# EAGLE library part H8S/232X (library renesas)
H8S/232Xseries in120 pin package

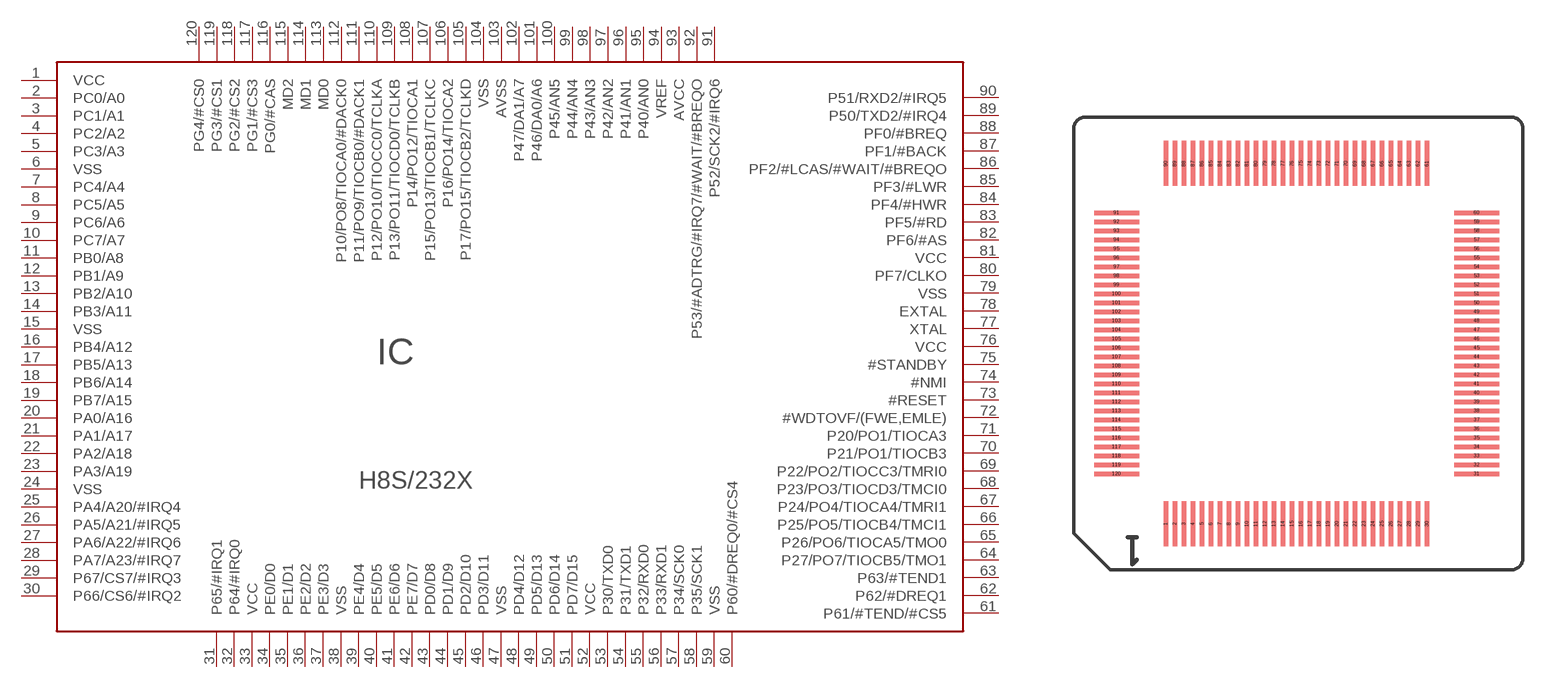
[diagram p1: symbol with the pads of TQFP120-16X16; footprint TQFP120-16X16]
Designator prefix IC

## H8S/232X-120  [TQFP120-16X16]
1  VCC  pwr
2  PC0/A0
3  PC1/A1
4  PC2/A2
5  PC3/A3
6  VSS  pwr
7  PC4/A4
8  PC5/A5
9  PC6/A6
10  PC7/A7
11  PB0/A8
12  PB1/A9
13  PB2/A10
14  PB3/A11
15  VSS  pwr
16  PB4/A12
17  PB5/A13
18  PB6/A14
19  PB7/A15
20  PA0/A16
21  PA1/A17
22  PA2/A18
23  PA3/A19
24  VSS  pwr
25  PA4/A20/#IRQ4
26  PA5/A21/#IRQ5
27  PA6/A22/#IRQ6
28  PA7/A23/#IRQ7
29  P67/CS7/#IRQ3
30  P66/CS6/#IRQ2
31  P65/#IRQ1
32  P64/#IRQ0
33  VCC  pwr
34  PE0/D0
35  PE1/D1
36  PE2/D2
37  PE3/D3
38  VSS  pwr
39  PE4/D4
40  PE5/D5
41  PE6/D6
42  PE7/D7
43  PD0/D8
44  PD1/D9
45  PD2/D10
46  PD3/D11
47  VSS  pwr
48  PD4/D12
49  PD5/D13
50  PD6/D14
51  PD7/D15
52  VCC  pwr
53  P30/TXD0
54  P31/TXD1
55  P32/RXD0
56  P33/RXD1
57  P34/SCK0
58  P35/SCK1
59  VSS  pwr
60  P60/#DREQ0/#CS4
61  P61/#TEND/#CS5
62  P62/#DREQ1
63  P63/#TEND1
64  P27/PO7/TIOCB5/TMO1
65  P26/PO6/TIOCA5/TMO0
66  P25/PO5/TIOCB4/TMCI1
67  P24/PO4/TIOCA4/TMRI1
68  P23/PO3/TIOCD3/TMCI0
69  P22/PO2/TIOCC3/TMRI0
70  P21/PO1/TIOCB3
71  P20/PO1/TIOCA3
72  #WDTOVF/(FWE,EMLE)
73  #RESET  in
74  #NMI  in
75  #STANDBY  in
76  VCC  pwr
77  XTAL  pas
78  EXTAL  in
79  VSS  pwr
80  PF7/CLKO
81  VCC  pwr
82  PF6/#AS
83  PF5/#RD
84  PF4/#HWR
85  PF3/#LWR
86  PF2/#LCAS/#WAIT/#BREQO
87  PF1/#BACK
88  PF0/#BREQ
89  P50/TXD2/#IRQ4
90  P51/RXD2/#IRQ5
91  P52/SCK2/#IRQ6
92  P53/#ADTRG/#IRQ7/#WAIT/#BREQO
93  AVCC  pwr
94  VREF  pwr
95  P40/AN0
96  P41/AN1
97  P42/AN2
98  P43/AN3
99  P44/AN4
100  P45/AN5
101  P46/DA0/A6
102  P47/DA1/A7
103  AVSS  pwr
104  VSS  pwr
105  P17/PO15/TIOCB2/TCLKD
106  P16/PO14/TIOCA2
107  P15/PO13/TIOCB1/TCLKC
108  P14/PO12/TIOCA1
109  P13/PO11/TIOCD0/TCLKB
110  P12/PO10/TIOCC0/TCLKA
111  P11/PO9/TIOCB0/#DACK1
112  P10/PO8/TIOCA0/#DACK0
113  MD0  in
114  MD1  in
115  MD2  in
116  PG0/#CAS
117  PG1/#CS3
118  PG2/#CS2
119  PG3/#CS1
120  PG4/#CS0

## Footprint TQFP120-16X16 (pad centres in mm)
TQFP120 16x16mm 0.4mm pitch 0.2mm pad width
smd 0.2 x 2: 1 -5.8,-8; 2 -5.4,-8; 3 -5,-8; 4 -4.6,-8; 5 -4.2,-8; 6 -3.8,-8; 7 -3.4,-8; 8 -3,-8; 9 -2.6,-8; 10 -2.2,-8; 11 -1.8,-8; 12 -1.4,-8; 13 -1,-8; 14 -0.6,-8; 15 -0.2,-8; 16 0.2,-8; 17 0.6,-8; 18 1,-8; 19 1.4,-8; 20 1.8,-8; 21 2.2,-8; 22 2.6,-8; 23 3,-8; 24 3.4,-8; 25 3.8,-8; 26 4.2,-8; 27 4.6,-8; 28 5,-8; 29 5.4,-8; 30 5.8,-8; 61 5.8,8; 62 5.4,8; 63 5,8; 64 4.6,8; 65 4.2,8; 66 3.8,8; 67 3.4,8; 68 3,8; 69 2.6,8; 70 2.2,8; 71 1.8,8; 72 1.4,8; 73 1,8; 74 0.6,8; 75 0.2,8; 76 -0.2,8; 77 -0.6,8; 78 -1,8; 79 -1.4,8; 80 -1.8,8; 81 -2.2,8; 82 -2.6,8; 83 -3,8; 84 -3.4,8; 85 -3.8,8; 86 -4.2,8; 87 -4.6,8; 88 -5,8; 89 -5.4,8; 90 -5.8,8
smd 2 x 0.2: 31 8,-5.8; 32 8,-5.4; 33 8,-5; 34 8,-4.6; 35 8,-4.2; 36 8,-3.8; 37 8,-3.4; 38 8,-3; 39 8,-2.6; 40 8,-2.2; 41 8,-1.8; 42 8,-1.4; 43 8,-1; 44 8,-0.6; 45 8,-0.2; 46 8,0.2; 47 8,0.6; 48 8,1; 49 8,1.4; 50 8,1.8; 51 8,2.2; 52 8,2.6; 53 8,3; 54 8,3.4; 55 8,3.8; 56 8,4.2; 57 8,4.6; 58 8,5; 59 8,5.4; 60 8,5.8; 91 -8,5.8; 92 -8,5.4; 93 -8,5; 94 -8,4.6; 95 -8,4.2; 96 -8,3.8; 97 -8,3.4; 98 -8,3; 99 -8,2.6; 100 -8,2.2; 101 -8,1.8; 102 -8,1.4; 103 -8,1; 104 -8,0.6; 105 -8,0.2; 106 -8,-0.2; 107 -8,-0.6; 108 -8,-1; 109 -8,-1.4; 110 -8,-1.8; 111 -8,-2.2; 112 -8,-2.6; 113 -8,-3; 114 -8,-3.4; 115 -8,-3.8; 116 -8,-4.2; 117 -8,-4.6; 118 -8,-5; 119 -8,-5.4; 120 -8,-5.8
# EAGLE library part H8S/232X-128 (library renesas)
H8S/232X series in 128pin package

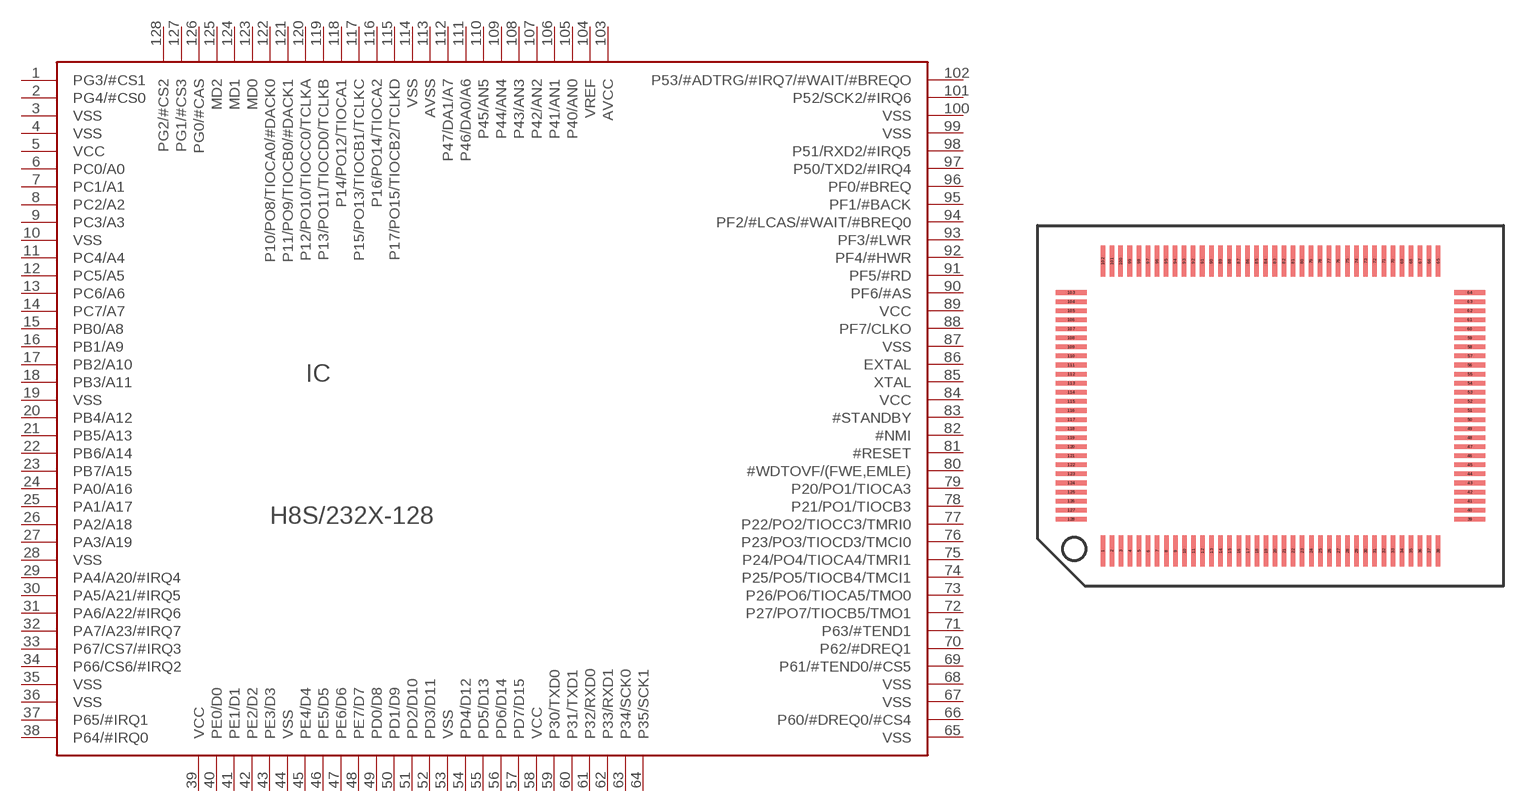
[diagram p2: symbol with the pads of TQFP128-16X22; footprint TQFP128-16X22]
Designator prefix IC

## H8S/232X-128  [TQFP128-16X22]
1  PG3/#CS1
2  PG4/#CS0
3  VSS  pwr
4  VSS  pwr
5  VCC  pwr
6  PC0/A0
7  PC1/A1
8  PC2/A2
9  PC3/A3
10  VSS  pwr
11  PC4/A4
12  PC5/A5
13  PC6/A6
14  PC7/A7
15  PB0/A8
16  PB1/A9
17  PB2/A10
18  PB3/A11
19  VSS  pwr
20  PB4/A12
21  PB5/A13
22  PB6/A14
23  PB7/A15
24  PA0/A16
25  PA1/A17
26  PA2/A18
27  PA3/A19
28  VSS  pwr
29  PA4/A20/#IRQ4
30  PA5/A21/#IRQ5
31  PA6/A22/#IRQ6
32  PA7/A23/#IRQ7
33  P67/CS7/#IRQ3
34  P66/CS6/#IRQ2
35  VSS  pwr
36  VSS  pwr
37  P65/#IRQ1
38  P64/#IRQ0
39  VCC  pwr
40  PE0/D0
41  PE1/D1
42  PE2/D2
43  PE3/D3
44  VSS  pwr
45  PE4/D4
46  PE5/D5
47  PE6/D6
48  PE7/D7
49  PD0/D8
50  PD1/D9
51  PD2/D10
52  PD3/D11
53  VSS  pwr
54  PD4/D12
55  PD5/D13
56  PD6/D14
57  PD7/D15
58  VCC  pwr
59  P30/TXD0
60  P31/TXD1
61  P32/RXD0
62  P33/RXD1
63  P34/SCK0
64  P35/SCK1
65  VSS  pwr
66  P60/#DREQ0/#CS4
67  VSS  pwr
68  VSS  pwr
69  P61/#TEND0/#CS5
70  P62/#DREQ1
71  P63/#TEND1
72  P27/PO7/TIOCB5/TMO1
73  P26/PO6/TIOCA5/TMO0
74  P25/PO5/TIOCB4/TMCI1
75  P24/PO4/TIOCA4/TMRI1
76  P23/PO3/TIOCD3/TMCI0
77  P22/PO2/TIOCC3/TMRI0
78  P21/PO1/TIOCB3
79  P20/PO1/TIOCA3
80  #WDTOVF/(FWE,EMLE)  in
81  #RESET  in
82  #NMI  in
83  #STANDBY  in
84  VCC  pwr
85  XTAL  pas
86  EXTAL  in
87  VSS  pwr
88  PF7/CLKO
89  VCC  pwr
90  PF6/#AS
91  PF5/#RD
92  PF4/#HWR
93  PF3/#LWR
94  PF2/#LCAS/#WAIT/#BREQ0
95  PF1/#BACK
96  PF0/#BREQ
97  P50/TXD2/#IRQ4
98  P51/RXD2/#IRQ5
99  VSS  pwr
100  VSS  pwr
101  P52/SCK2/#IRQ6
102  P53/#ADTRG/#IRQ7/#WAIT/#BREQO
103  AVCC  pwr
104  VREF  pwr
105  P40/AN0
106  P41/AN1
107  P42/AN2
108  P43/AN3
109  P44/AN4
110  P45/AN5
111  P46/DA0/A6
112  P47/DA1/A7
113  AVSS  pwr
114  VSS  pwr
115  P17/PO15/TIOCB2/TCLKD
116  P16/PO14/TIOCA2
117  P15/PO13/TIOCB1/TCLKC
118  P14/PO12/TIOCA1
119  P13/PO11/TIOCD0/TCLKB
120  P12/PO10/TIOCC0/TCLKA
121  P11/PO9/TIOCB0/#DACK1
122  P10/PO8/TIOCA0/#DACK0
123  MD0  in
124  MD1  in
125  MD2  in
126  PG0/#CAS
127  PG1/#CS3
128  PG2/#CS2

## Footprint TQFP128-16X22 (pad centres in mm)
TQFP128 16x22mm 0.5mm pitch 0.25mm pad width
smd 0.25 x 1.7: 1 -9.25,-8; 2 -8.75,-8; 3 -8.25,-8; 4 -7.75,-8; 5 -7.25,-8; 6 -6.75,-8; 7 -6.25,-8; 8 -5.75,-8; 9 -5.25,-8; 10 -4.75,-8; 11 -4.25,-8; 12 -3.75,-8; 13 -3.25,-8; 14 -2.75,-8; 15 -2.25,-8; 16 -1.75,-8; 17 -1.25,-8; 18 -0.75,-8; 19 -0.25,-8; 20 0.25,-8; 21 0.75,-8; 22 1.25,-8; 23 1.75,-8; 24 2.25,-8; 25 2.75,-8; 26 3.25,-8; 27 3.75,-8; 28 4.25,-8; 29 4.75,-8; 30 5.25,-8; 31 5.75,-8; 32 6.25,-8; 33 6.75,-8; 34 7.25,-8; 35 7.75,-8; 36 8.25,-8; 37 8.75,-8; 38 9.25,-8; 65 9.25,8; 66 8.75,8; 67 8.25,8; 68 7.75,8; 69 7.25,8; 70 6.75,8; 71 6.25,8; 72 5.75,8; 73 5.25,8; 74 4.75,8; 75 4.25,8; 76 3.735,7.995; 77 3.235,7.995; 78 2.735,7.995; 79 2.235,7.995; 80 1.735,7.995; 81 1.235,7.995; 82 0.735,7.995; 83 0.235,7.995; 84 -0.265,7.995; 85 -0.765,7.995; 86 -1.265,7.995; 87 -1.765,7.995; 88 -2.265,7.995; 89 -2.765,7.995; 90 -3.265,7.995; 91 -3.765,7.995; 92 -4.265,7.995; 93 -4.765,7.995; 94 -5.265,7.995; 95 -5.765,7.995; 96 -6.265,7.995; 97 -6.765,7.995; 98 -7.265,7.995; 99 -7.765,7.995; 100 -8.265,7.995; 101 -8.75,8; 102 -9.25,8
smd 1.7 x 0.25: 39 11,-6.25; 40 11,-5.75; 41 11,-5.25; 42 11,-4.75; 43 11,-4.25; 44 11,-3.75; 45 11,-3.25; 46 11,-2.75; 47 11,-2.25; 48 11,-1.75; 49 11,-1.25; 50 11,-0.75; 51 11,-0.24; 52 11,0.26; 53 11,0.76; 54 11,1.26; 55 11,1.76; 56 11,2.26; 57 11,2.76; 58 11,3.26; 59 11,3.76; 60 11,4.26; 61 11,4.76; 62 11,5.26; 63 11,5.76; 64 11,6.26; 103 -11,6.26; 104 -11,5.76; 105 -11,5.26; 106 -11,4.76; 107 -11,4.26; 108 -11,3.76; 109 -11,3.26; 110 -11,2.76; 111 -11,2.26; 112 -11,1.76; 113 -11,1.26; 114 -11,0.76; 115 -11,0.25; 116 -11,-0.25; 117 -11,-0.75; 118 -11,-1.25; 119 -11,-1.75; 120 -11,-2.25; 121 -11,-2.75; 122 -11,-3.25; 123 -11,-3.75; 124 -11,-4.25; 125 -11,-4.75; 126 -11,-5.25; 127 -11,-5.75; 128 -11,-6.25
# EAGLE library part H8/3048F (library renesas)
H8/3048F in 100pin package

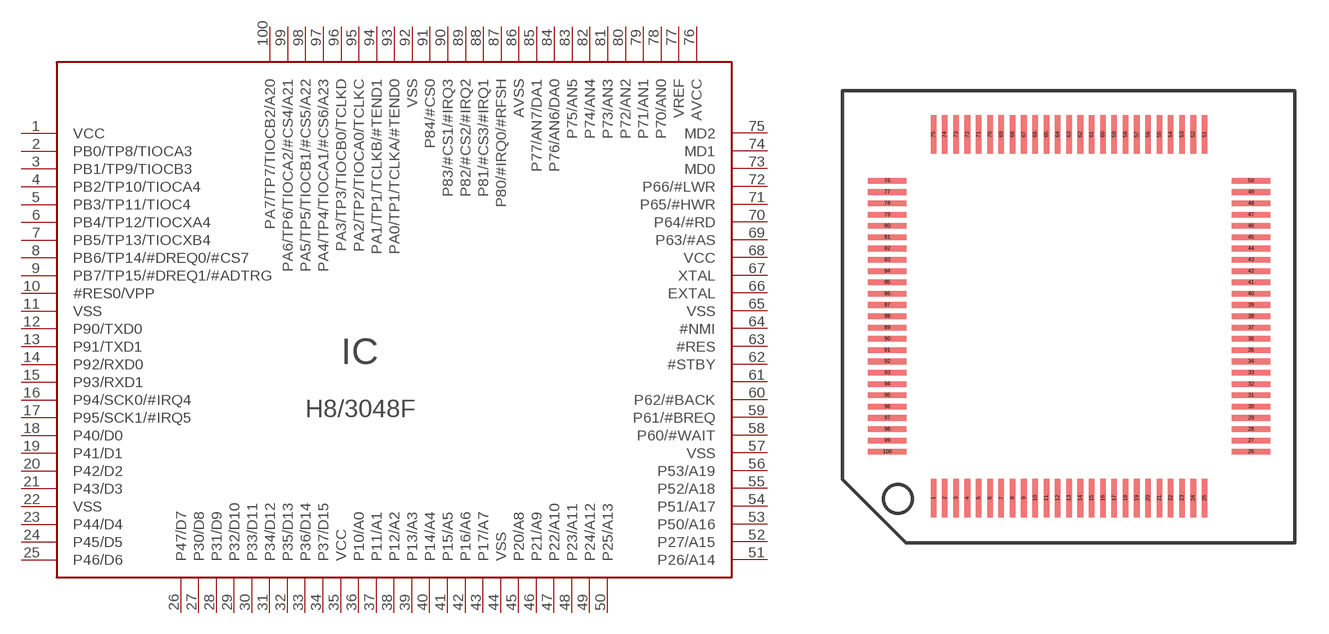
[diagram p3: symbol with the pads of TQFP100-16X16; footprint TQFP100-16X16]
Designator prefix IC

## H8/3048F  [TQFP100-16X16]
1  VCC  pwr
2  PB0/TP8/TIOCA3
3  PB1/TP9/TIOCB3
4  PB2/TP10/TIOCA4
5  PB3/TP11/TIOC4
6  PB4/TP12/TIOCXA4
7  PB5/TP13/TIOCXB4
8  PB6/TP14/#DREQ0/#CS7
9  PB7/TP15/#DREQ1/#ADTRG
10  #RES0/VPP
11  VSS  pwr
12  P90/TXD0
13  P91/TXD1
14  P92/RXD0
15  P93/RXD1
16  P94/SCK0/#IRQ4
17  P95/SCK1/#IRQ5
18  P40/D0
19  P41/D1
20  P42/D2
21  P43/D3
22  VSS  pwr
23  P44/D4
24  P45/D5
25  P46/D6
26  P47/D7
27  P30/D8
28  P31/D9
29  P32/D10
30  P33/D11
31  P34/D12
32  P35/D13
33  P36/D14
34  P37/D15
35  VCC  pwr
36  P10/A0
37  P11/A1
38  P12/A2
39  P13/A3
40  P14/A4
41  P15/A5
42  P16/A6
43  P17/A7
44  VSS  pwr
45  P20/A8
46  P21/A9
47  P22/A10
48  P23/A11
49  P24/A12
50  P25/A13
51  P26/A14
52  P27/A15
53  P50/A16
54  P51/A17
55  P52/A18
56  P53/A19
57  VSS  pwr
58  P60/#WAIT
59  P61/#BREQ
60  P62/#BACK
61    out
62  #STBY  in
63  #RES  in
64  #NMI  in
65  VSS  pwr
66  EXTAL  in
67  XTAL  pas
68  VCC  pwr
69  P63/#AS
70  P64/#RD
71  P65/#HWR
72  P66/#LWR
73  MD0
74  MD1
75  MD2
76  AVCC  pwr
77  VREF  pas
78  P70/AN0
79  P71/AN1
80  P72/AN2
81  P73/AN3
82  P74/AN4
83  P75/AN5
84  P76/AN6/DA0
85  P77/AN7/DA1
86  AVSS  pwr
87  P80/#IRQ0/#RFSH
88  P81/#CS3/#IRQ1
89  P82/#CS2/#IRQ2
90  P83/#CS1/#IRQ3
91  P84/#CS0
92  VSS  pwr
93  PA0/TP1/TCLKA/#TEND0
94  PA1/TP1/TCLKB/#TEND1
95  PA2/TP2/TIOCA0/TCLKC
96  PA3/TP3/TIOCB0/TCLKD
97  PA4/TP4/TIOCA1/#CS6/A23
98  PA5/TP5/TIOCB1/#CS5/A22
99  PA6/TP6/TIOCA2/#CS4/A21
100  PA7/TP7/TIOCB2/A20

## Footprint TQFP100-16X16 (pad centres in mm)
TQFP100 16x16mm 0.5mm pitch 0.25mm pad width
smd 0.25 x 1.7: 1 -6,-8.05; 2 -5.5,-8.05; 3 -5,-8.05; 4 -4.5,-8.05; 5 -4,-8.05; 6 -3.5,-8.05; 7 -3,-8.05; 8 -2.5,-8.05; 9 -2,-8.05; 10 -1.5,-8.05; 11 -1,-8.05; 12 -0.5,-8.05; 13 0,-8.05; 14 0.5,-8.05; 15 1,-8.05; 16 1.5,-8.05; 17 2,-8.05; 18 2.5,-8.05; 19 3,-8.05; 20 3.5,-8.05; 21 4,-8.05; 22 4.5,-8.05; 23 5,-8.05; 24 5.5,-8.05; 25 6,-8.05; 51 6,8.05; 52 5.5,8.05; 53 5,8.05; 54 4.5,8.05; 55 4,8.05; 56 3.5,8.05; 57 3,8.05; 58 2.5,8.05; 59 2,8.05; 60 1.5,8.05; 61 1,8.05; 62 0.5,8.05; 63 0,8.05; 64 -0.5,8.05; 65 -1,8.05; 66 -1.5,8.05; 67 -2,8.05; 68 -2.5,8.05; 69 -3,8.05; 70 -3.5,8.05; 71 -4,8.05; 72 -4.5,8.05; 73 -5,8.05; 74 -5.5,8.05; 75 -6,8.05
smd 1.7 x 0.25: 26 8.05,-6; 27 8.05,-5.5; 28 8.05,-5; 29 8.05,-4.5; 30 8.05,-4; 31 8.05,-3.5; 32 8.05,-3; 33 8.05,-2.5; 34 8.05,-2; 35 8.05,-1.5; 36 8.05,-1; 37 8.05,-0.5; 38 8.05,0; 39 8.05,0.5; 40 8.05,1; 41 8.05,1.5; 42 8.05,2; 43 8.05,2.5; 44 8.05,3; 45 8.05,3.5; 46 8.05,4; 47 8.05,4.5; 48 8.05,5; 49 8.05,5.5; 50 8.05,6; 76 -8.05,6; 77 -8.05,5.5; 78 -8.05,5; 79 -8.05,4.5; 80 -8.05,4; 81 -8.05,3.5; 82 -8.05,3; 83 -8.05,2.5; 84 -8.05,2; 85 -8.05,1.5; 86 -8.05,1; 87 -8.05,0.5; 88 -8.05,0; 89 -8.05,-0.5; 90 -8.05,-1; 91 -8.05,-1.5; 92 -8.05,-2; 93 -8.05,-2.5; 94 -8.05,-3; 95 -8.05,-3.5; 96 -8.05,-4; 97 -8.05,-4.5; 98 -8.05,-5; 99 -8.05,-5.5; 100 -8.05,-6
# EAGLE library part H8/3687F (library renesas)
H8/3687F in 64 pin package

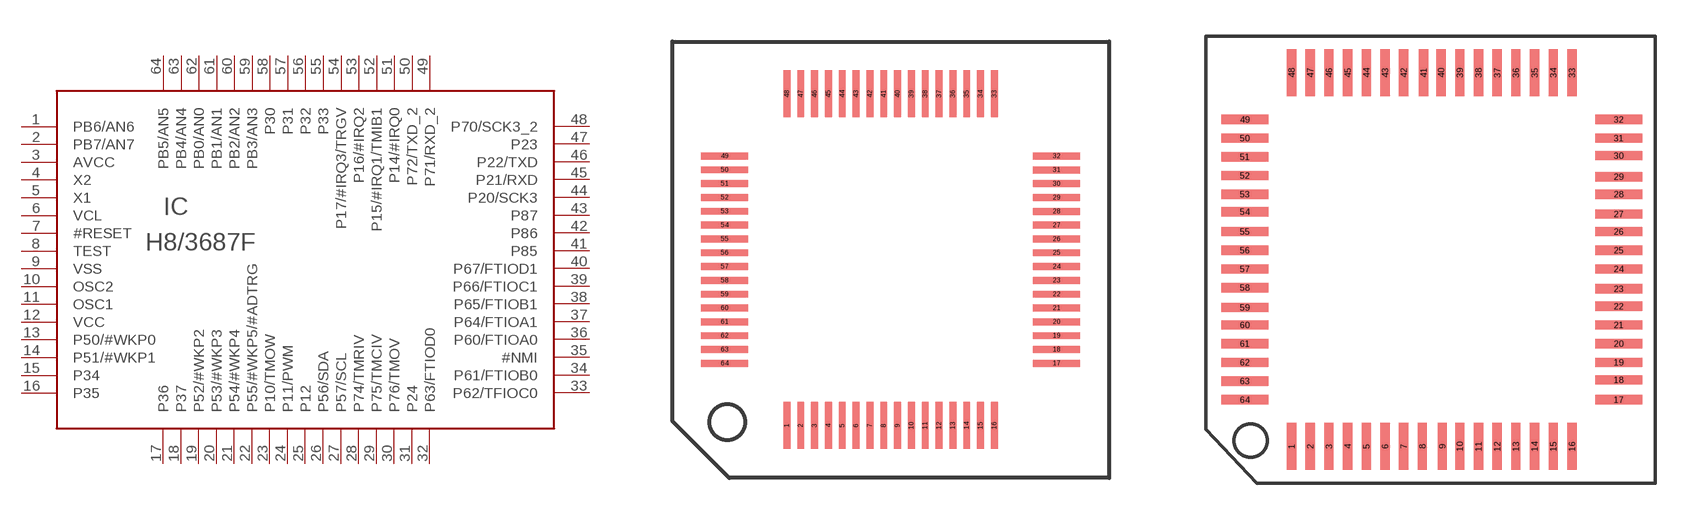
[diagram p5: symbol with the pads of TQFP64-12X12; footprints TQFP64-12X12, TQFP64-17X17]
Designator prefix IC

## H8/3687F-12X12  [TQFP64-12X12]
1  PB6/AN6
2  PB7/AN7
3  AVCC  pwr
4  X2  pas
5  X1  in
6  VCL  pwr
7  #RESET  in
8  TEST  in
9  VSS  pwr
10  OSC2  pas
11  OSC1  in
12  VCC  pwr
13  P50/#WKP0
14  P51/#WKP1
15  P34
16  P35
17  P36
18  P37
19  P52/#WKP2
20  P53/#WKP3
21  P54/#WKP4
22  P55/#WKP5/#ADTRG
23  P10/TMOW
24  P11/PWM
25  P12
26  P56/SDA
27  P57/SCL
28  P74/TMRIV
29  P75/TMCIV
30  P76/TMOV
31  P24
32  P63/FTIOD0
33  P62/TFIOC0
34  P61/FTIOB0
35  #NMI  in
36  P60/FTIOA0
37  P64/FTIOA1
38  P65/FTIOB1
39  P66/FTIOC1
40  P67/FTIOD1
41  P85
42  P86
43  P87
44  P20/SCK3
45  P21/RXD
46  P22/TXD
47  P23
48  P70/SCK3_2
49  P71/RXD_2
50  P72/TXD_2
51  P14/#IRQ0
52  P15/#IRQ1/TMIB1
53  P16/#IRQ2
54  P17/#IRQ3/TRGV
55  P33
56  P32
57  P31
58  P30
59  PB3/AN3
60  PB2/AN2
61  PB1/AN1
62  PB0/AN0
63  PB4/AN4
64  PB5/AN5

## H8/3687F-17X17  [TQFP64-17X17]
Pads as for TQFP64-12X12

## Footprint TQFP64-12X12 (pad centres in mm)
TQFP64 12x12mm 0.5mm pitch 0.25mm pad width
smd 0.25 x 1.7: 1 -3.75,-6; 2 -3.25,-6; 3 -2.75,-6; 4 -2.25,-6; 5 -1.75,-6; 6 -1.25,-6; 7 -0.75,-6; 8 -0.25,-6; 9 0.25,-6; 10 0.75,-6; 11 1.25,-6; 12 1.75,-6; 13 2.25,-6; 14 2.75,-6; 15 3.25,-6; 16 3.75,-6; 33 3.75,6; 34 3.25,6; 35 2.75,6; 36 2.25,6; 37 1.75,6; 38 1.25,6; 39 0.75,6; 40 0.25,6; 41 -0.25,6; 42 -0.75,6; 43 -1.25,6; 44 -1.75,6; 45 -2.25,6; 46 -2.75,6; 47 -3.25,6; 48 -3.75,6
smd 1.7 x 0.25: 17 6,-3.75; 18 6,-3.25; 19 6,-2.75; 20 6,-2.25; 21 6,-1.75; 22 6,-1.25; 23 6,-0.75; 24 6,-0.25; 25 6,0.25; 26 6,0.747; 27 6,1.247; 28 6,1.747; 29 6,2.247; 30 6,2.747; 31 6,3.247; 32 6,3.747; 49 -6,3.75; 50 -6,3.25; 51 -6,2.75; 52 -6,2.25; 53 -6,1.75; 54 -6,1.25; 55 -6,0.75; 56 -6,0.25; 57 -6,-0.25; 58 -6,-0.75; 59 -6,-1.25; 60 -6,-1.75; 61 -6,-2.25; 62 -6,-2.75; 63 -6,-3.25; 64 -6,-3.75

## Footprint TQFP64-17X17 (pad centres in mm)
TQFP64 17x17mm 0.8mm pitch 0.4mm pad width
smd 0.4 x 2: 1 -6,-8; 2 -5.2,-8; 3 -4.4,-8; 4 -3.6,-8; 5 -2.8,-8; 6 -2,-8; 7 -1.2,-8; 8 -0.4,-8; 9 0.45,-8; 10 1.2,-8; 11 2,-8; 12 2.8,-8; 13 3.6,-8; 14 4.4,-8; 15 5.2,-8; 16 6,-8; 33 6,8; 34 5.2,8; 35 4.4,8; 36 3.6,8; 37 2.8,8; 38 2,8; 39 1.2,8; 40 0.4,8; 41 -0.35,8; 42 -1.2,8; 43 -2,8; 44 -2.8,8; 45 -3.6,8; 46 -4.4,8; 47 -5.2,8; 48 -6,8
smd 2 x 0.4: 17 8,-6; 18 8,-5.15; 19 8,-4.4; 20 8,-3.6; 21 8,-2.8; 22 8,-2; 23 8,-1.25; 24 8,-0.4; 25 8,0.4; 26 8,1.2; 27 8,1.95; 28 8,2.8; 29 8,3.55; 30 8,4.45; 31 8,5.2; 32 8,6; 49 -8,6; 50 -8,5.2; 51 -8,4.4; 52 -8,3.6; 53 -8,2.8; 54 -8,2.05; 55 -8,1.2; 56 -8,0.4; 57 -8,-0.4; 58 -8,-1.2; 59 -8,-2.05; 60 -8,-2.8; 61 -8,-3.6; 62 -8,-4.4; 63 -8,-5.2; 64 -8,-6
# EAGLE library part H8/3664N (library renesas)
H8/3664N EEPROM version in 64pin package

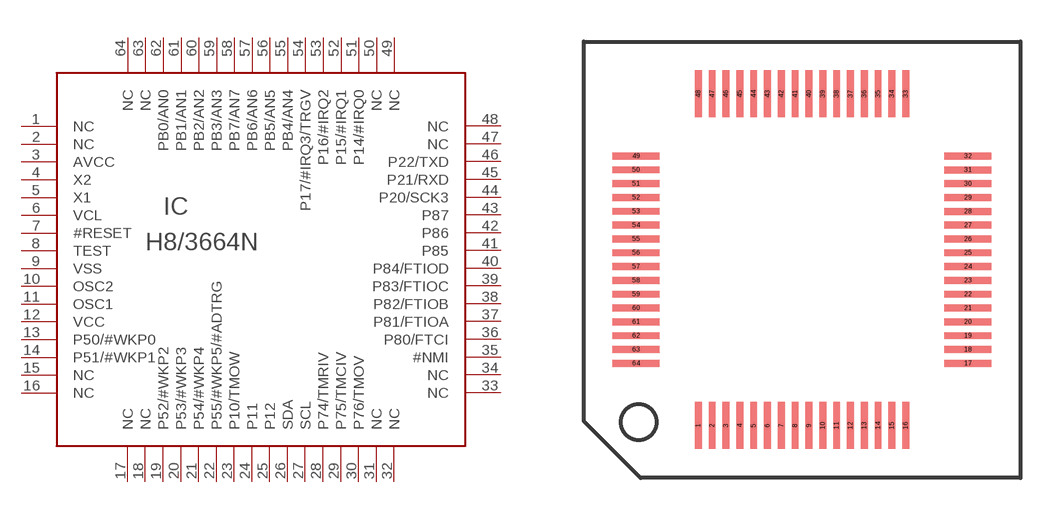
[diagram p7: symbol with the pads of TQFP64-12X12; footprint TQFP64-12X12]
Designator prefix IC

## H8/3664N  [TQFP64-12X12]
1  NC  nc
2  NC  nc
3  AVCC  pwr
4  X2  pas
5  X1  in
6  VCL  pwr
7  #RESET  in
8  TEST  in
9  VSS  pwr
10  OSC2  pas
11  OSC1  in
12  VCC  pwr
13  P50/#WKP0
14  P51/#WKP1
15  NC  nc
16  NC  nc
17  NC  nc
18  NC  nc
19  P52/#WKP2
20  P53/#WKP3
21  P54/#WKP4
22  P55/#WKP5/#ADTRG
23  P10/TMOW
24  P11
25  P12
26  SDA
27  SCL
28  P74/TMRIV
29  P75/TMCIV
30  P76/TMOV
31  NC  nc
32  NC  nc
33  NC  nc
34  NC  nc
35  #NMI  in
36  P80/FTCI
37  P81/FTIOA
38  P82/FTIOB
39  P83/FTIOC
40  P84/FTIOD
41  P85
42  P86
43  P87
44  P20/SCK3
45  P21/RXD
46  P22/TXD
47  NC  nc
48  NC  nc
49  NC  nc
50  NC  nc
51  P14/#IRQ0
52  P15/#IRQ1
53  P16/#IRQ2
54  P17/#IRQ3/TRGV
55  PB4/AN4
56  PB5/AN5
57  PB6/AN6
58  PB7/AN7
59  PB3/AN3
60  PB2/AN2
61  PB1/AN1
62  PB0/AN0
63  NC  nc
64  NC  nc

## Footprint TQFP64-12X12 (pad centres in mm)
TQFP64 12x12mm 0.5mm pitch 0.25mm pad width
smd 0.25 x 1.7: 1 -3.75,-6; 2 -3.25,-6; 3 -2.75,-6; 4 -2.25,-6; 5 -1.75,-6; 6 -1.25,-6; 7 -0.75,-6; 8 -0.25,-6; 9 0.25,-6; 10 0.75,-6; 11 1.25,-6; 12 1.75,-6; 13 2.25,-6; 14 2.75,-6; 15 3.25,-6; 16 3.75,-6; 33 3.75,6; 34 3.25,6; 35 2.75,6; 36 2.25,6; 37 1.75,6; 38 1.25,6; 39 0.75,6; 40 0.25,6; 41 -0.25,6; 42 -0.75,6; 43 -1.25,6; 44 -1.75,6; 45 -2.25,6; 46 -2.75,6; 47 -3.25,6; 48 -3.75,6
smd 1.7 x 0.25: 17 6,-3.75; 18 6,-3.25; 19 6,-2.75; 20 6,-2.25; 21 6,-1.75; 22 6,-1.25; 23 6,-0.75; 24 6,-0.25; 25 6,0.25; 26 6,0.747; 27 6,1.247; 28 6,1.747; 29 6,2.247; 30 6,2.747; 31 6,3.247; 32 6,3.747; 49 -6,3.75; 50 -6,3.25; 51 -6,2.75; 52 -6,2.25; 53 -6,1.75; 54 -6,1.25; 55 -6,0.75; 56 -6,0.25; 57 -6,-0.25; 58 -6,-0.75; 59 -6,-1.25; 60 -6,-1.75; 61 -6,-2.25; 62 -6,-2.75; 63 -6,-3.25; 64 -6,-3.75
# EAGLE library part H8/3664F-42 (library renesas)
H8/3664F in 42 pin DIP package

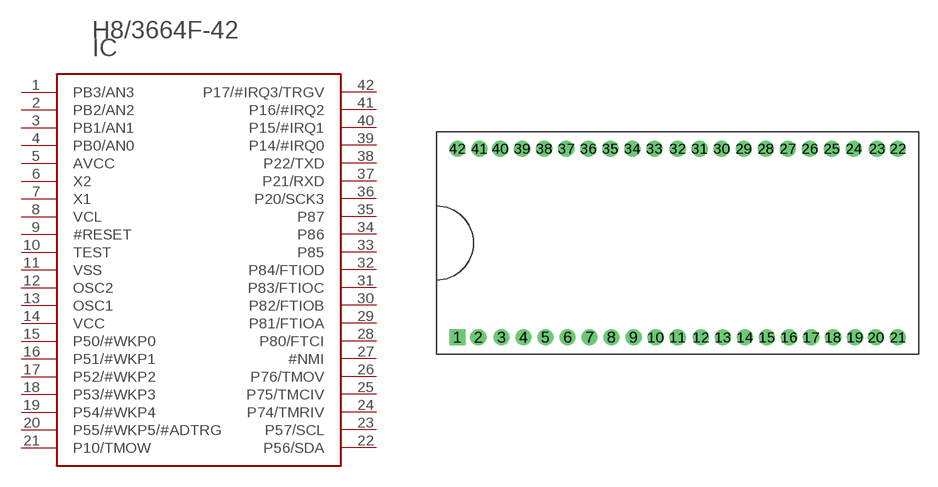
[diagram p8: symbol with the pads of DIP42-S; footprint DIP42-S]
Designator prefix IC

## H8/3664F-42  [DIP42-S]
1  PB3/AN3
2  PB2/AN2
3  PB1/AN1
4  PB0/AN0
5  AVCC  pwr
6  X2  pas
7  X1  in
8  VCL  pwr
9  #RESET  in
10  TEST  in
11  VSS  pwr
12  OSC2  pas
13  OSC1  in
14  VCC  pwr
15  P50/#WKP0
16  P51/#WKP1
17  P52/#WKP2
18  P53/#WKP3
19  P54/#WKP4
20  P55/#WKP5/#ADTRG
21  P10/TMOW
22  P56/SDA
23  P57/SCL
24  P74/TMRIV
25  P75/TMCIV
26  P76/TMOV
27  #NMI  in
28  P80/FTCI
29  P81/FTIOA
30  P82/FTIOB
31  P83/FTIOC
32  P84/FTIOD
33  P85
34  P86
35  P87
36  P20/SCK3
37  P21/RXD
38  P22/TXD
39  P14/#IRQ0
40  P15/#IRQ1
41  P16/#IRQ2
42  P17/#IRQ3/TRGV

## Footprint DIP42-S (pad centres in mm)
42pin Dip Shrink 1.78mm pitch pins, 15.24mm pitch rows
drill 0.8 pad 1.2 square: 1 -17.8,-7.62
drill 0.8 pad 1.2 round: 2 -16.12,-7.62; 3 -14.24,-7.62; 4 -12.46,-7.62; 5 -10.68,-7.62; 6 -8.9,-7.62; 7 -7.12,-7.62; 8 -5.34,-7.62; 9 -3.56,-7.62; 10 -1.78,-7.62; 11 0,-7.62; 12 1.88,-7.62; 13 3.66,-7.62; 14 5.44,-7.62; 15 7.22,-7.62; 16 9,-7.62; 17 10.78,-7.62; 18 12.56,-7.62; 19 14.34,-7.62; 20 16.02,-7.62; 21 17.8,-7.62; 22 17.8,7.62; 23 16.12,7.62; 24 14.24,7.62; 25 12.46,7.62; 26 10.68,7.62; 27 8.9,7.62; 28 7.12,7.62; 29 5.34,7.62; 30 3.56,7.62; 31 1.78,7.62; 32 0,7.62; 33 -1.88,7.62; 34 -3.66,7.62; 35 -5.44,7.62; 36 -7.22,7.62; 37 -9,7.62; 38 -10.78,7.62; 39 -12.56,7.62; 40 -14.34,7.62; 41 -16.02,7.62; 42 -17.8,7.62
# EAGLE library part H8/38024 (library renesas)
H8/38024 SLP in QFP80

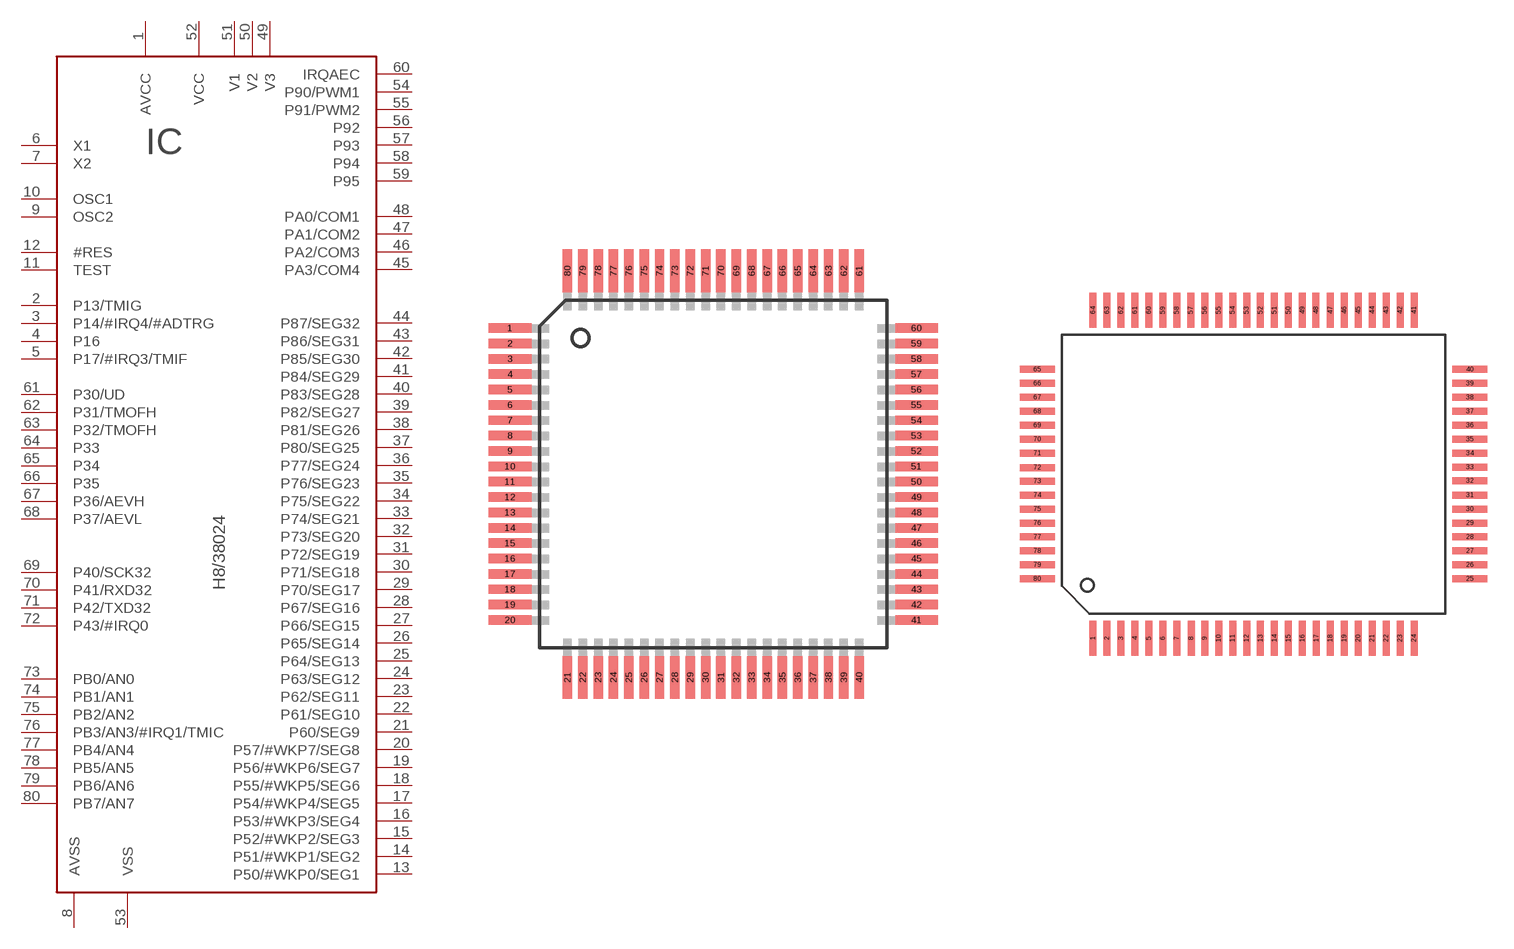
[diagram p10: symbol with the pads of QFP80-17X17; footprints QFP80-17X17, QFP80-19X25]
Designator prefix IC

## H8/38024H  [QFP80-17X17]
1  AVCC  pwr
2  P13/TMIG
3  P14/#IRQ4/#ADTRG
4  P16
5  P17/#IRQ3/TMIF
6  X1  in
7  X2  pas
8  AVSS  pwr
9  OSC2  pas
10  OSC1  in
11  TEST  in
12  #RES  in
13  P50/#WKP0/SEG1
14  P51/#WKP1/SEG2
15  P52/#WKP2/SEG3
16  P53/#WKP3/SEG4
17  P54/#WKP4/SEG5
18  P55/#WKP5/SEG6
19  P56/#WKP6/SEG7
20  P57/#WKP7/SEG8
21  P60/SEG9
22  P61/SEG10
23  P62/SEG11
24  P63/SEG12
25  P64/SEG13
26  P65/SEG14
27  P66/SEG15
28  P67/SEG16
29  P70/SEG17
30  P71/SEG18
31  P72/SEG19
32  P73/SEG20
33  P74/SEG21
34  P75/SEG22
35  P76/SEG23
36  P77/SEG24
37  P80/SEG25
38  P81/SEG26
39  P82/SEG27
40  P83/SEG28
41  P84/SEG29
42  P85/SEG30
43  P86/SEG31
44  P87/SEG32
45  PA3/COM4
46  PA2/COM3
47  PA1/COM2
48  PA0/COM1
49  V3  pwr
50  V2  pwr
51  V1  pwr
52  VCC  pwr
53  VSS  pwr
54  P90/PWM1  out
55  P91/PWM2  out
56  P92  out
57  P93  out
58  P94  out
59  P95  out
60  IRQAEC
61  P30/UD
62  P31/TMOFH
63  P32/TMOFH
64  P33
65  P34
66  P35
67  P36/AEVH
68  P37/AEVL
69  P40/SCK32
70  P41/RXD32
71  P42/TXD32
72  P43/#IRQ0  in
73  PB0/AN0  in
74  PB1/AN1  in
75  PB2/AN2  in
76  PB3/AN3/#IRQ1/TMIC  in
77  PB4/AN4  in
78  PB5/AN5  in
79  PB6/AN6  in
80  PB7/AN7  in

## H8/38024F  [QFP80-19X25]
1  PB6/AN6  in
2  PB7/AN7  in
3  AVCC  pwr
4  P13/TMIG
5  P14/#IRQ4/#ADTRG
6  P16
7  P17/#IRQ3/TMIF
8  X1  in
9  X2  pas
10  AVSS  pwr
11  OSC2  pas
12  OSC1  in
13  TEST  in
14  #RES  in
15  P50/#WKP0/SEG1
16  P51/#WKP1/SEG2
17  P52/#WKP2/SEG3
18  P53/#WKP3/SEG4
19  P54/#WKP4/SEG5
20  P55/#WKP5/SEG6
21  P56/#WKP6/SEG7
22  P57/#WKP7/SEG8
23  P60/SEG9
24  P61/SEG10
25  P62/SEG11
26  P63/SEG12
27  P64/SEG13
28  P65/SEG14
29  P66/SEG15
30  P67/SEG16
31  P70/SEG17
32  P71/SEG18
33  P72/SEG19
34  P73/SEG20
35  P74/SEG21
36  P75/SEG22
37  P76/SEG23
38  P77/SEG24
39  P80/SEG25
40  P81/SEG26
41  P82/SEG27
42  P83/SEG28
43  P84/SEG29
44  P85/SEG30
45  P86/SEG31
46  P87/SEG32
47  PA3/COM4
48  PA2/COM3
49  PA1/COM2
50  PA0/COM1
51  V3  pwr
52  V2  pwr
53  V1  pwr
54  VCC  pwr
55  VSS  pwr
56  P90/PWM1  out
57  P91/PWM2  out
58  P92  out
59  P93  out
60  P94  out
61  P95  out
62  IRQAEC
63  P30/UD
64  P31/TMOFH
65  P32/TMOFH
66  P33
67  P34
68  P35
69  P36/AEVH
70  P37/AEVL
71  P40/SCK32
72  P41/RXD32
73  P42/TXD32
74  P43/#IRQ0  in
75  PB0/AN0  in
76  PB1/AN1  in
77  PB2/AN2  in
78  PB3/AN3/#IRQ1/TMIC  in
79  PB4/AN4  in
80  PB5/AN5  in

## H8/38024W  [TQFP80-14X14]
Pads as for QFP80-17X17

## Footprint QFP80-17X17 (pad centres in mm)
QFP80 17mm x 17mm 0.65mm pin pitch
smd 1.8 x 0.4: 1 -8.6,6.175; 2 -8.6,5.525; 3 -8.6,4.875; 4 -8.6,4.225; 5 -8.6,3.575; 6 -8.6,2.925; 7 -8.6,2.275; 8 -8.6,1.625; 9 -8.6,0.975; 10 -8.6,0.325; 11 -8.6,-0.325; 12 -8.6,-0.975; 13 -8.6,-1.625; 14 -8.6,-2.275; 15 -8.6,-2.925; 16 -8.6,-3.575; 17 -8.6,-4.225; 18 -8.6,-4.875; 19 -8.6,-5.525; 20 -8.6,-6.175; 41 8.6,-6.175; 42 8.6,-5.525; 43 8.6,-4.875; 44 8.6,-4.225; 45 8.6,-3.575; 46 8.6,-2.925; 47 8.6,-2.275; 48 8.6,-1.625; 49 8.6,-0.975; 50 8.6,-0.325; 51 8.6,0.325; 52 8.6,0.975; 53 8.6,1.625; 54 8.6,2.275; 55 8.6,2.925; 56 8.6,3.575; 57 8.6,4.225; 58 8.6,4.875; 59 8.6,5.525; 60 8.6,6.175
smd 0.4 x 1.8: 21 -6.175,-8.6; 22 -5.525,-8.6; 23 -4.875,-8.6; 24 -4.225,-8.6; 25 -3.575,-8.6; 26 -2.925,-8.6; 27 -2.275,-8.6; 28 -1.625,-8.6; 29 -0.975,-8.6; 30 -0.325,-8.6; 31 0.325,-8.6; 32 0.975,-8.6; 33 1.625,-8.6; 34 2.275,-8.6; 35 2.925,-8.6; 36 3.575,-8.6; 37 4.225,-8.6; 38 4.875,-8.6; 39 5.525,-8.6; 40 6.175,-8.6; 61 6.175,8.6; 62 5.525,8.6; 63 4.875,8.6; 64 4.225,8.6; 65 3.575,8.6; 66 2.925,8.6; 67 2.275,8.6; 68 1.625,8.6; 69 0.975,8.6; 70 0.325,8.6; 71 -0.325,8.6; 72 -0.975,8.6; 73 -1.625,8.6; 74 -2.275,8.6; 75 -2.925,8.6; 76 -3.575,8.6; 77 -4.225,8.6; 78 -4.875,8.6; 79 -5.525,8.6; 80 -6.175,8.6

## Footprint QFP80-19X25 (pad centres in mm)
QFP80 19mm x 25mm 0.8mm pin pitch
smd 0.4 x 2: 1 -9.2,-9.4; 2 -8.4,-9.4; 3 -7.6,-9.4; 4 -6.8,-9.4; 5 -6,-9.4; 6 -5.2,-9.4; 7 -4.4,-9.4; 8 -3.58,-9.4; 9 -2.8,-9.4; 10 -2,-9.4; 11 -1.2,-9.4; 12 -0.4,-9.4; 13 0.4,-9.4; 14 1.2,-9.4; 15 2,-9.4; 16 2.8,-9.4; 17 3.6,-9.4; 18 4.4,-9.4; 19 5.2,-9.4; 20 6,-9.4; 21 6.8,-9.4; 22 7.6,-9.4; 23 8.4,-9.4; 24 9.2,-9.4; 41 9.2,9.4; 42 8.4,9.4; 43 7.6,9.4; 44 6.8,9.4; 45 6,9.4; 46 5.2,9.4; 47 4.4,9.4; 48 3.58,9.4; 49 2.8,9.4; 50 2,9.4; 51 1.2,9.4; 52 0.4,9.4; 53 -0.4,9.4; 54 -1.2,9.4; 55 -2,9.4; 56 -2.8,9.4; 57 -3.6,9.4; 58 -4.4,9.4; 59 -5.2,9.4; 60 -6,9.4; 61 -6.8,9.4; 62 -7.6,9.4; 63 -8.4,9.4; 64 -9.2,9.4
smd 2 x 0.4: 25 12.4,-6; 26 12.4,-5.2; 27 12.4,-4.4; 28 12.4,-3.6; 29 12.4,-2.8; 30 12.4,-2; 31 12.4,-1.2; 32 12.4,-0.38; 33 12.4,0.4; 34 12.4,1.2; 35 12.4,2; 36 12.4,2.8; 37 12.4,3.6; 38 12.4,4.4; 39 12.4,5.2; 40 12.4,6; 65 -12.4,6; 66 -12.4,5.2; 67 -12.4,4.4; 68 -12.4,3.6; 69 -12.4,2.8; 70 -12.4,2; 71 -12.4,1.2; 72 -12.4,0.38; 73 -12.4,-0.4; 74 -12.4,-1.2; 75 -12.4,-2; 76 -12.4,-2.8; 77 -12.4,-3.6; 78 -12.4,-4.4; 79 -12.4,-5.2; 80 -12.4,-6

## Footprint TQFP80-14X14 (pad centres in mm)
TQFP80 14mm x 14mm 0.5mm pin pitch
smd 0.35 x 1.8: 1 -4.75,7; 2 -4.25,7; 3 -3.75,7; 4 -3.25,7; 5 -2.75,7; 6 -2.25,7; 7 -1.75,7; 8 -1.25,7; 9 -0.75,7; 10 -0.25,7; 11 0.25,7; 12 0.75,7; 13 1.25,7; 14 1.75,7; 15 2.25,7; 16 2.75,7; 17 3.25,7; 18 3.75,7; 19 4.25,7; 20 4.75,7; 41 4.75,-7; 42 4.25,-7; 43 3.75,-7; 44 3.25,-7; 45 2.75,-7; 46 2.25,-7; 47 1.75,-7; 48 1.25,-7; 49 0.75,-7; 50 0.25,-7; 51 -0.25,-7; 52 -0.75,-7; 53 -1.25,-7; 54 -1.75,-7; 55 -2.25,-7; 56 -2.75,-7; 57 -3.25,-7; 58 -3.75,-7; 59 -4.25,-7; 60 -4.75,-7
smd 1.8 x 0.35: 21 7,4.75; 22 7,4.25; 23 7,3.75; 24 7,3.25; 25 7,2.75; 26 7,2.25; 27 7,1.75; 28 7,1.25; 29 7,0.75; 30 7,0.25; 31 7,-0.25; 32 7,-0.75; 33 7,-1.25; 34 7,-1.75; 35 7,-2.25; 36 7,-2.75; 37 7,-3.25; 38 7,-3.75; 39 7,-4.25; 40 7,-4.75; 61 -7,-4.75; 62 -7,-4.25; 63 -7,-3.75; 64 -7,-3.25; 65 -7,-2.75; 66 -7,-2.25; 67 -7,-1.75; 68 -7,-1.25; 69 -7,-0.75; 70 -7,-0.25; 71 -7,0.25; 72 -7,0.75; 73 -7,1.25; 74 -7,1.75; 75 -7,2.25; 76 -7,2.75; 77 -7,3.25; 78 -7,3.75; 79 -7,4.25; 80 -7,4.75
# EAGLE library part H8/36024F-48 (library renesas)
H8/36024 in 48pin TQFPs

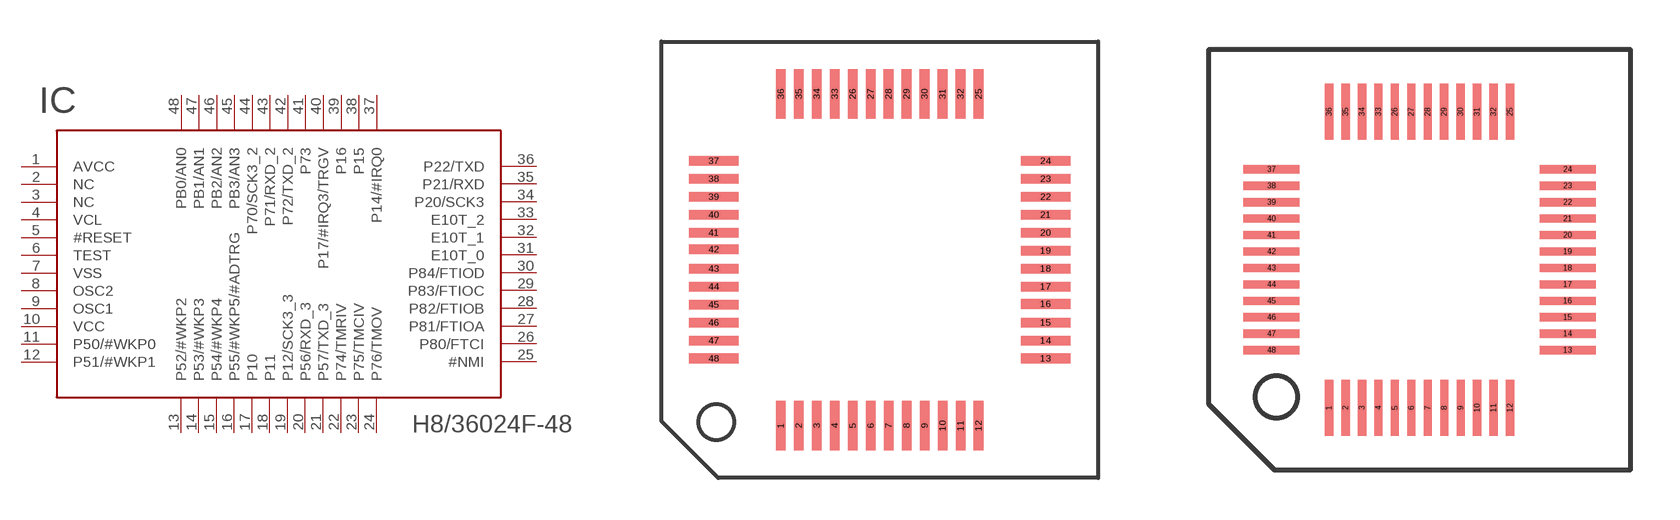
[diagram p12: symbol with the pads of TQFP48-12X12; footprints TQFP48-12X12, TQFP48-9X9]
Designator prefix IC

## H8/36024F-48X  [TQFP48-12X12]
1  AVCC  pwr
2  NC  nc
3  NC  nc
4  VCL  pwr
5  #RESET  in
6  TEST  in
7  VSS  pwr
8  OSC2  pas
9  OSC1  in
10  VCC  pwr
11  P50/#WKP0
12  P51/#WKP1
13  P52/#WKP2
14  P53/#WKP3
15  P54/#WKP4
16  P55/#WKP5/#ADTRG
17  P10
18  P11
19  P12/SCK3_3
20  P56/RXD_3
21  P57/TXD_3
22  P74/TMRIV
23  P75/TMCIV
24  P76/TMOV
25  #NMI  in
26  P80/FTCI
27  P81/FTIOA
28  P82/FTIOB
29  P83/FTIOC
30  P84/FTIOD
31  E10T_0
32  E10T_1
33  E10T_2
34  P20/SCK3
35  P21/RXD
36  P22/TXD
37  P14/#IRQ0
38  P15
39  P16
40  P17/#IRQ3/TRGV
41  P73
42  P72/TXD_2
43  P71/RXD_2
44  P70/SCK3_2
45  PB3/AN3
46  PB2/AN2
47  PB1/AN1
48  PB0/AN0

## H8/36024F-48Y  [TQFP48-9X9]
Pads as for TQFP48-12X12

## H8/36024F-48T  [QNP48-7X7]
Pads as for TQFP48-12X12

## Footprint TQFP48-12X12 (pad centres in mm)
TQFP48 12x12mm 0.65mm pitch 0.35mm pad width
smd 0.35 x 1.8: 1 -3.575,-6; 2 -2.925,-6; 3 -2.275,-6; 4 -1.625,-6; 5 -0.975,-6; 6 -0.325,-6; 7 0.325,-6; 8 0.975,-6; 9 1.625,-6; 10 2.275,-6; 11 2.925,-6; 12 3.575,-6; 25 3.575,6; 26 -0.978,6; 27 -0.328,6; 28 0.322,6; 29 0.972,6; 30 1.622,6; 31 2.272,6; 32 2.922,6; 33 -1.625,6; 34 -2.275,6; 35 -2.925,6; 36 -3.575,6
smd 1.8 x 0.35: 13 6,-3.575; 14 6,-2.925; 15 6,-2.275; 16 6,-1.6; 17 6,-0.975; 18 6,-0.325; 19 6,0.325; 20 6,0.975; 21 6,1.625; 22 6,2.275; 23 6,2.925; 24 6,3.575; 37 -6,3.575; 38 -6,2.925; 39 -6,2.275; 40 -6,1.625; 41 -6,0.975; 42 -6,0.375; 43 -6,-0.325; 44 -6,-0.975; 45 -6,-1.625; 46 -6,-2.275; 47 -6,-2.925; 48 -6,-3.575

## Footprint TQFP48-9X9 (pad centres in mm)
TQFP48 9x9mm 0.5mm pitch 0.25mm pad
smd 0.25 x 1.7: 1 -2.75,-4.5; 2 -2.25,-4.5; 3 -1.75,-4.5; 4 -1.25,-4.5; 5 -0.75,-4.5; 6 -0.25,-4.5; 7 0.25,-4.5; 8 0.75,-4.5; 9 1.25,-4.5; 10 1.75,-4.5; 11 2.25,-4.5; 12 2.75,-4.5; 25 2.75,4.5; 26 -0.753,4.5; 27 -0.253,4.5; 28 0.247,4.5; 29 0.747,4.5; 30 1.247,4.5; 31 1.747,4.5; 32 2.247,4.5; 33 -1.25,4.5; 34 -1.75,4.5; 35 -2.25,4.5; 36 -2.75,4.5
smd 1.7 x 0.25: 13 4.5,-2.75; 14 4.5,-2.25; 15 4.5,-1.75; 16 4.5,-1.25; 17 4.5,-0.75; 18 4.5,-0.25; 19 4.5,0.25; 20 4.5,0.75; 21 4.5,1.25; 22 4.5,1.75; 23 4.5,2.25; 24 4.5,2.75; 37 -4.5,2.75; 38 -4.5,2.25; 39 -4.5,1.75; 40 -4.5,1.25; 41 -4.5,0.75; 42 -4.5,0.25; 43 -4.5,-0.25; 44 -4.5,-0.75; 45 -4.5,-1.25; 46 -4.5,-1.75; 47 -4.5,-2.25; 48 -4.5,-2.75

## Footprint QNP48-7X7 (pad centres in mm)
QNP 48 pin 7 x 7 mm body on 0.5mm pitch
smd 0.25 x 1: 1 -2.72,-3.5; 2 -2.22,-3.5; 3 -1.72,-3.5; 4 -1.22,-3.5; 5 -0.72,-3.5; 6 -0.22,-3.5; 7 0.28,-3.5; 8 0.78,-3.5; 9 1.28,-3.5; 10 1.78,-3.5; 11 2.28,-3.5; 12 2.78,-3.5; 25 2.78,3.5; 26 -0.723,3.5; 27 -0.223,3.5; 28 0.277,3.5; 29 0.777,3.5; 30 1.277,3.5; 31 1.777,3.5; 32 2.277,3.5; 33 -1.22,3.5; 34 -1.72,3.5; 35 -2.22,3.5; 36 -2.72,3.5
smd 1 x 0.25: 13 3.53,-2.75; 14 3.53,-2.25; 15 3.53,-1.75; 16 3.53,-1.25; 17 3.53,-0.75; 18 3.53,-0.25; 19 3.53,0.25; 20 3.53,0.75; 21 3.53,1.25; 22 3.53,1.75; 23 3.53,2.25; 24 3.53,2.75; 37 -3.47,2.75; 38 -3.47,2.25; 39 -3.47,1.75; 40 -3.47,1.25; 41 -3.47,0.75; 42 -3.47,0.25; 43 -3.47,-0.25; 44 -3.47,-0.75; 45 -3.47,-1.25; 46 -3.47,-1.75; 47 -3.47,-2.25; 48 -3.47,-2.75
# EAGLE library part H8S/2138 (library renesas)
H8S/2138 80 pin QFP

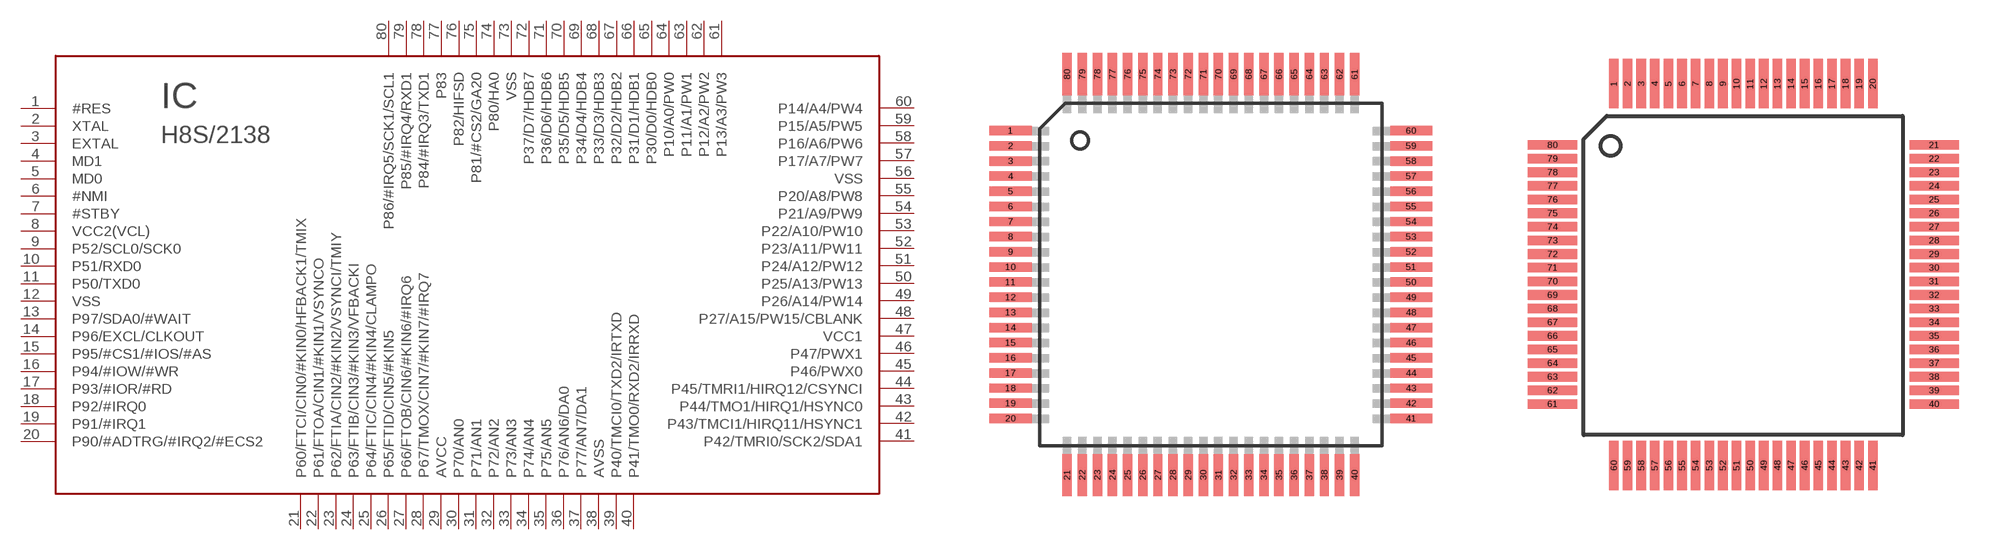
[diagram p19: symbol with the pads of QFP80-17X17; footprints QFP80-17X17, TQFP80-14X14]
Designator prefix IC

## H8S/2138FA  [QFP80-17X17]
1  #RES  in
2  XTAL  pas
3  EXTAL  in
4  MD1  in
5  MD0  in
6  #NMI  in
7  #STBY  in
8  VCC2(VCL)  pwr
9  P52/SCL0/SCK0
10  P51/RXD0
11  P50/TXD0
12  VSS  pwr
13  P97/SDA0/#WAIT
14  P96/EXCL/CLKOUT
15  P95/#CS1/#IOS/#AS
16  P94/#IOW/#WR
17  P93/#IOR/#RD
18  P92/#IRQ0
19  P91/#IRQ1
20  P90/#ADTRG/#IRQ2/#ECS2
21  P60/FTCI/CIN0/#KIN0/HFBACK1/TMIX
22  P61/FTOA/CIN1/#KIN1/VSYNCO
23  P62/FTIA/CIN2/#KIN2/VSYNCI/TMIY
24  P63/FTIB/CIN3/#KIN3/VFBACKI
25  P64/FTIC/CIN4/#KIN4/CLAMPO
26  P65/FTID/CIN5/#KIN5
27  P66/FTOB/CIN6/#KIN6/#IRQ6
28  P67/TMOX/CIN7/#KIN7/#IRQ7
29  AVCC  pwr
30  P70/AN0
31  P71/AN1
32  P72/AN2
33  P73/AN3
34  P74/AN4
35  P75/AN5
36  P76/AN6/DA0
37  P77/AN7/DA1
38  AVSS  pwr
39  P40/TMCI0/TXD2/IRTXD
40  P41/TMO0/RXD2/IRRXD
41  P42/TMRI0/SCK2/SDA1
42  P43/TMCI1/HIRQ11/HSYNC1
43  P44/TMO1/HIRQ1/HSYNC0
44  P45/TMRI1/HIRQ12/CSYNCI
45  P46/PWX0
46  P47/PWX1
47  VCC1  pwr
48  P27/A15/PW15/CBLANK
49  P26/A14/PW14
50  P25/A13/PW13
51  P24/A12/PW12
52  P23/A11/PW11
53  P22/A10/PW10
54  P21/A9/PW9
55  P20/A8/PW8
56  VSS  pwr
57  P17/A7/PW7
58  P16/A6/PW6
59  P15/A5/PW5
60  P14/A4/PW4
61  P13/A3/PW3
62  P12/A2/PW2
63  P11/A1/PW1
64  P10/A0/PW0
65  P30/D0/HDB0
66  P31/D1/HDB1
67  P32/D2/HDB2
68  P33/D3/HDB3
69  P34/D4/HDB4
70  P35/D5/HDB5
71  P36/D6/HDB6
72  P37/D7/HDB7
73  VSS  pwr
74  P80/HA0
75  P81/#CS2/GA20
76  P82/HIFSD
77  P83
78  P84/#IRQ3/TXD1
79  P85/#IRQ4/RXD1
80  P86/#IRQ5/SCK1/SCL1

## H8S/2138TF  [TQFP80-14X14]
Pads as for QFP80-17X17

## Footprint QFP80-17X17 (pad centres in mm)
QFP80 17mm x 17mm 0.65mm pin pitch
smd 1.8 x 0.4: 1 -8.6,6.175; 2 -8.6,5.525; 3 -8.6,4.875; 4 -8.6,4.225; 5 -8.6,3.575; 6 -8.6,2.925; 7 -8.6,2.275; 8 -8.6,1.625; 9 -8.6,0.975; 10 -8.6,0.325; 11 -8.6,-0.325; 12 -8.6,-0.975; 13 -8.6,-1.625; 14 -8.6,-2.275; 15 -8.6,-2.925; 16 -8.6,-3.575; 17 -8.6,-4.225; 18 -8.6,-4.875; 19 -8.6,-5.525; 20 -8.6,-6.175; 41 8.6,-6.175; 42 8.6,-5.525; 43 8.6,-4.875; 44 8.6,-4.225; 45 8.6,-3.575; 46 8.6,-2.925; 47 8.6,-2.275; 48 8.6,-1.625; 49 8.6,-0.975; 50 8.6,-0.325; 51 8.6,0.325; 52 8.6,0.975; 53 8.6,1.625; 54 8.6,2.275; 55 8.6,2.925; 56 8.6,3.575; 57 8.6,4.225; 58 8.6,4.875; 59 8.6,5.525; 60 8.6,6.175
smd 0.4 x 1.8: 21 -6.175,-8.6; 22 -5.525,-8.6; 23 -4.875,-8.6; 24 -4.225,-8.6; 25 -3.575,-8.6; 26 -2.925,-8.6; 27 -2.275,-8.6; 28 -1.625,-8.6; 29 -0.975,-8.6; 30 -0.325,-8.6; 31 0.325,-8.6; 32 0.975,-8.6; 33 1.625,-8.6; 34 2.275,-8.6; 35 2.925,-8.6; 36 3.575,-8.6; 37 4.225,-8.6; 38 4.875,-8.6; 39 5.525,-8.6; 40 6.175,-8.6; 61 6.175,8.6; 62 5.525,8.6; 63 4.875,8.6; 64 4.225,8.6; 65 3.575,8.6; 66 2.925,8.6; 67 2.275,8.6; 68 1.625,8.6; 69 0.975,8.6; 70 0.325,8.6; 71 -0.325,8.6; 72 -0.975,8.6; 73 -1.625,8.6; 74 -2.275,8.6; 75 -2.925,8.6; 76 -3.575,8.6; 77 -4.225,8.6; 78 -4.875,8.6; 79 -5.525,8.6; 80 -6.175,8.6

## Footprint TQFP80-14X14 (pad centres in mm)
TQFP80 14mm x 14mm 0.5mm pin pitch
smd 0.35 x 1.8: 1 -4.75,7; 2 -4.25,7; 3 -3.75,7; 4 -3.25,7; 5 -2.75,7; 6 -2.25,7; 7 -1.75,7; 8 -1.25,7; 9 -0.75,7; 10 -0.25,7; 11 0.25,7; 12 0.75,7; 13 1.25,7; 14 1.75,7; 15 2.25,7; 16 2.75,7; 17 3.25,7; 18 3.75,7; 19 4.25,7; 20 4.75,7; 41 4.75,-7; 42 4.25,-7; 43 3.75,-7; 44 3.25,-7; 45 2.75,-7; 46 2.25,-7; 47 1.75,-7; 48 1.25,-7; 49 0.75,-7; 50 0.25,-7; 51 -0.25,-7; 52 -0.75,-7; 53 -1.25,-7; 54 -1.75,-7; 55 -2.25,-7; 56 -2.75,-7; 57 -3.25,-7; 58 -3.75,-7; 59 -4.25,-7; 60 -4.75,-7
smd 1.8 x 0.35: 21 7,4.75; 22 7,4.25; 23 7,3.75; 24 7,3.25; 25 7,2.75; 26 7,2.25; 27 7,1.75; 28 7,1.25; 29 7,0.75; 30 7,0.25; 31 7,-0.25; 32 7,-0.75; 33 7,-1.25; 34 7,-1.75; 35 7,-2.25; 36 7,-2.75; 37 7,-3.25; 38 7,-3.75; 39 7,-4.25; 40 7,-4.75; 61 -7,-4.75; 62 -7,-4.25; 63 -7,-3.75; 64 -7,-3.25; 65 -7,-2.75; 66 -7,-2.25; 67 -7,-1.75; 68 -7,-1.25; 69 -7,-0.75; 70 -7,-0.25; 71 -7,0.25; 72 -7,0.75; 73 -7,1.25; 74 -7,1.75; 75 -7,2.25; 76 -7,2.75; 77 -7,3.25; 78 -7,3.75; 79 -7,4.25; 80 -7,4.75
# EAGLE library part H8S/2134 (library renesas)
H8S/2134 in 80 pin TQFP

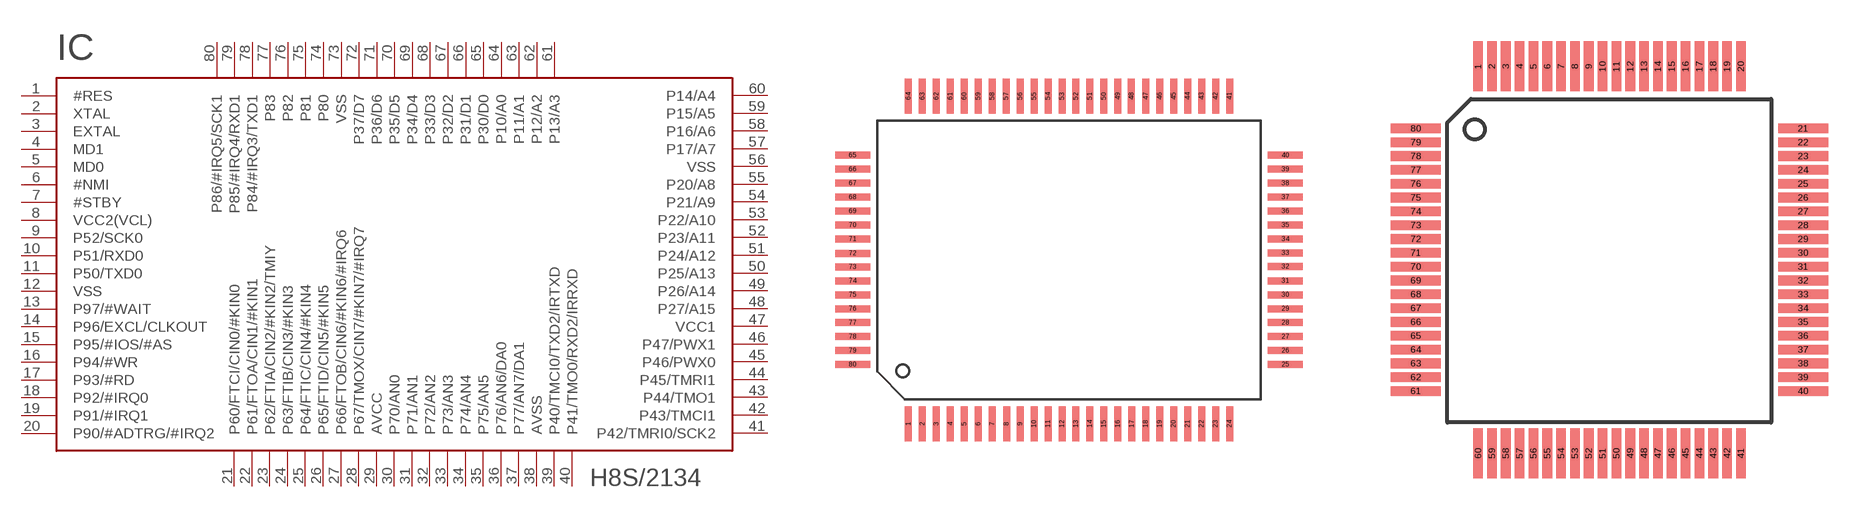
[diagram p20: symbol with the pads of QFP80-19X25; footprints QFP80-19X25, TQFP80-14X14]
Designator prefix IC

## H8S/2134FA  [QFP80-19X25]
1  #RES  in
2  XTAL  pas
3  EXTAL  in
4  MD1  in
5  MD0  in
6  #NMI  in
7  #STBY  in
8  VCC2(VCL)  pwr
9  P52/SCK0
10  P51/RXD0
11  P50/TXD0
12  VSS  pwr
13  P97/#WAIT
14  P96/EXCL/CLKOUT
15  P95/#IOS/#AS
16  P94/#WR
17  P93/#RD
18  P92/#IRQ0
19  P91/#IRQ1
20  P90/#ADTRG/#IRQ2
21  P60/FTCI/CIN0/#KIN0
22  P61/FTOA/CIN1/#KIN1
23  P62/FTIA/CIN2/#KIN2/TMIY
24  P63/FTIB/CIN3/#KIN3
25  P64/FTIC/CIN4/#KIN4
26  P65/FTID/CIN5/#KIN5
27  P66/FTOB/CIN6/#KIN6/#IRQ6
28  P67/TMOX/CIN7/#KIN7/#IRQ7
29  AVCC  pwr
30  P70/AN0
31  P71/AN1
32  P72/AN2
33  P73/AN3
34  P74/AN4
35  P75/AN5
36  P76/AN6/DA0
37  P77/AN7/DA1
38  AVSS  pwr
39  P40/TMCI0/TXD2/IRTXD
40  P41/TMO0/RXD2/IRRXD
41  P42/TMRI0/SCK2
42  P43/TMCI1
43  P44/TMO1
44  P45/TMRI1
45  P46/PWX0
46  P47/PWX1
47  VCC1  pwr
48  P27/A15
49  P26/A14
50  P25/A13
51  P24/A12
52  P23/A11
53  P22/A10
54  P21/A9
55  P20/A8
56  VSS  pwr
57  P17/A7
58  P16/A6
59  P15/A5
60  P14/A4
61  P13/A3
62  P12/A2
63  P11/A1
64  P10/A0
65  P30/D0
66  P31/D1
67  P32/D2
68  P33/D3
69  P34/D4
70  P35/D5
71  P36/D6
72  P37/D7
73  VSS  pwr
74  P80
75  P81
76  P82
77  P83
78  P84/#IRQ3/TXD1
79  P85/#IRQ4/RXD1
80  P86/#IRQ5/SCK1

## H8S/2134TF  [TQFP80-14X14]
Pads as for QFP80-19X25

## Footprint QFP80-19X25 (pad centres in mm)
QFP80 19mm x 25mm 0.8mm pin pitch
smd 0.4 x 2: 1 -9.2,-9.4; 2 -8.4,-9.4; 3 -7.6,-9.4; 4 -6.8,-9.4; 5 -6,-9.4; 6 -5.2,-9.4; 7 -4.4,-9.4; 8 -3.58,-9.4; 9 -2.8,-9.4; 10 -2,-9.4; 11 -1.2,-9.4; 12 -0.4,-9.4; 13 0.4,-9.4; 14 1.2,-9.4; 15 2,-9.4; 16 2.8,-9.4; 17 3.6,-9.4; 18 4.4,-9.4; 19 5.2,-9.4; 20 6,-9.4; 21 6.8,-9.4; 22 7.6,-9.4; 23 8.4,-9.4; 24 9.2,-9.4; 41 9.2,9.4; 42 8.4,9.4; 43 7.6,9.4; 44 6.8,9.4; 45 6,9.4; 46 5.2,9.4; 47 4.4,9.4; 48 3.58,9.4; 49 2.8,9.4; 50 2,9.4; 51 1.2,9.4; 52 0.4,9.4; 53 -0.4,9.4; 54 -1.2,9.4; 55 -2,9.4; 56 -2.8,9.4; 57 -3.6,9.4; 58 -4.4,9.4; 59 -5.2,9.4; 60 -6,9.4; 61 -6.8,9.4; 62 -7.6,9.4; 63 -8.4,9.4; 64 -9.2,9.4
smd 2 x 0.4: 25 12.4,-6; 26 12.4,-5.2; 27 12.4,-4.4; 28 12.4,-3.6; 29 12.4,-2.8; 30 12.4,-2; 31 12.4,-1.2; 32 12.4,-0.38; 33 12.4,0.4; 34 12.4,1.2; 35 12.4,2; 36 12.4,2.8; 37 12.4,3.6; 38 12.4,4.4; 39 12.4,5.2; 40 12.4,6; 65 -12.4,6; 66 -12.4,5.2; 67 -12.4,4.4; 68 -12.4,3.6; 69 -12.4,2.8; 70 -12.4,2; 71 -12.4,1.2; 72 -12.4,0.38; 73 -12.4,-0.4; 74 -12.4,-1.2; 75 -12.4,-2; 76 -12.4,-2.8; 77 -12.4,-3.6; 78 -12.4,-4.4; 79 -12.4,-5.2; 80 -12.4,-6

## Footprint TQFP80-14X14 (pad centres in mm)
TQFP80 14mm x 14mm 0.5mm pin pitch
smd 0.35 x 1.8: 1 -4.75,7; 2 -4.25,7; 3 -3.75,7; 4 -3.25,7; 5 -2.75,7; 6 -2.25,7; 7 -1.75,7; 8 -1.25,7; 9 -0.75,7; 10 -0.25,7; 11 0.25,7; 12 0.75,7; 13 1.25,7; 14 1.75,7; 15 2.25,7; 16 2.75,7; 17 3.25,7; 18 3.75,7; 19 4.25,7; 20 4.75,7; 41 4.75,-7; 42 4.25,-7; 43 3.75,-7; 44 3.25,-7; 45 2.75,-7; 46 2.25,-7; 47 1.75,-7; 48 1.25,-7; 49 0.75,-7; 50 0.25,-7; 51 -0.25,-7; 52 -0.75,-7; 53 -1.25,-7; 54 -1.75,-7; 55 -2.25,-7; 56 -2.75,-7; 57 -3.25,-7; 58 -3.75,-7; 59 -4.25,-7; 60 -4.75,-7
smd 1.8 x 0.35: 21 7,4.75; 22 7,4.25; 23 7,3.75; 24 7,3.25; 25 7,2.75; 26 7,2.25; 27 7,1.75; 28 7,1.25; 29 7,0.75; 30 7,0.25; 31 7,-0.25; 32 7,-0.75; 33 7,-1.25; 34 7,-1.75; 35 7,-2.25; 36 7,-2.75; 37 7,-3.25; 38 7,-3.75; 39 7,-4.25; 40 7,-4.75; 61 -7,-4.75; 62 -7,-4.25; 63 -7,-3.75; 64 -7,-3.25; 65 -7,-2.75; 66 -7,-2.25; 67 -7,-1.75; 68 -7,-1.25; 69 -7,-0.75; 70 -7,-0.25; 71 -7,0.25; 72 -7,0.75; 73 -7,1.25; 74 -7,1.75; 75 -7,2.25; 76 -7,2.75; 77 -7,3.25; 78 -7,3.75; 79 -7,4.25; 80 -7,4.75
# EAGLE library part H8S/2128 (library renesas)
H8S/2128FA 64 pin QFP and DIP

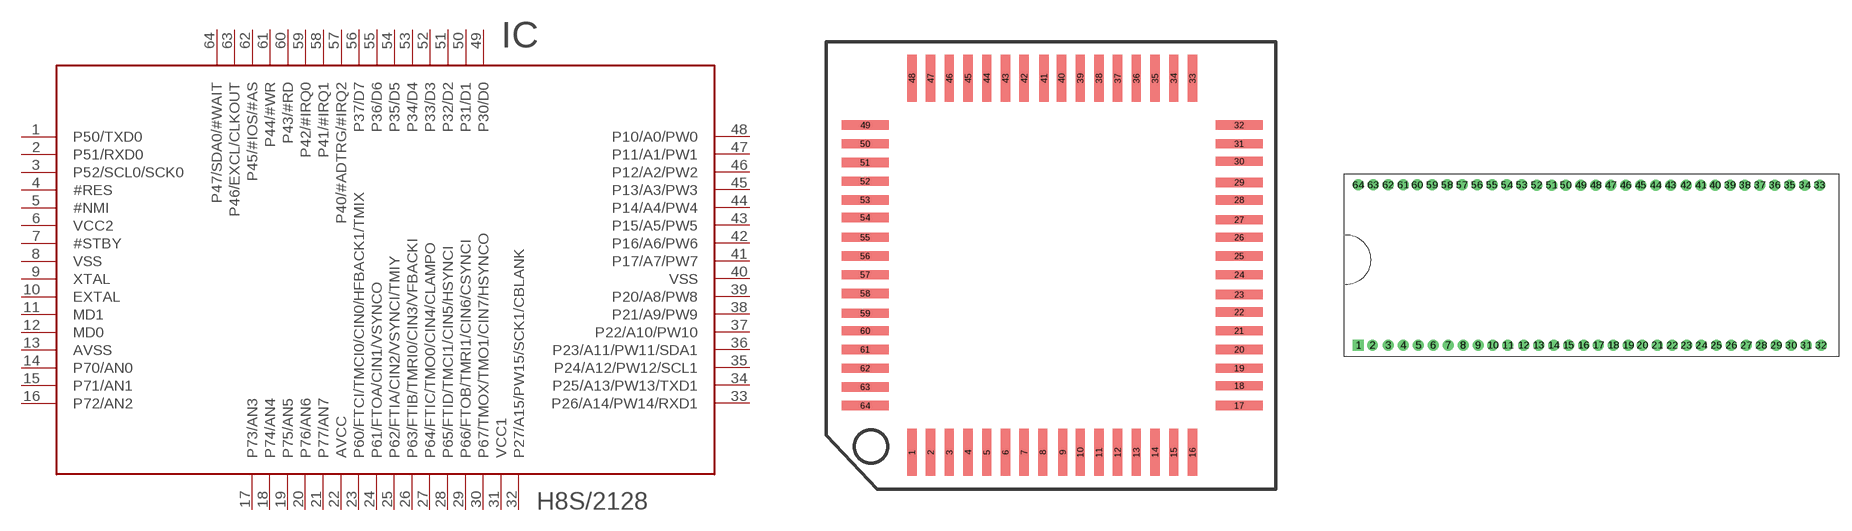
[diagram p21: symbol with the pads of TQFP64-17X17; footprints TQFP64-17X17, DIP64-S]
Designator prefix IC

## H8S/2128FA  [TQFP64-17X17]
1  P50/TXD0
2  P51/RXD0
3  P52/SCL0/SCK0
4  #RES  in
5  #NMI  in
6  VCC2  pwr
7  #STBY  in
8  VSS  pwr
9  XTAL  pas
10  EXTAL  in
11  MD1  in
12  MD0  in
13  AVSS  pwr
14  P70/AN0
15  P71/AN1
16  P72/AN2
17  P73/AN3
18  P74/AN4
19  P75/AN5
20  P76/AN6
21  P77/AN7
22  AVCC  pwr
23  P60/FTCI/TMCI0/CIN0/HFBACK1/TMIX
24  P61/FTOA/CIN1/VSYNCO
25  P62/FTIA/CIN2/VSYNCI/TMIY
26  P63/FTIB/TMRI0/CIN3/VFBACKI
27  P64/FTIC/TMO0/CIN4/CLAMPO
28  P65/FTID/TMCI1/CIN5/HSYNCI
29  P66/FTOB/TMRI1/CIN6/CSYNCI
30  P67/TMOX/TMO1/CIN7/HSYNCO
31  VCC1  pwr
32  P27/A15/PW15/SCK1/CBLANK
33  P26/A14/PW14/RXD1
34  P25/A13/PW13/TXD1
35  P24/A12/PW12/SCL1
36  P23/A11/PW11/SDA1
37  P22/A10/PW10
38  P21/A9/PW9
39  P20/A8/PW8
40  VSS  pwr
41  P17/A7/PW7
42  P16/A6/PW6
43  P15/A5/PW5
44  P14/A4/PW4
45  P13/A3/PW3
46  P12/A2/PW2
47  P11/A1/PW1
48  P10/A0/PW0
49  P30/D0
50  P31/D1
51  P32/D2
52  P33/D3
53  P34/D4
54  P35/D5
55  P36/D6
56  P37/D7
57  P40/#ADTRG/#IRQ2
58  P41/#IRQ1
59  P42/#IRQ0
60  P43/#RD
61  P44/#WR
62  P45/#IOS/#AS
63  P46/EXCL/CLKOUT
64  P47/SDA0/#WAIT

## H8S/2128PS  [DIP64-S]
1  P40/#ADTRG/#IRQ2
2  P41/#IRQ1
3  P42/#IRQ0
4  P43/#RD
5  P44/#WR
6  P45/#IOS/#AS
7  P46/EXCL/CLKOUT
8  P47/SDA0/#WAIT
9  P50/TXD0
10  P51/RXD0
11  P52/SCL0/SCK0
12  #RES  in
13  #NMI  in
14  VCC2  pwr
15  #STBY  in
16  VSS  pwr
17  XTAL  pas
18  EXTAL  in
19  MD1  in
20  MD0  in
21  AVSS  pwr
22  P70/AN0
23  P71/AN1
24  P72/AN2
25  P73/AN3
26  P74/AN4
27  P75/AN5
28  P76/AN6
29  P77/AN7
30  AVCC  pwr
31  P60/FTCI/TMCI0/CIN0/HFBACK1/TMIX
32  P61/FTOA/CIN1/VSYNCO
33  P62/FTIA/CIN2/VSYNCI/TMIY
34  P63/FTIB/TMRI0/CIN3/VFBACKI
35  P64/FTIC/TMO0/CIN4/CLAMPO
36  P65/FTID/TMCI1/CIN5/HSYNCI
37  P66/FTOB/TMRI1/CIN6/CSYNCI
38  P67/TMOX/TMO1/CIN7/HSYNCO
39  VCC1  pwr
40  P27/A15/PW15/SCK1/CBLANK
41  P26/A14/PW14/RXD1
42  P25/A13/PW13/TXD1
43  P24/A12/PW12/SCL1
44  P23/A11/PW11/SDA1
45  P22/A10/PW10
46  P21/A9/PW9
47  P20/A8/PW8
48  VSS  pwr
49  P17/A7/PW7
50  P16/A6/PW6
51  P15/A5/PW5
52  P14/A4/PW4
53  P13/A3/PW3
54  P12/A2/PW2
55  P11/A1/PW1
56  P10/A0/PW0
57  P30/D0
58  P31/D1
59  P32/D2
60  P33/D3
61  P34/D4
62  P35/D5
63  P36/D6
64  P37/D7

## Footprint TQFP64-17X17 (pad centres in mm)
TQFP64 17x17mm 0.8mm pitch 0.4mm pad width
smd 0.4 x 2: 1 -6,-8; 2 -5.2,-8; 3 -4.4,-8; 4 -3.6,-8; 5 -2.8,-8; 6 -2,-8; 7 -1.2,-8; 8 -0.4,-8; 9 0.45,-8; 10 1.2,-8; 11 2,-8; 12 2.8,-8; 13 3.6,-8; 14 4.4,-8; 15 5.2,-8; 16 6,-8; 33 6,8; 34 5.2,8; 35 4.4,8; 36 3.6,8; 37 2.8,8; 38 2,8; 39 1.2,8; 40 0.4,8; 41 -0.35,8; 42 -1.2,8; 43 -2,8; 44 -2.8,8; 45 -3.6,8; 46 -4.4,8; 47 -5.2,8; 48 -6,8
smd 2 x 0.4: 17 8,-6; 18 8,-5.15; 19 8,-4.4; 20 8,-3.6; 21 8,-2.8; 22 8,-2; 23 8,-1.25; 24 8,-0.4; 25 8,0.4; 26 8,1.2; 27 8,1.95; 28 8,2.8; 29 8,3.55; 30 8,4.45; 31 8,5.2; 32 8,6; 49 -8,6; 50 -8,5.2; 51 -8,4.4; 52 -8,3.6; 53 -8,2.8; 54 -8,2.05; 55 -8,1.2; 56 -8,0.4; 57 -8,-0.4; 58 -8,-1.2; 59 -8,-2.05; 60 -8,-2.8; 61 -8,-3.6; 62 -8,-4.4; 63 -8,-5.2; 64 -8,-6

## Footprint DIP64-S (pad centres in mm)
64pin Dip Shrink 1.78mm pitch pins, 19.05mm pitch rows
drill 0.8 pad 1.2 square: 1 -24.3,-9.07
drill 0.8 pad 1.2 round: 2 -22.62,-9.07; 3 -20.74,-9.07; 4 -18.96,-9.07; 5 -17.18,-9.07; 6 -15.4,-9.07; 7 -13.62,-9.07; 8 -11.84,-9.07; 9 -10.06,-9.07; 10 -8.28,-9.07; 11 -6.5,-9.07; 12 -4.62,-9.07; 13 -2.84,-9.07; 14 -1.06,-9.07; 15 0.72,-9.07; 16 2.5,-9.07; 17 4.28,-9.07; 18 6.06,-9.07; 19 7.84,-9.07; 20 9.52,-9.07; 21 11.3,-9.07; 22 13.08,-9.09; 23 14.76,-9.09; 24 16.54,-9.09; 25 18.33,-9.09; 26 20.11,-9.09; 27 21.89,-9.09; 28 23.67,-9.09; 29 25.45,-9.09; 30 27.23,-9.09; 31 29.01,-9.09; 32 30.79,-9.09; 33 30.62,9.99; 34 28.84,9.99; 35 27.06,9.99; 36 25.28,9.99; 37 23.5,9.99; 38 21.72,9.99; 39 19.94,9.99; 40 18.16,9.99; 41 16.48,9.99; 42 14.7,9.99; 43 12.87,9.99; 44 11.09,9.99; 45 9.31,9.99; 46 7.53,9.99; 47 5.75,9.99; 48 3.97,9.99; 49 2.19,9.99; 50 0.41,9.99; 51 -1.27,9.99; 52 -3.05,9.99; 53 -4.83,10; 54 -6.61,10; 55 -8.39,10; 56 -10.17,10; 57 -11.95,10; 58 -13.73,10; 59 -15.51,10; 60 -17.29,10; 61 -18.97,10; 62 -20.75,10; 63 -22.53,10; 64 -24.31,10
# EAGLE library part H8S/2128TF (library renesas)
H8S/2128 in 80 pin TQFP

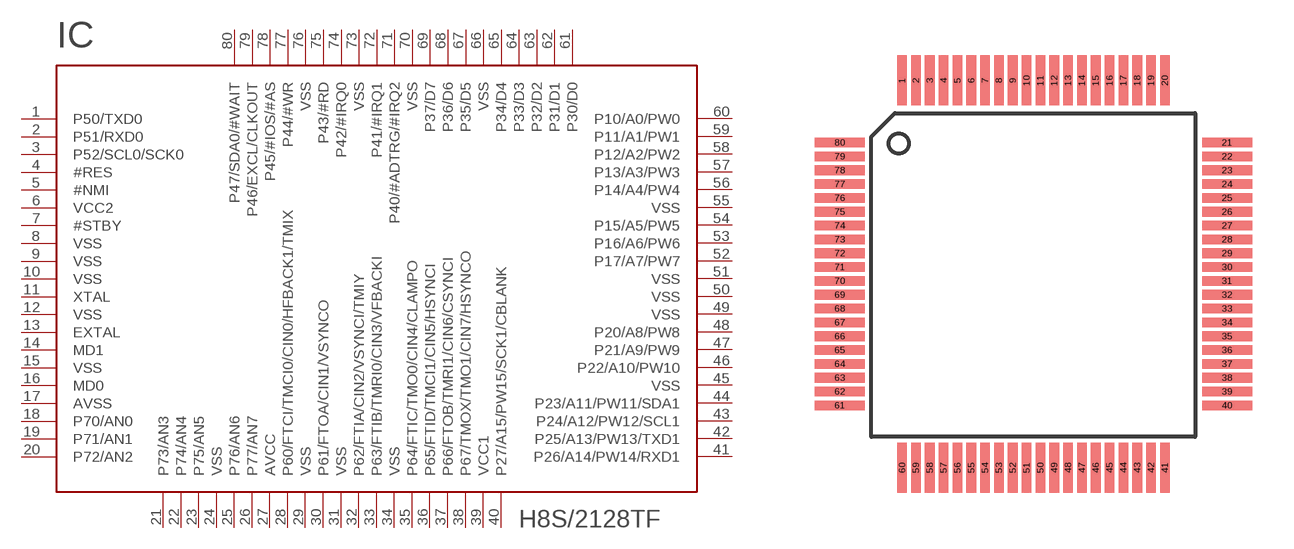
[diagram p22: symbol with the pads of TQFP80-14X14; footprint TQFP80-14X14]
Designator prefix IC

## H8S/2128TF  [TQFP80-14X14]
1  P50/TXD0
2  P51/RXD0
3  P52/SCL0/SCK0
4  #RES  in
5  #NMI  in
6  VCC2  pwr
7  #STBY  in
8  VSS  pwr
9  VSS  pwr
10  VSS  pwr
11  XTAL  pas
12  VSS  pwr
13  EXTAL  in
14  MD1  in
15  VSS  pwr
16  MD0  in
17  AVSS  pwr
18  P70/AN0
19  P71/AN1
20  P72/AN2
21  P73/AN3
22  P74/AN4
23  P75/AN5
24  VSS  pwr
25  P76/AN6
26  P77/AN7
27  AVCC  pwr
28  P60/FTCI/TMCI0/CIN0/HFBACK1/TMIX
29  VSS  pwr
30  P61/FTOA/CIN1/VSYNCO
31  VSS  pwr
32  P62/FTIA/CIN2/VSYNCI/TMIY
33  P63/FTIB/TMRI0/CIN3/VFBACKI
34  VSS  pwr
35  P64/FTIC/TMO0/CIN4/CLAMPO
36  P65/FTID/TMCI1/CIN5/HSYNCI
37  P66/FTOB/TMRI1/CIN6/CSYNCI
38  P67/TMOX/TMO1/CIN7/HSYNCO
39  VCC1  pwr
40  P27/A15/PW15/SCK1/CBLANK
41  P26/A14/PW14/RXD1
42  P25/A13/PW13/TXD1
43  P24/A12/PW12/SCL1
44  P23/A11/PW11/SDA1
45  VSS  pwr
46  P22/A10/PW10
47  P21/A9/PW9
48  P20/A8/PW8
49  VSS  pwr
50  VSS  pwr
51  VSS  pwr
52  P17/A7/PW7
53  P16/A6/PW6
54  P15/A5/PW5
55  VSS  pwr
56  P14/A4/PW4
57  P13/A3/PW3
58  P12/A2/PW2
59  P11/A1/PW1
60  P10/A0/PW0
61  P30/D0
62  P31/D1
63  P32/D2
64  P33/D3
65  P34/D4
66  VSS  pwr
67  P35/D5
68  P36/D6
69  P37/D7
70  VSS  pwr
71  P40/#ADTRG/#IRQ2
72  P41/#IRQ1
73  VSS  pwr
74  P42/#IRQ0
75  P43/#RD
76  VSS  pwr
77  P44/#WR
78  P45/#IOS/#AS
79  P46/EXCL/CLKOUT
80  P47/SDA0/#WAIT

## Footprint TQFP80-14X14 (pad centres in mm)
TQFP80 14mm x 14mm 0.5mm pin pitch
smd 0.35 x 1.8: 1 -4.75,7; 2 -4.25,7; 3 -3.75,7; 4 -3.25,7; 5 -2.75,7; 6 -2.25,7; 7 -1.75,7; 8 -1.25,7; 9 -0.75,7; 10 -0.25,7; 11 0.25,7; 12 0.75,7; 13 1.25,7; 14 1.75,7; 15 2.25,7; 16 2.75,7; 17 3.25,7; 18 3.75,7; 19 4.25,7; 20 4.75,7; 41 4.75,-7; 42 4.25,-7; 43 3.75,-7; 44 3.25,-7; 45 2.75,-7; 46 2.25,-7; 47 1.75,-7; 48 1.25,-7; 49 0.75,-7; 50 0.25,-7; 51 -0.25,-7; 52 -0.75,-7; 53 -1.25,-7; 54 -1.75,-7; 55 -2.25,-7; 56 -2.75,-7; 57 -3.25,-7; 58 -3.75,-7; 59 -4.25,-7; 60 -4.75,-7
smd 1.8 x 0.35: 21 7,4.75; 22 7,4.25; 23 7,3.75; 24 7,3.25; 25 7,2.75; 26 7,2.25; 27 7,1.75; 28 7,1.25; 29 7,0.75; 30 7,0.25; 31 7,-0.25; 32 7,-0.75; 33 7,-1.25; 34 7,-1.75; 35 7,-2.25; 36 7,-2.75; 37 7,-3.25; 38 7,-3.75; 39 7,-4.25; 40 7,-4.75; 61 -7,-4.75; 62 -7,-4.25; 63 -7,-3.75; 64 -7,-3.25; 65 -7,-2.75; 66 -7,-2.25; 67 -7,-1.75; 68 -7,-1.25; 69 -7,-0.75; 70 -7,-0.25; 71 -7,0.25; 72 -7,0.75; 73 -7,1.25; 74 -7,1.75; 75 -7,2.25; 76 -7,2.75; 77 -7,3.25; 78 -7,3.75; 79 -7,4.25; 80 -7,4.75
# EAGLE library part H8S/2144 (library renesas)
H8S/2144 in 100 pin QFP

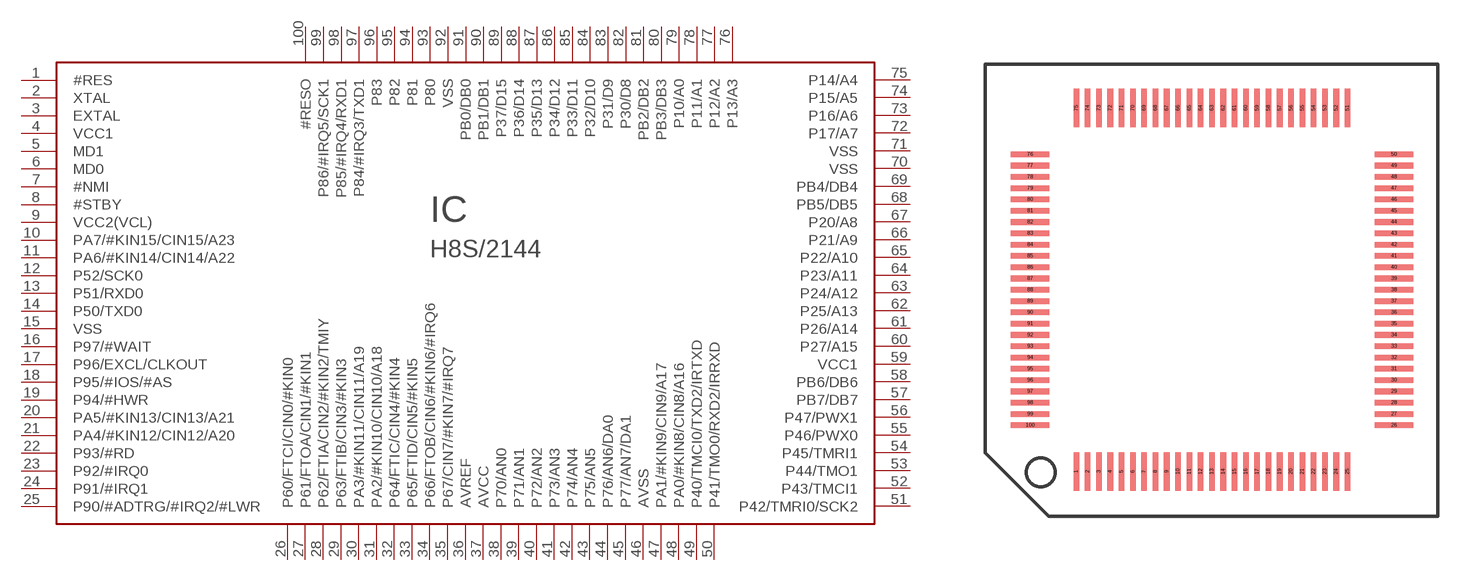
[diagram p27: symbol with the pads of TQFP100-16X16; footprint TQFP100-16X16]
Designator prefix IC

## H8S/2144FA  [TQFP100-16X16]
1  #RES  in
2  XTAL  pas
3  EXTAL  in
4  VCC1  pwr
5  MD1  in
6  MD0  in
7  #NMI  in
8  #STBY  in
9  VCC2(VCL)  pwr
10  PA7/#KIN15/CIN15/A23
11  PA6/#KIN14/CIN14/A22
12  P52/SCK0
13  P51/RXD0
14  P50/TXD0
15  VSS  pwr
16  P97/#WAIT
17  P96/EXCL/CLKOUT
18  P95/#IOS/#AS
19  P94/#HWR
20  PA5/#KIN13/CIN13/A21
21  PA4/#KIN12/CIN12/A20
22  P93/#RD
23  P92/#IRQ0
24  P91/#IRQ1
25  P90/#ADTRG/#IRQ2/#LWR
26  P60/FTCI/CIN0/#KIN0
27  P61/FTOA/CIN1/#KIN1
28  P62/FTIA/CIN2/#KIN2/TMIY
29  P63/FTIB/CIN3/#KIN3
30  PA3/#KIN11/CIN11/A19
31  PA2/#KIN10/CIN10/A18
32  P64/FTIC/CIN4/#KIN4
33  P65/FTID/CIN5/#KIN5
34  P66/FTOB/CIN6/#KIN6/#IRQ6
35  P67/CIN7/#KIN7/#IRQ7
36  AVREF
37  AVCC  pwr
38  P70/AN0
39  P71/AN1
40  P72/AN2
41  P73/AN3
42  P74/AN4
43  P75/AN5
44  P76/AN6/DA0
45  P77/AN7/DA1
46  AVSS  pwr
47  PA1/#KIN9/CIN9/A17
48  PA0/#KIN8/CIN8/A16
49  P40/TMCI0/TXD2/IRTXD
50  P41/TMO0/RXD2/IRRXD
51  P42/TMRI0/SCK2
52  P43/TMCI1
53  P44/TMO1
54  P45/TMRI1
55  P46/PWX0
56  P47/PWX1
57  PB7/DB7
58  PB6/DB6
59  VCC1  pwr
60  P27/A15
61  P26/A14
62  P25/A13
63  P24/A12
64  P23/A11
65  P22/A10
66  P21/A9
67  P20/A8
68  PB5/DB5
69  PB4/DB4
70  VSS  pwr
71  VSS  pwr
72  P17/A7
73  P16/A6
74  P15/A5
75  P14/A4
76  P13/A3
77  P12/A2
78  P11/A1
79  P10/A0
80  PB3/DB3
81  PB2/DB2
82  P30/D8
83  P31/D9
84  P32/D10
85  P33/D11
86  P34/D12
87  P35/D13
88  P36/D14
89  P37/D15
90  PB1/DB1
91  PB0/DB0
92  VSS  pwr
93  P80
94  P81
95  P82
96  P83
97  P84/#IRQ3/TXD1
98  P85/#IRQ4/RXD1
99  P86/#IRQ5/SCK1
100  #RESO  out

## H8S/2144TE  [TQFP100-16X16]
Pads as for TQFP100-16X16

## Footprint TQFP100-16X16 (pad centres in mm)
TQFP100 16x16mm 0.5mm pitch 0.25mm pad width
smd 0.25 x 1.7: 1 -6,-8.05; 2 -5.5,-8.05; 3 -5,-8.05; 4 -4.5,-8.05; 5 -4,-8.05; 6 -3.5,-8.05; 7 -3,-8.05; 8 -2.5,-8.05; 9 -2,-8.05; 10 -1.5,-8.05; 11 -1,-8.05; 12 -0.5,-8.05; 13 0,-8.05; 14 0.5,-8.05; 15 1,-8.05; 16 1.5,-8.05; 17 2,-8.05; 18 2.5,-8.05; 19 3,-8.05; 20 3.5,-8.05; 21 4,-8.05; 22 4.5,-8.05; 23 5,-8.05; 24 5.5,-8.05; 25 6,-8.05; 51 6,8.05; 52 5.5,8.05; 53 5,8.05; 54 4.5,8.05; 55 4,8.05; 56 3.5,8.05; 57 3,8.05; 58 2.5,8.05; 59 2,8.05; 60 1.5,8.05; 61 1,8.05; 62 0.5,8.05; 63 0,8.05; 64 -0.5,8.05; 65 -1,8.05; 66 -1.5,8.05; 67 -2,8.05; 68 -2.5,8.05; 69 -3,8.05; 70 -3.5,8.05; 71 -4,8.05; 72 -4.5,8.05; 73 -5,8.05; 74 -5.5,8.05; 75 -6,8.05
smd 1.7 x 0.25: 26 8.05,-6; 27 8.05,-5.5; 28 8.05,-5; 29 8.05,-4.5; 30 8.05,-4; 31 8.05,-3.5; 32 8.05,-3; 33 8.05,-2.5; 34 8.05,-2; 35 8.05,-1.5; 36 8.05,-1; 37 8.05,-0.5; 38 8.05,0; 39 8.05,0.5; 40 8.05,1; 41 8.05,1.5; 42 8.05,2; 43 8.05,2.5; 44 8.05,3; 45 8.05,3.5; 46 8.05,4; 47 8.05,4.5; 48 8.05,5; 49 8.05,5.5; 50 8.05,6; 76 -8.05,6; 77 -8.05,5.5; 78 -8.05,5; 79 -8.05,4.5; 80 -8.05,4; 81 -8.05,3.5; 82 -8.05,3; 83 -8.05,2.5; 84 -8.05,2; 85 -8.05,1.5; 86 -8.05,1; 87 -8.05,0.5; 88 -8.05,0; 89 -8.05,-0.5; 90 -8.05,-1; 91 -8.05,-1.5; 92 -8.05,-2; 93 -8.05,-2.5; 94 -8.05,-3; 95 -8.05,-3.5; 96 -8.05,-4; 97 -8.05,-4.5; 98 -8.05,-5; 99 -8.05,-5.5; 100 -8.05,-6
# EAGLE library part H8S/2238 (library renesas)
H8S/2238 in 100pin QFP and Rectangular QFP

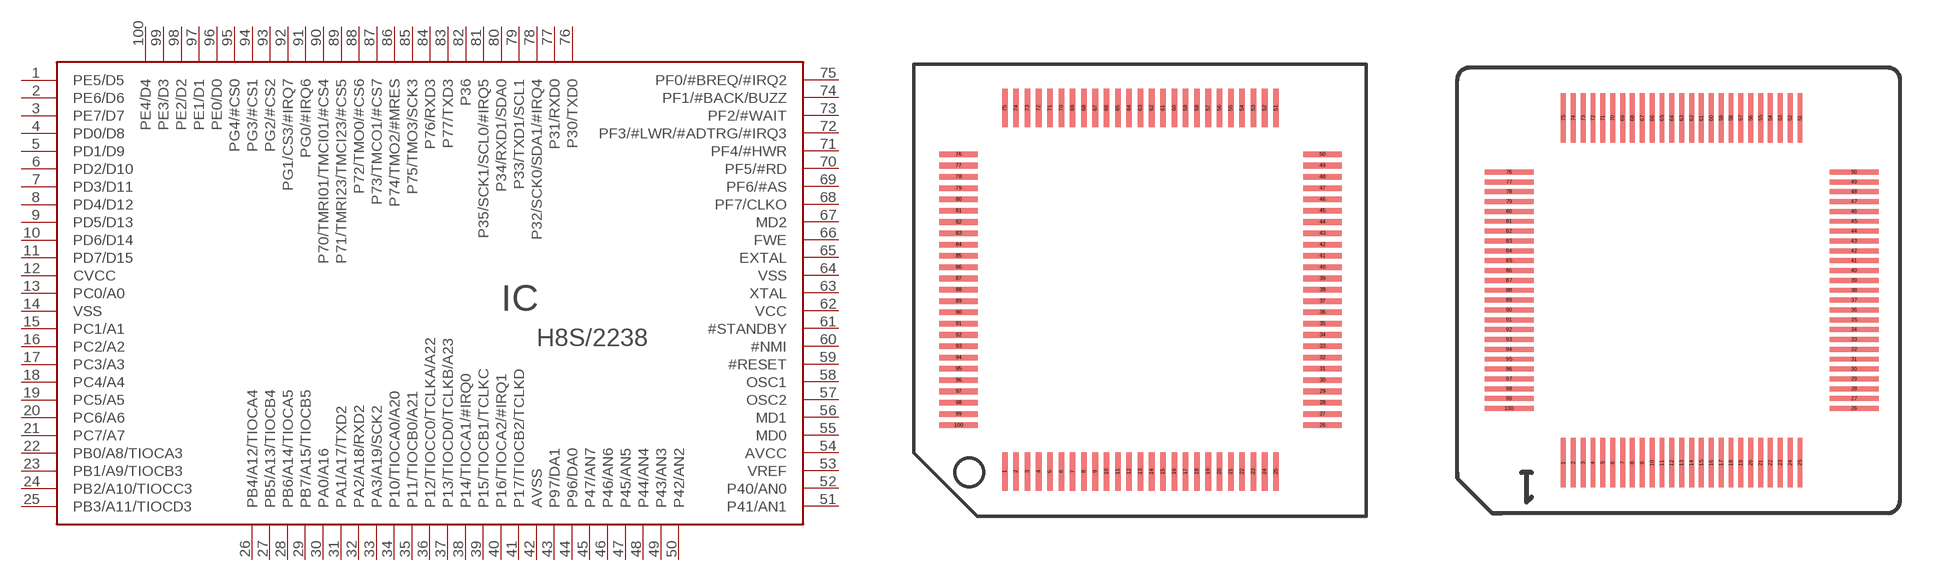
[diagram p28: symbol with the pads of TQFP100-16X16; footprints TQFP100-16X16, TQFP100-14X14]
Designator prefix IC

## H8S/2238TE  [TQFP100-16X16]
1  PE5/D5
2  PE6/D6
3  PE7/D7
4  PD0/D8
5  PD1/D9
6  PD2/D10
7  PD3/D11
8  PD4/D12
9  PD5/D13
10  PD6/D14
11  PD7/D15
12  CVCC  pwr
13  PC0/A0
14  VSS  pwr
15  PC1/A1
16  PC2/A2
17  PC3/A3
18  PC4/A4
19  PC5/A5
20  PC6/A6
21  PC7/A7
22  PB0/A8/TIOCA3
23  PB1/A9/TIOCB3
24  PB2/A10/TIOCC3
25  PB3/A11/TIOCD3
26  PB4/A12/TIOCA4
27  PB5/A13/TIOCB4
28  PB6/A14/TIOCA5
29  PB7/A15/TIOCB5
30  PA0/A16
31  PA1/A17/TXD2
32  PA2/A18/RXD2
33  PA3/A19/SCK2
34  P10/TIOCA0/A20
35  P11/TIOCB0/A21
36  P12/TIOCC0/TCLKA/A22
37  P13/TIOCD0/TCLKB/A23
38  P14/TIOCA1/#IRQ0
39  P15/TIOCB1/TCLKC
40  P16/TIOCA2/#IRQ1
41  P17/TIOCB2/TCLKD
42  AVSS  pwr
43  P97/DA1
44  P96/DA0
45  P47/AN7
46  P46/AN6
47  P45/AN5
48  P44/AN4
49  P43/AN3
50  P42/AN2
51  P41/AN1
52  P40/AN0
53  VREF  pwr
54  AVCC  pwr
55  MD0  in
56  MD1  in
57  OSC2  in
58  OSC1  in
59  #RESET  in
60  #NMI  in
61  #STANDBY  in
62  VCC  pwr
63  XTAL  pas
64  VSS  pwr
65  EXTAL  in
66  FWE
67  MD2  in
68  PF7/CLKO
69  PF6/#AS
70  PF5/#RD
71  PF4/#HWR
72  PF3/#LWR/#ADTRG/#IRQ3
73  PF2/#WAIT
74  PF1/#BACK/BUZZ
75  PF0/#BREQ/#IRQ2
76  P30/TXD0
77  P31/RXD0
78  P32/SCK0/SDA1/#IRQ4
79  P33/TXD1/SCL1
80  P34/RXD1/SDA0
81  P35/SCK1/SCL0/#IRQ5
82  P36
83  P77/TXD3
84  P76/RXD3
85  P75/TMO3/SCK3
86  P74/TMO2/#MRES
87  P73/TMCO1/#CS7
88  P72/TMO0/#CS6
89  P71/TMRI23/TMCI23/#CS5
90  P70/TMRI01/TMCI01/#CS4
91  PG0/#IRQ6
92  PG1/CS3/#IRQ7
93  PG2/#CS2
94  PG3/#CS1
95  PG4/#CS0
96  PE0/D0
97  PE1/D1
98  PE2/D2
99  PE3/D3
100  PE4/D4

## H8S/2238TF  [TQFP100-14X14]
Pads as for TQFP100-16X16

## H8S/2238F  [TQFP100-19X25]
1  PE2/D2
2  PE3/D3
3  PE4/D4
4  PE5/D5
5  PE6/D6
6  PE7/D7
7  PD0/D8
8  PD1/D9
9  PD2/D10
10  PD3/D11
11  PD4/D12
12  PD5/D13
13  PD6/D14
14  PD7/D15
15  CVCC  pwr
16  PC0/A0
17  VSS  pwr
18  PC1/A1
19  PC2/A2
20  PC3/A3
21  PC4/A4
22  PC5/A5
23  PC6/A6
24  PC7/A7
25  PB0/A8/TIOCA3
26  PB1/A9/TIOCB3
27  PB2/A10/TIOCC3
28  PB3/A11/TIOCD3
29  PB4/A12/TIOCA4
30  PB5/A13/TIOCB4
31  PB6/A14/TIOCA5
32  PB7/A15/TIOCB5
33  PA0/A16
34  PA1/A17/TXD2
35  PA2/A18/RXD2
36  PA3/A19/SCK2
37  P10/TIOCA0/A20
38  P11/TIOCB0/A21
39  P12/TIOCC0/TCLKA/A22
40  P13/TIOCD0/TCLKB/A23
41  P14/TIOCA1/#IRQ0
42  P15/TIOCB1/TCLKC
43  P16/TIOCA2/#IRQ1
44  P17/TIOCB2/TCLKD
45  AVSS  pwr
46  P97/DA1
47  P96/DA0
48  P47/AN7
49  P46/AN6
50  P45/AN5
51  P44/AN4
52  P43/AN3
53  P42/AN2
54  P41/AN1
55  P40/AN0
56  VREF  pwr
57  AVCC  pwr
58  MD0  in
59  MD1  in
60  OSC2  in
61  OSC1  in
62  #RESET  in
63  #NMI  in
64  #STANDBY  in
65  VCC  pwr
66  XTAL  pas
67  VSS  pwr
68  EXTAL  in
69  FWE
70  MD2  in
71  PF7/CLKO
72  PF6/#AS
73  PF5/#RD
74  PF4/#HWR
75  PF3/#LWR/#ADTRG/#IRQ3
76  PF2/#WAIT
77  PF1/#BACK/BUZZ
78  PF0/#BREQ/#IRQ2
79  P30/TXD0
80  P31/RXD0
81  P32/SCK0/SDA1/#IRQ4
82  P33/TXD1/SCL1
83  P34/RXD1/SDA0
84  P35/SCK1/SCL0/#IRQ5
85  P36
86  P77/TXD3
87  P76/RXD3
88  P75/TMO3/SCK3
89  P74/TMO2/#MRES
90  P73/TMCO1/#CS7
91  P72/TMO0/#CS6
92  P71/TMRI23/TMCI23/#CS5
93  P70/TMRI01/TMCI01/#CS4
94  PG0/#IRQ6
95  PG1/CS3/#IRQ7
96  PG2/#CS2
97  PG3/#CS1
98  PG4/#CS0
99  PE0/D0
100  PE1/D1

## Footprint TQFP100-16X16 (pad centres in mm)
TQFP100 16x16mm 0.5mm pitch 0.25mm pad width
smd 0.25 x 1.7: 1 -6,-8.05; 2 -5.5,-8.05; 3 -5,-8.05; 4 -4.5,-8.05; 5 -4,-8.05; 6 -3.5,-8.05; 7 -3,-8.05; 8 -2.5,-8.05; 9 -2,-8.05; 10 -1.5,-8.05; 11 -1,-8.05; 12 -0.5,-8.05; 13 0,-8.05; 14 0.5,-8.05; 15 1,-8.05; 16 1.5,-8.05; 17 2,-8.05; 18 2.5,-8.05; 19 3,-8.05; 20 3.5,-8.05; 21 4,-8.05; 22 4.5,-8.05; 23 5,-8.05; 24 5.5,-8.05; 25 6,-8.05; 51 6,8.05; 52 5.5,8.05; 53 5,8.05; 54 4.5,8.05; 55 4,8.05; 56 3.5,8.05; 57 3,8.05; 58 2.5,8.05; 59 2,8.05; 60 1.5,8.05; 61 1,8.05; 62 0.5,8.05; 63 0,8.05; 64 -0.5,8.05; 65 -1,8.05; 66 -1.5,8.05; 67 -2,8.05; 68 -2.5,8.05; 69 -3,8.05; 70 -3.5,8.05; 71 -4,8.05; 72 -4.5,8.05; 73 -5,8.05; 74 -5.5,8.05; 75 -6,8.05
smd 1.7 x 0.25: 26 8.05,-6; 27 8.05,-5.5; 28 8.05,-5; 29 8.05,-4.5; 30 8.05,-4; 31 8.05,-3.5; 32 8.05,-3; 33 8.05,-2.5; 34 8.05,-2; 35 8.05,-1.5; 36 8.05,-1; 37 8.05,-0.5; 38 8.05,0; 39 8.05,0.5; 40 8.05,1; 41 8.05,1.5; 42 8.05,2; 43 8.05,2.5; 44 8.05,3; 45 8.05,3.5; 46 8.05,4; 47 8.05,4.5; 48 8.05,5; 49 8.05,5.5; 50 8.05,6; 76 -8.05,6; 77 -8.05,5.5; 78 -8.05,5; 79 -8.05,4.5; 80 -8.05,4; 81 -8.05,3.5; 82 -8.05,3; 83 -8.05,2.5; 84 -8.05,2; 85 -8.05,1.5; 86 -8.05,1; 87 -8.05,0.5; 88 -8.05,0; 89 -8.05,-0.5; 90 -8.05,-1; 91 -8.05,-1.5; 92 -8.05,-2; 93 -8.05,-2.5; 94 -8.05,-3; 95 -8.05,-3.5; 96 -8.05,-4; 97 -8.05,-4.5; 98 -8.05,-5; 99 -8.05,-5.5; 100 -8.05,-6

## Footprint TQFP100-14X14 (pad centres in mm)
TQFP100 14x14mm 0.4mm pitch 0.2mm pad width
smd 0.2 x 2: 1 -4.8,-7; 2 -4.4,-7; 3 -4,-7; 4 -3.6,-7; 5 -3.2,-7; 6 -2.8,-7; 7 -2.4,-7; 8 -2,-7; 9 -1.6,-7; 10 -1.2,-7; 11 -0.8,-7; 12 -0.4,-7; 13 0,-7; 14 0.4,-7; 15 0.8,-7; 16 1.2,-7; 17 1.6,-7; 18 2,-7; 19 2.4,-7; 20 2.8,-7; 21 3.2,-7; 22 3.6,-7; 23 4,-7; 24 4.4,-7; 25 4.8,-7; 51 4.8,7; 52 4.4,7; 53 4,7; 54 3.6,7; 55 3.2,7; 56 2.8,7; 57 2.4,7; 58 2,7; 59 1.6,7; 60 1.2,7; 61 0.8,7; 62 0.4,7; 63 0,7; 64 -0.4,7; 65 -0.8,7; 66 -1.2,7; 67 -1.6,7; 68 -2,7; 69 -2.4,7; 70 -2.8,7; 71 -3.2,7; 72 -3.6,7; 73 -4,7; 74 -4.4,7; 75 -4.8,7
smd 2 x 0.2: 26 7,-4.8; 27 7,-4.4; 28 7,-4; 29 7,-3.6; 30 7,-3.2; 31 7,-2.8; 32 7,-2.4; 33 7,-2; 34 7,-1.6; 35 7,-1.2; 36 7,-0.8; 37 7,-0.4; 38 7,0; 39 7,0.4; 40 7,0.8; 41 7,1.2; 42 7,1.6; 43 7,2; 44 7,2.4; 45 7,2.8; 46 7,3.2; 47 7,3.6; 48 7,4; 49 7,4.4; 50 7,4.8; 76 -7,4.8; 77 -7,4.4; 78 -7,4; 79 -7,3.6; 80 -7,3.2; 81 -7,2.8; 82 -7,2.4; 83 -7,2; 84 -7,1.6; 85 -7,1.2; 86 -7,0.8; 87 -7,0.4; 88 -7,0; 89 -7,-0.4; 90 -7,-0.8; 91 -7,-1.2; 92 -7,-1.6; 93 -7,-2; 94 -7,-2.4; 95 -7,-2.8; 96 -7,-3.2; 97 -7,-3.6; 98 -7,-4; 99 -7,-4.4; 100 -7,-4.8

## Footprint TQFP100-19X25 (pad centres in mm)
PQFP100 19x25mm 0.65mm pitch 0.35mm pad width
smd 0.35 x 2: 1 -9.425,-9.9; 2 -8.775,-9.9; 3 -8.125,-9.9; 4 -7.475,-9.9; 5 -6.825,-9.9; 6 -6.175,-9.9; 7 -5.525,-9.9; 8 -4.875,-9.9; 9 -4.225,-9.9; 10 -3.575,-9.9; 11 -2.925,-9.9; 12 -2.275,-9.9; 13 -1.625,-9.9; 14 -0.975,-9.9; 15 -0.325,-9.9; 16 0.325,-9.9; 17 0.975,-9.9; 18 1.625,-9.9; 19 2.275,-9.9; 20 2.925,-9.9; 21 3.575,-9.9; 22 4.225,-9.9; 23 4.875,-9.9; 24 5.525,-9.9; 25 6.175,-9.9; 26 6.825,-9.9; 27 7.475,-9.9; 28 8.125,-9.9; 29 8.775,-9.9; 30 9.425,-9.9; 51 9.425,9.9; 52 8.775,9.9; 53 8.125,9.9; 54 7.475,9.9; 55 6.825,9.9; 56 6.175,9.9; 57 5.525,9.9; 58 4.875,9.9; 59 4.225,9.9; 60 3.575,9.9; 61 2.925,9.9; 62 2.275,9.9; 63 1.625,9.9; 64 0.975,9.9; 65 0.325,9.9; 66 -0.325,9.9; 67 -0.975,9.9; 68 -1.625,9.9; 69 -2.275,9.9; 70 -2.925,9.9; 71 -3.575,9.9; 72 -4.225,9.9; 73 -4.875,9.9; 74 -5.525,9.9; 75 -6.175,9.9; 76 -6.825,9.9; 77 -7.475,9.9; 78 -8.125,9.9; 79 -8.775,9.9; 80 -9.425,9.9
smd 2 x 0.35: 31 12.4,-6.175; 32 12.4,-5.525; 33 12.4,-4.875; 34 12.4,-4.225; 35 12.4,-3.575; 36 12.4,-2.925; 37 12.4,-2.275; 38 12.4,-1.625; 39 12.4,-0.975; 40 12.4,-0.325; 41 12.4,0.325; 42 12.4,0.975; 43 12.4,1.625; 44 12.4,2.275; 45 12.4,2.925; 46 12.4,3.575; 47 12.4,4.225; 48 12.4,4.875; 49 12.4,5.525; 50 12.4,6.175; 81 -12.39,6.175; 82 -12.39,5.525; 83 -12.39,4.875; 84 -12.39,4.225; 85 -12.39,3.575; 86 -12.39,2.925; 87 -12.39,2.275; 88 -12.39,1.625; 89 -12.39,0.975; 90 -12.39,0.325; 91 -12.39,-0.325; 92 -12.39,-0.975; 93 -12.39,-1.625; 94 -12.39,-2.275; 95 -12.39,-2.925; 96 -12.39,-3.575; 97 -12.39,-4.225; 98 -12.39,-4.875; 99 -12.39,-5.525; 100 -12.39,-6.175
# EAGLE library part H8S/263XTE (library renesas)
H8S/263X in 120 pin QFP 16 x 16mm 0.4mm pitch

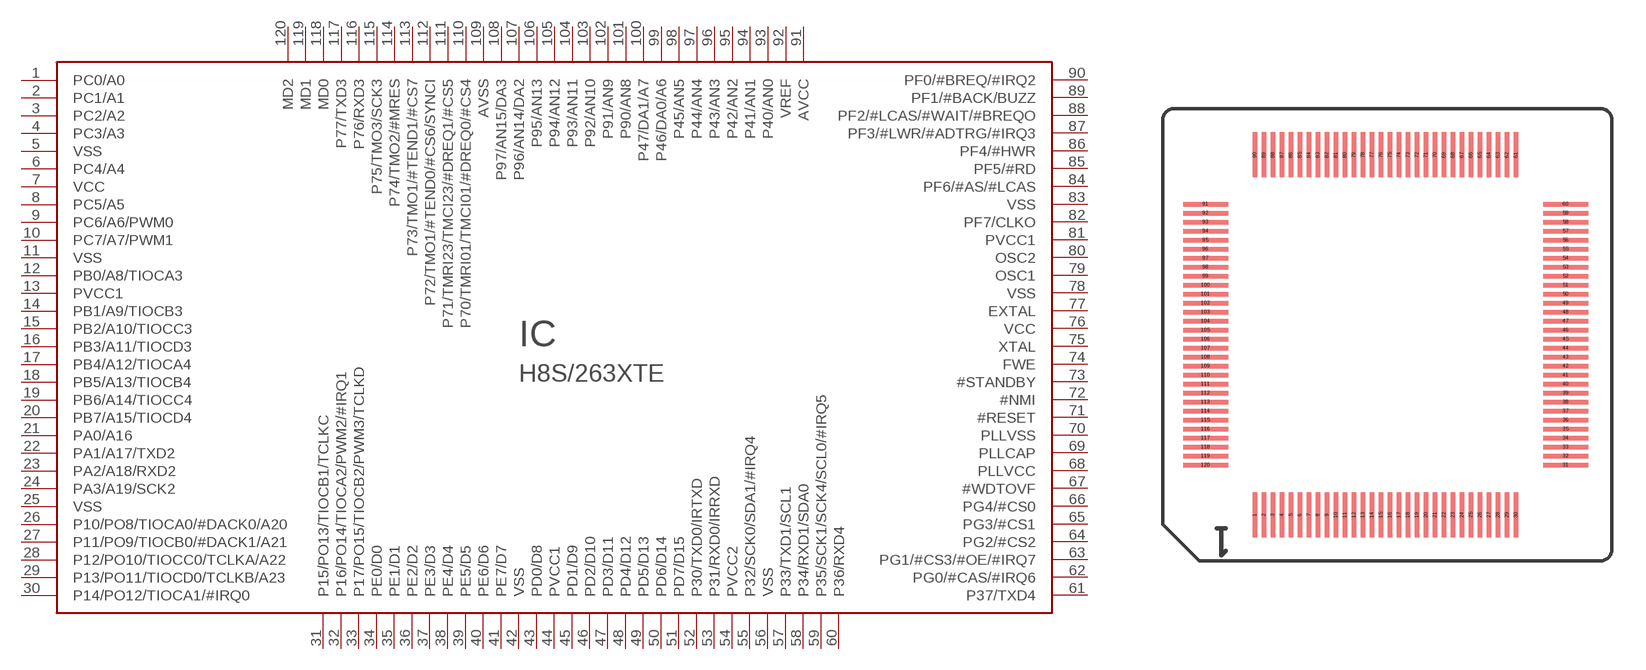
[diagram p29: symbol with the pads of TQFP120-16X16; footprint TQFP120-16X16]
Designator prefix IC

## H8S/263XTE  [TQFP120-16X16]
1  PC0/A0
2  PC1/A1
3  PC2/A2
4  PC3/A3
5  VSS  pwr
6  PC4/A4
7  VCC  pwr
8  PC5/A5
9  PC6/A6/PWM0
10  PC7/A7/PWM1
11  VSS  pwr
12  PB0/A8/TIOCA3
13  PVCC1  pwr
14  PB1/A9/TIOCB3
15  PB2/A10/TIOCC3
16  PB3/A11/TIOCD3
17  PB4/A12/TIOCA4
18  PB5/A13/TIOCB4
19  PB6/A14/TIOCC4
20  PB7/A15/TIOCD4
21  PA0/A16
22  PA1/A17/TXD2
23  PA2/A18/RXD2
24  PA3/A19/SCK2
25  VSS  pwr
26  P10/PO8/TIOCA0/#DACK0/A20
27  P11/PO9/TIOCB0/#DACK1/A21
28  P12/PO10/TIOCC0/TCLKA/A22
29  P13/PO11/TIOCD0/TCLKB/A23
30  P14/PO12/TIOCA1/#IRQ0
31  P15/PO13/TIOCB1/TCLKC
32  P16/PO14/TIOCA2/PWM2/#IRQ1
33  P17/PO15/TIOCB2/PWM3/TCLKD
34  PE0/D0
35  PE1/D1
36  PE2/D2
37  PE3/D3
38  PE4/D4
39  PE5/D5
40  PE6/D6
41  PE7/D7
42  VSS  pwr
43  PD0/D8
44  PVCC1  pwr
45  PD1/D9
46  PD2/D10
47  PD3/D11
48  PD4/D12
49  PD5/D13
50  PD6/D14
51  PD7/D15
52  P30/TXD0/IRTXD
53  P31/RXD0/IRRXD
54  PVCC2  pwr
55  P32/SCK0/SDA1/#IRQ4
56  VSS  pwr
57  P33/TXD1/SCL1
58  P34/RXD1/SDA0
59  P35/SCK1/SCK4/SCL0/#IRQ5
60  P36/RXD4
61  P37/TXD4
62  PG0/#CAS/#IRQ6
63  PG1/#CS3/#OE/#IRQ7
64  PG2/#CS2
65  PG3/#CS1
66  PG4/#CS0
67  #WDTOVF  out
68  PLLVCC  pwr
69  PLLCAP  pas
70  PLLVSS  pwr
71  #RESET  in
72  #NMI  in
73  #STANDBY  in
74  FWE
75  XTAL  pas
76  VCC  pwr
77  EXTAL  in
78  VSS  pwr
79  OSC1  in
80  OSC2  in
81  PVCC1  pwr
82  PF7/CLKO
83  VSS  pwr
84  PF6/#AS/#LCAS
85  PF5/#RD
86  PF4/#HWR
87  PF3/#LWR/#ADTRG/#IRQ3
88  PF2/#LCAS/#WAIT/#BREQO
89  PF1/#BACK/BUZZ
90  PF0/#BREQ/#IRQ2
91  AVCC  pwr
92  VREF  pwr
93  P40/AN0
94  P41/AN1
95  P42/AN2
96  P43/AN3
97  P44/AN4
98  P45/AN5
99  P46/DA0/A6
100  P47/DA1/A7
101  P90/AN8
102  P91/AN9
103  P92/AN10
104  P93/AN11
105  P94/AN12
106  P95/AN13
107  P96/AN14/DA2
108  P97/AN15/DA3
109  AVSS  pwr
110  P70/TMRI01/TMCI01/#DREQ0/#CS4
111  P71/TMRI23/TMCI23/#DREQ1/#CS5
112  P72/TMO1/#TEND0/#CS6/SYNCI
113  P73/TMO1/#TEND1/#CS7
114  P74/TMO2/#MRES
115  P75/TMO3/SCK3
116  P76/RXD3
117  P77/TXD3
118  MD0  in
119  MD1  in
120  MD2  in

## Footprint TQFP120-16X16 (pad centres in mm)
TQFP120 16x16mm 0.4mm pitch 0.2mm pad width
smd 0.2 x 2: 1 -5.8,-8; 2 -5.4,-8; 3 -5,-8; 4 -4.6,-8; 5 -4.2,-8; 6 -3.8,-8; 7 -3.4,-8; 8 -3,-8; 9 -2.6,-8; 10 -2.2,-8; 11 -1.8,-8; 12 -1.4,-8; 13 -1,-8; 14 -0.6,-8; 15 -0.2,-8; 16 0.2,-8; 17 0.6,-8; 18 1,-8; 19 1.4,-8; 20 1.8,-8; 21 2.2,-8; 22 2.6,-8; 23 3,-8; 24 3.4,-8; 25 3.8,-8; 26 4.2,-8; 27 4.6,-8; 28 5,-8; 29 5.4,-8; 30 5.8,-8; 61 5.8,8; 62 5.4,8; 63 5,8; 64 4.6,8; 65 4.2,8; 66 3.8,8; 67 3.4,8; 68 3,8; 69 2.6,8; 70 2.2,8; 71 1.8,8; 72 1.4,8; 73 1,8; 74 0.6,8; 75 0.2,8; 76 -0.2,8; 77 -0.6,8; 78 -1,8; 79 -1.4,8; 80 -1.8,8; 81 -2.2,8; 82 -2.6,8; 83 -3,8; 84 -3.4,8; 85 -3.8,8; 86 -4.2,8; 87 -4.6,8; 88 -5,8; 89 -5.4,8; 90 -5.8,8
smd 2 x 0.2: 31 8,-5.8; 32 8,-5.4; 33 8,-5; 34 8,-4.6; 35 8,-4.2; 36 8,-3.8; 37 8,-3.4; 38 8,-3; 39 8,-2.6; 40 8,-2.2; 41 8,-1.8; 42 8,-1.4; 43 8,-1; 44 8,-0.6; 45 8,-0.2; 46 8,0.2; 47 8,0.6; 48 8,1; 49 8,1.4; 50 8,1.8; 51 8,2.2; 52 8,2.6; 53 8,3; 54 8,3.4; 55 8,3.8; 56 8,4.2; 57 8,4.6; 58 8,5; 59 8,5.4; 60 8,5.8; 91 -8,5.8; 92 -8,5.4; 93 -8,5; 94 -8,4.6; 95 -8,4.2; 96 -8,3.8; 97 -8,3.4; 98 -8,3; 99 -8,2.6; 100 -8,2.2; 101 -8,1.8; 102 -8,1.4; 103 -8,1; 104 -8,0.6; 105 -8,0.2; 106 -8,-0.2; 107 -8,-0.6; 108 -8,-1; 109 -8,-1.4; 110 -8,-1.8; 111 -8,-2.2; 112 -8,-2.6; 113 -8,-3; 114 -8,-3.4; 115 -8,-3.8; 116 -8,-4.2; 117 -8,-4.6; 118 -8,-5; 119 -8,-5.4; 120 -8,-5.8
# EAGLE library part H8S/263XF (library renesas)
H8S/263X in 128pin QFP 22 x 16 0.5mm pitch

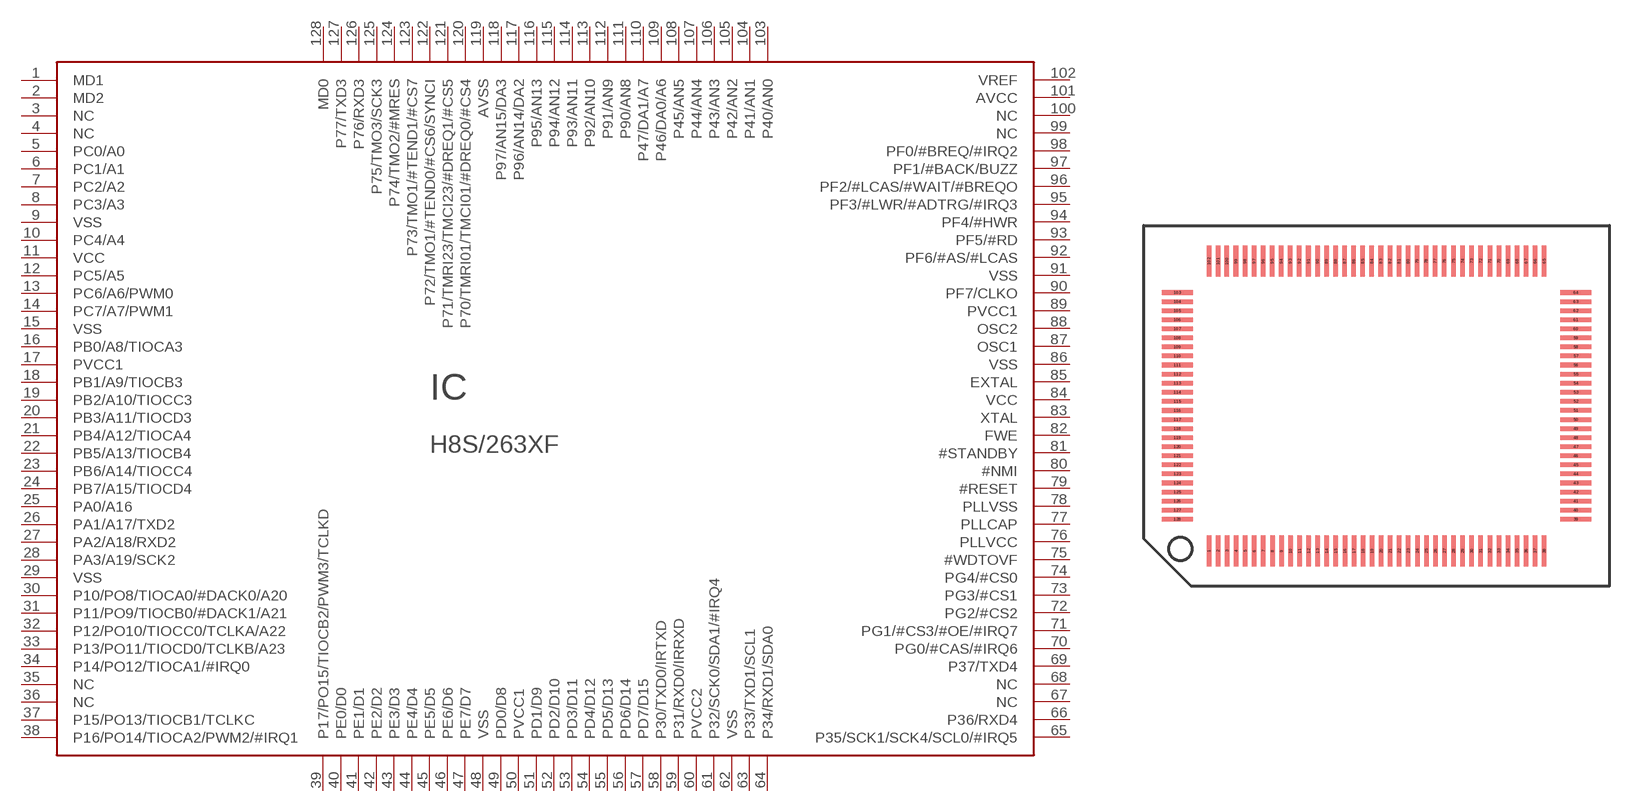
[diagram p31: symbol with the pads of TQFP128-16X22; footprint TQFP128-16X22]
Designator prefix IC

## H8S/263XF  [TQFP128-16X22]
1  MD1  in
2  MD2  in
3  NC  nc
4  NC  nc
5  PC0/A0
6  PC1/A1
7  PC2/A2
8  PC3/A3
9  VSS  pwr
10  PC4/A4
11  VCC  pwr
12  PC5/A5
13  PC6/A6/PWM0
14  PC7/A7/PWM1
15  VSS  pwr
16  PB0/A8/TIOCA3
17  PVCC1  pwr
18  PB1/A9/TIOCB3
19  PB2/A10/TIOCC3
20  PB3/A11/TIOCD3
21  PB4/A12/TIOCA4
22  PB5/A13/TIOCB4
23  PB6/A14/TIOCC4
24  PB7/A15/TIOCD4
25  PA0/A16
26  PA1/A17/TXD2
27  PA2/A18/RXD2
28  PA3/A19/SCK2
29  VSS  pwr
30  P10/PO8/TIOCA0/#DACK0/A20
31  P11/PO9/TIOCB0/#DACK1/A21
32  P12/PO10/TIOCC0/TCLKA/A22
33  P13/PO11/TIOCD0/TCLKB/A23
34  P14/PO12/TIOCA1/#IRQ0
35  NC  nc
36  NC  nc
37  P15/PO13/TIOCB1/TCLKC
38  P16/PO14/TIOCA2/PWM2/#IRQ1
39  P17/PO15/TIOCB2/PWM3/TCLKD
40  PE0/D0
41  PE1/D1
42  PE2/D2
43  PE3/D3
44  PE4/D4
45  PE5/D5
46  PE6/D6
47  PE7/D7
48  VSS  pwr
49  PD0/D8
50  PVCC1  pwr
51  PD1/D9
52  PD2/D10
53  PD3/D11
54  PD4/D12
55  PD5/D13
56  PD6/D14
57  PD7/D15
58  P30/TXD0/IRTXD
59  P31/RXD0/IRRXD
60  PVCC2  pwr
61  P32/SCK0/SDA1/#IRQ4
62  VSS  pwr
63  P33/TXD1/SCL1
64  P34/RXD1/SDA0
65  P35/SCK1/SCK4/SCL0/#IRQ5
66  P36/RXD4
67  NC  nc
68  NC  nc
69  P37/TXD4
70  PG0/#CAS/#IRQ6
71  PG1/#CS3/#OE/#IRQ7
72  PG2/#CS2
73  PG3/#CS1
74  PG4/#CS0
75  #WDTOVF  out
76  PLLVCC  pwr
77  PLLCAP  pas
78  PLLVSS  pwr
79  #RESET  in
80  #NMI  in
81  #STANDBY  in
82  FWE
83  XTAL  pas
84  VCC  pwr
85  EXTAL  in
86  VSS  pwr
87  OSC1  in
88  OSC2  in
89  PVCC1  pwr
90  PF7/CLKO
91  VSS  pwr
92  PF6/#AS/#LCAS
93  PF5/#RD
94  PF4/#HWR
95  PF3/#LWR/#ADTRG/#IRQ3
96  PF2/#LCAS/#WAIT/#BREQO
97  PF1/#BACK/BUZZ
98  PF0/#BREQ/#IRQ2
99  NC  nc
100  NC  nc
101  AVCC  pwr
102  VREF  pwr
103  P40/AN0
104  P41/AN1
105  P42/AN2
106  P43/AN3
107  P44/AN4
108  P45/AN5
109  P46/DA0/A6
110  P47/DA1/A7
111  P90/AN8
112  P91/AN9
113  P92/AN10
114  P93/AN11
115  P94/AN12
116  P95/AN13
117  P96/AN14/DA2
118  P97/AN15/DA3
119  AVSS  pwr
120  P70/TMRI01/TMCI01/#DREQ0/#CS4
121  P71/TMRI23/TMCI23/#DREQ1/#CS5
122  P72/TMO1/#TEND0/#CS6/SYNCI
123  P73/TMO1/#TEND1/#CS7
124  P74/TMO2/#MRES
125  P75/TMO3/SCK3
126  P76/RXD3
127  P77/TXD3
128  MD0  in

## Footprint TQFP128-16X22 (pad centres in mm)
TQFP128 16x22mm 0.5mm pitch 0.25mm pad width
smd 0.25 x 1.7: 1 -9.25,-8; 2 -8.75,-8; 3 -8.25,-8; 4 -7.75,-8; 5 -7.25,-8; 6 -6.75,-8; 7 -6.25,-8; 8 -5.75,-8; 9 -5.25,-8; 10 -4.75,-8; 11 -4.25,-8; 12 -3.75,-8; 13 -3.25,-8; 14 -2.75,-8; 15 -2.25,-8; 16 -1.75,-8; 17 -1.25,-8; 18 -0.75,-8; 19 -0.25,-8; 20 0.25,-8; 21 0.75,-8; 22 1.25,-8; 23 1.75,-8; 24 2.25,-8; 25 2.75,-8; 26 3.25,-8; 27 3.75,-8; 28 4.25,-8; 29 4.75,-8; 30 5.25,-8; 31 5.75,-8; 32 6.25,-8; 33 6.75,-8; 34 7.25,-8; 35 7.75,-8; 36 8.25,-8; 37 8.75,-8; 38 9.25,-8; 65 9.25,8; 66 8.75,8; 67 8.25,8; 68 7.75,8; 69 7.25,8; 70 6.75,8; 71 6.25,8; 72 5.75,8; 73 5.25,8; 74 4.75,8; 75 4.25,8; 76 3.735,7.995; 77 3.235,7.995; 78 2.735,7.995; 79 2.235,7.995; 80 1.735,7.995; 81 1.235,7.995; 82 0.735,7.995; 83 0.235,7.995; 84 -0.265,7.995; 85 -0.765,7.995; 86 -1.265,7.995; 87 -1.765,7.995; 88 -2.265,7.995; 89 -2.765,7.995; 90 -3.265,7.995; 91 -3.765,7.995; 92 -4.265,7.995; 93 -4.765,7.995; 94 -5.265,7.995; 95 -5.765,7.995; 96 -6.265,7.995; 97 -6.765,7.995; 98 -7.265,7.995; 99 -7.765,7.995; 100 -8.265,7.995; 101 -8.75,8; 102 -9.25,8
smd 1.7 x 0.25: 39 11,-6.25; 40 11,-5.75; 41 11,-5.25; 42 11,-4.75; 43 11,-4.25; 44 11,-3.75; 45 11,-3.25; 46 11,-2.75; 47 11,-2.25; 48 11,-1.75; 49 11,-1.25; 50 11,-0.75; 51 11,-0.24; 52 11,0.26; 53 11,0.76; 54 11,1.26; 55 11,1.76; 56 11,2.26; 57 11,2.76; 58 11,3.26; 59 11,3.76; 60 11,4.26; 61 11,4.76; 62 11,5.26; 63 11,5.76; 64 11,6.26; 103 -11,6.26; 104 -11,5.76; 105 -11,5.26; 106 -11,4.76; 107 -11,4.26; 108 -11,3.76; 109 -11,3.26; 110 -11,2.76; 111 -11,2.26; 112 -11,1.76; 113 -11,1.26; 114 -11,0.76; 115 -11,0.25; 116 -11,-0.25; 117 -11,-0.75; 118 -11,-1.25; 119 -11,-1.75; 120 -11,-2.25; 121 -11,-2.75; 122 -11,-3.25; 123 -11,-3.75; 124 -11,-4.25; 125 -11,-4.75; 126 -11,-5.25; 127 -11,-5.75; 128 -11,-6.25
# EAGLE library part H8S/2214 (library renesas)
H8S/2214 in 100pin QFP

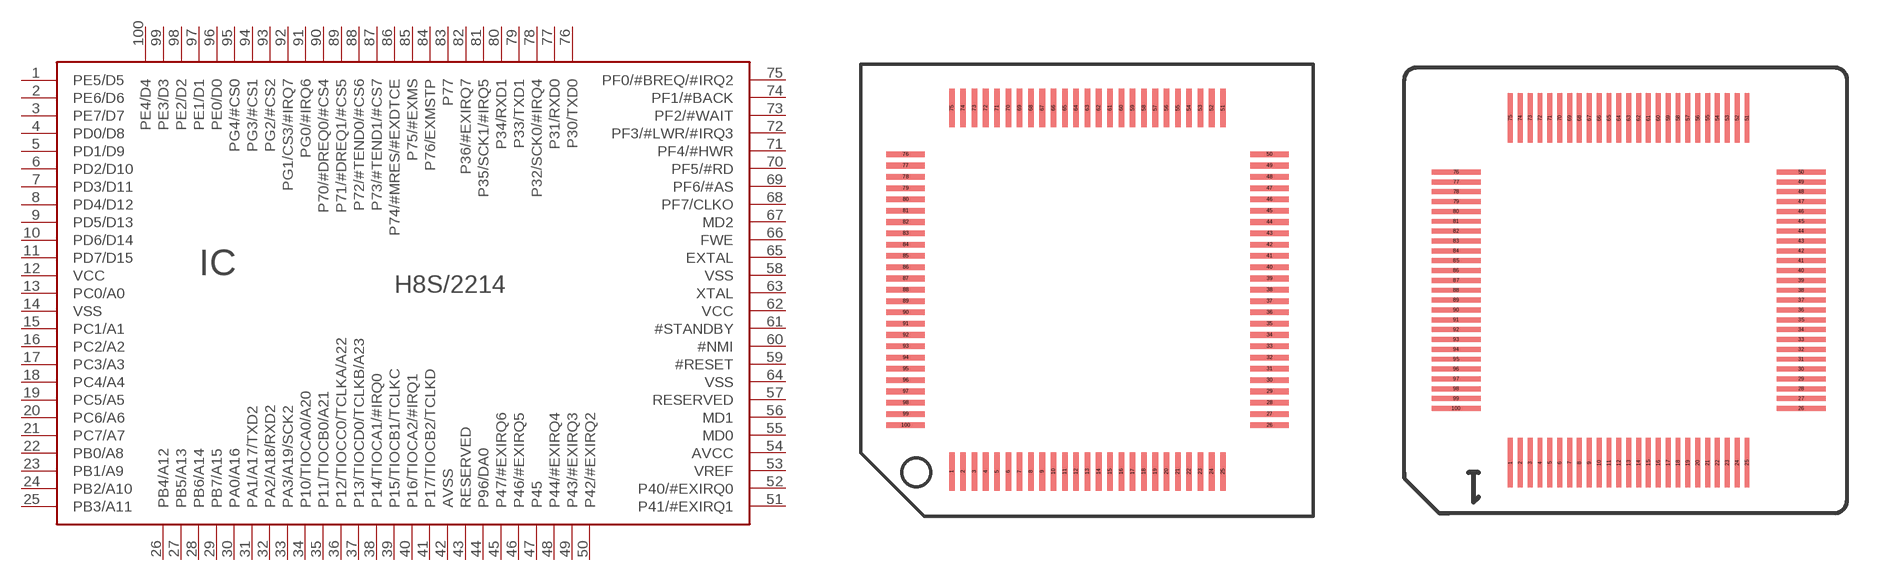
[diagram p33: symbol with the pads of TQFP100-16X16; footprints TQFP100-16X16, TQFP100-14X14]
Designator prefix IC

## H8S/2214TE  [TQFP100-16X16]
1  PE5/D5
2  PE6/D6
3  PE7/D7
4  PD0/D8
5  PD1/D9
6  PD2/D10
7  PD3/D11
8  PD4/D12
9  PD5/D13
10  PD6/D14
11  PD7/D15
12  VCC  pwr
13  PC0/A0
14  VSS  pwr
15  PC1/A1
16  PC2/A2
17  PC3/A3
18  PC4/A4
19  PC5/A5
20  PC6/A6
21  PC7/A7
22  PB0/A8
23  PB1/A9
24  PB2/A10
25  PB3/A11
26  PB4/A12
27  PB5/A13
28  PB6/A14
29  PB7/A15
30  PA0/A16
31  PA1/A17/TXD2
32  PA2/A18/RXD2
33  PA3/A19/SCK2
34  P10/TIOCA0/A20
35  P11/TIOCB0/A21
36  P12/TIOCC0/TCLKA/A22
37  P13/TIOCD0/TCLKB/A23
38  P14/TIOCA1/#IRQ0
39  P15/TIOCB1/TCLKC
40  P16/TIOCA2/#IRQ1
41  P17/TIOCB2/TCLKD
42  AVSS  pwr
43  RESERVED  nc
44  P96/DA0
45  P47/#EXIRQ6
46  P46/#EXIRQ5
47  P45
48  P44/#EXIRQ4
49  P43/#EXIRQ3
50  P42/#EXIRQ2
51  P41/#EXIRQ1
52  P40/#EXIRQ0
53  VREF  pwr
54  AVCC  pwr
55  MD0  in
56  MD1  in
57  RESERVED  nc
58  VSS  pwr
59  #RESET  in
60  #NMI  in
61  #STANDBY  in
62  VCC  pwr
63  XTAL  pas
64  VSS  pwr
65  EXTAL  in
66  FWE
67  MD2  in
68  PF7/CLKO
69  PF6/#AS
70  PF5/#RD
71  PF4/#HWR
72  PF3/#LWR/#IRQ3
73  PF2/#WAIT
74  PF1/#BACK
75  PF0/#BREQ/#IRQ2
76  P30/TXD0
77  P31/RXD0
78  P32/SCK0/#IRQ4
79  P33/TXD1
80  P34/RXD1
81  P35/SCK1/#IRQ5
82  P36/#EXIRQ7
83  P77
84  P76/EXMSTP
85  P75/#EXMS
86  P74/#MRES/#EXDTCE
87  P73/#TEND1/#CS7
88  P72/#TEND0/#CS6
89  P71/#DREQ1/#CS5
90  P70/#DREQ0/#CS4
91  PG0/#IRQ6
92  PG1/CS3/#IRQ7
93  PG2/#CS2
94  PG3/#CS1
95  PG4/#CS0
96  PE0/D0
97  PE1/D1
98  PE2/D2
99  PE3/D3
100  PE4/D4

## H8S/2214TF  [TQFP100-14X14]
Pads as for TQFP100-16X16

## Footprint TQFP100-16X16 (pad centres in mm)
TQFP100 16x16mm 0.5mm pitch 0.25mm pad width
smd 0.25 x 1.7: 1 -6,-8.05; 2 -5.5,-8.05; 3 -5,-8.05; 4 -4.5,-8.05; 5 -4,-8.05; 6 -3.5,-8.05; 7 -3,-8.05; 8 -2.5,-8.05; 9 -2,-8.05; 10 -1.5,-8.05; 11 -1,-8.05; 12 -0.5,-8.05; 13 0,-8.05; 14 0.5,-8.05; 15 1,-8.05; 16 1.5,-8.05; 17 2,-8.05; 18 2.5,-8.05; 19 3,-8.05; 20 3.5,-8.05; 21 4,-8.05; 22 4.5,-8.05; 23 5,-8.05; 24 5.5,-8.05; 25 6,-8.05; 51 6,8.05; 52 5.5,8.05; 53 5,8.05; 54 4.5,8.05; 55 4,8.05; 56 3.5,8.05; 57 3,8.05; 58 2.5,8.05; 59 2,8.05; 60 1.5,8.05; 61 1,8.05; 62 0.5,8.05; 63 0,8.05; 64 -0.5,8.05; 65 -1,8.05; 66 -1.5,8.05; 67 -2,8.05; 68 -2.5,8.05; 69 -3,8.05; 70 -3.5,8.05; 71 -4,8.05; 72 -4.5,8.05; 73 -5,8.05; 74 -5.5,8.05; 75 -6,8.05
smd 1.7 x 0.25: 26 8.05,-6; 27 8.05,-5.5; 28 8.05,-5; 29 8.05,-4.5; 30 8.05,-4; 31 8.05,-3.5; 32 8.05,-3; 33 8.05,-2.5; 34 8.05,-2; 35 8.05,-1.5; 36 8.05,-1; 37 8.05,-0.5; 38 8.05,0; 39 8.05,0.5; 40 8.05,1; 41 8.05,1.5; 42 8.05,2; 43 8.05,2.5; 44 8.05,3; 45 8.05,3.5; 46 8.05,4; 47 8.05,4.5; 48 8.05,5; 49 8.05,5.5; 50 8.05,6; 76 -8.05,6; 77 -8.05,5.5; 78 -8.05,5; 79 -8.05,4.5; 80 -8.05,4; 81 -8.05,3.5; 82 -8.05,3; 83 -8.05,2.5; 84 -8.05,2; 85 -8.05,1.5; 86 -8.05,1; 87 -8.05,0.5; 88 -8.05,0; 89 -8.05,-0.5; 90 -8.05,-1; 91 -8.05,-1.5; 92 -8.05,-2; 93 -8.05,-2.5; 94 -8.05,-3; 95 -8.05,-3.5; 96 -8.05,-4; 97 -8.05,-4.5; 98 -8.05,-5; 99 -8.05,-5.5; 100 -8.05,-6

## Footprint TQFP100-14X14 (pad centres in mm)
TQFP100 14x14mm 0.4mm pitch 0.2mm pad width
smd 0.2 x 2: 1 -4.8,-7; 2 -4.4,-7; 3 -4,-7; 4 -3.6,-7; 5 -3.2,-7; 6 -2.8,-7; 7 -2.4,-7; 8 -2,-7; 9 -1.6,-7; 10 -1.2,-7; 11 -0.8,-7; 12 -0.4,-7; 13 0,-7; 14 0.4,-7; 15 0.8,-7; 16 1.2,-7; 17 1.6,-7; 18 2,-7; 19 2.4,-7; 20 2.8,-7; 21 3.2,-7; 22 3.6,-7; 23 4,-7; 24 4.4,-7; 25 4.8,-7; 51 4.8,7; 52 4.4,7; 53 4,7; 54 3.6,7; 55 3.2,7; 56 2.8,7; 57 2.4,7; 58 2,7; 59 1.6,7; 60 1.2,7; 61 0.8,7; 62 0.4,7; 63 0,7; 64 -0.4,7; 65 -0.8,7; 66 -1.2,7; 67 -1.6,7; 68 -2,7; 69 -2.4,7; 70 -2.8,7; 71 -3.2,7; 72 -3.6,7; 73 -4,7; 74 -4.4,7; 75 -4.8,7
smd 2 x 0.2: 26 7,-4.8; 27 7,-4.4; 28 7,-4; 29 7,-3.6; 30 7,-3.2; 31 7,-2.8; 32 7,-2.4; 33 7,-2; 34 7,-1.6; 35 7,-1.2; 36 7,-0.8; 37 7,-0.4; 38 7,0; 39 7,0.4; 40 7,0.8; 41 7,1.2; 42 7,1.6; 43 7,2; 44 7,2.4; 45 7,2.8; 46 7,3.2; 47 7,3.6; 48 7,4; 49 7,4.4; 50 7,4.8; 76 -7,4.8; 77 -7,4.4; 78 -7,4; 79 -7,3.6; 80 -7,3.2; 81 -7,2.8; 82 -7,2.4; 83 -7,2; 84 -7,1.6; 85 -7,1.2; 86 -7,0.8; 87 -7,0.4; 88 -7,0; 89 -7,-0.4; 90 -7,-0.8; 91 -7,-1.2; 92 -7,-1.6; 93 -7,-2; 94 -7,-2.4; 95 -7,-2.8; 96 -7,-3.2; 97 -7,-3.6; 98 -7,-4; 99 -7,-4.4; 100 -7,-4.8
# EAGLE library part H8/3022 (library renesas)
H8/3022, H8/3039 in 80 pin QFP

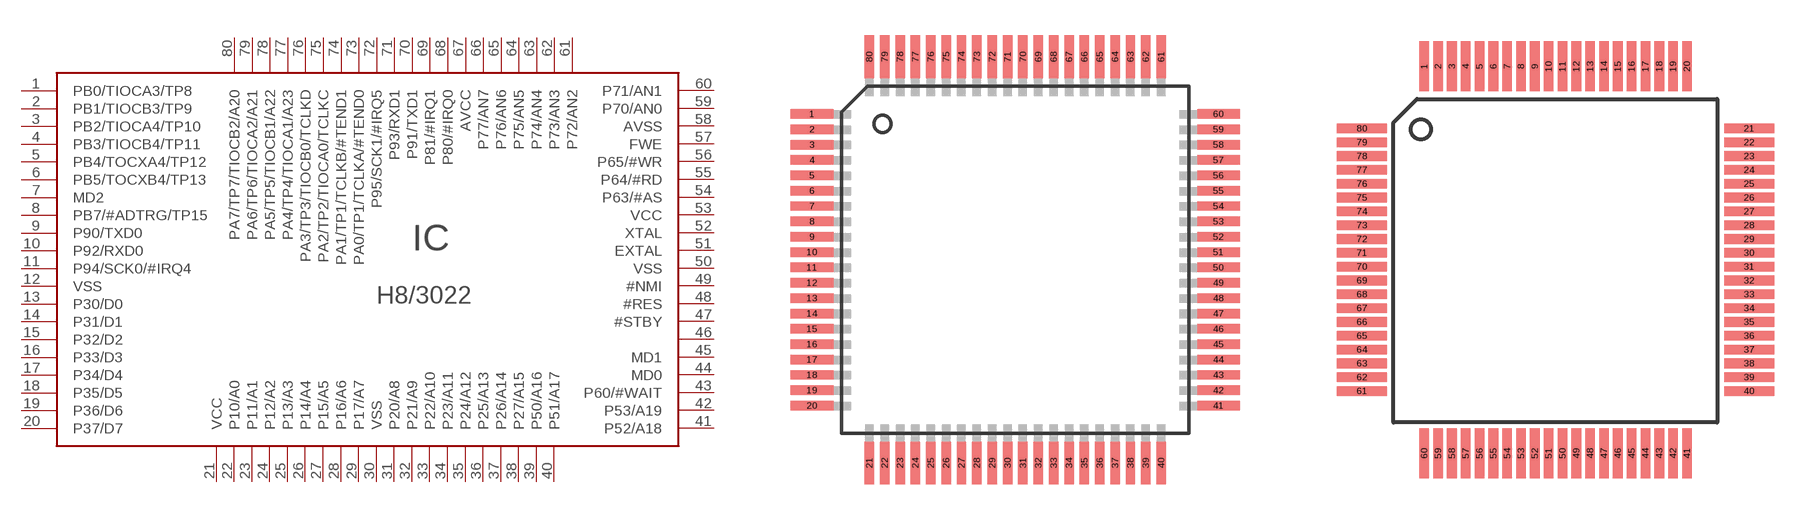
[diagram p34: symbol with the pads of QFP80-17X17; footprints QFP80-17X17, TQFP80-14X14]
Designator prefix IC

## H8/3022F  [QFP80-17X17]
1  PB0/TIOCA3/TP8
2  PB1/TIOCB3/TP9
3  PB2/TIOCA4/TP10
4  PB3/TIOCB4/TP11
5  PB4/TOCXA4/TP12
6  PB5/TOCXB4/TP13
7  MD2  in
8  PB7/#ADTRG/TP15
9  P90/TXD0
10  P92/RXD0
11  P94/SCK0/#IRQ4
12  VSS  pwr
13  P30/D0
14  P31/D1
15  P32/D2
16  P33/D3
17  P34/D4
18  P35/D5
19  P36/D6
20  P37/D7
21  VCC  pwr
22  P10/A0
23  P11/A1
24  P12/A2
25  P13/A3
26  P14/A4
27  P15/A5
28  P16/A6
29  P17/A7
30  VSS  pwr
31  P20/A8
32  P21/A9
33  P22/A10
34  P23/A11
35  P24/A12
36  P25/A13
37  P26/A14
38  P27/A15
39  P50/A16
40  P51/A17
41  P52/A18
42  P53/A19
43  P60/#WAIT
44  MD0  in
45  MD1  in
46
47  #STBY  in
48  #RES  in
49  #NMI  in
50  VSS  pwr
51  EXTAL  in
52  XTAL  pas
53  VCC  pwr
54  P63/#AS
55  P64/#RD
56  P65/#WR
57  FWE
58  AVSS  pwr
59  P70/AN0
60  P71/AN1
61  P72/AN2
62  P73/AN3
63  P74/AN4
64  P75/AN5
65  P76/AN6
66  P77/AN7
67  AVCC  pwr
68  P80/#IRQ0
69  P81/#IRQ1
70  P91/TXD1
71  P93/RXD1
72  P95/SCK1/#IRQ5
73  PA0/TP1/TCLKA/#TEND0
74  PA1/TP1/TCLKB/#TEND1
75  PA2/TP2/TIOCA0/TCLKC
76  PA3/TP3/TIOCB0/TCLKD
77  PA4/TP4/TIOCA1/A23
78  PA5/TP5/TIOCB1/A22
79  PA6/TP6/TIOCA2/A21
80  PA7/TP7/TIOCB2/A20

## H8/3022TE  [TQFP80-14X14]
Pads as for QFP80-17X17

## Footprint QFP80-17X17 (pad centres in mm)
QFP80 17mm x 17mm 0.65mm pin pitch
smd 1.8 x 0.4: 1 -8.6,6.175; 2 -8.6,5.525; 3 -8.6,4.875; 4 -8.6,4.225; 5 -8.6,3.575; 6 -8.6,2.925; 7 -8.6,2.275; 8 -8.6,1.625; 9 -8.6,0.975; 10 -8.6,0.325; 11 -8.6,-0.325; 12 -8.6,-0.975; 13 -8.6,-1.625; 14 -8.6,-2.275; 15 -8.6,-2.925; 16 -8.6,-3.575; 17 -8.6,-4.225; 18 -8.6,-4.875; 19 -8.6,-5.525; 20 -8.6,-6.175; 41 8.6,-6.175; 42 8.6,-5.525; 43 8.6,-4.875; 44 8.6,-4.225; 45 8.6,-3.575; 46 8.6,-2.925; 47 8.6,-2.275; 48 8.6,-1.625; 49 8.6,-0.975; 50 8.6,-0.325; 51 8.6,0.325; 52 8.6,0.975; 53 8.6,1.625; 54 8.6,2.275; 55 8.6,2.925; 56 8.6,3.575; 57 8.6,4.225; 58 8.6,4.875; 59 8.6,5.525; 60 8.6,6.175
smd 0.4 x 1.8: 21 -6.175,-8.6; 22 -5.525,-8.6; 23 -4.875,-8.6; 24 -4.225,-8.6; 25 -3.575,-8.6; 26 -2.925,-8.6; 27 -2.275,-8.6; 28 -1.625,-8.6; 29 -0.975,-8.6; 30 -0.325,-8.6; 31 0.325,-8.6; 32 0.975,-8.6; 33 1.625,-8.6; 34 2.275,-8.6; 35 2.925,-8.6; 36 3.575,-8.6; 37 4.225,-8.6; 38 4.875,-8.6; 39 5.525,-8.6; 40 6.175,-8.6; 61 6.175,8.6; 62 5.525,8.6; 63 4.875,8.6; 64 4.225,8.6; 65 3.575,8.6; 66 2.925,8.6; 67 2.275,8.6; 68 1.625,8.6; 69 0.975,8.6; 70 0.325,8.6; 71 -0.325,8.6; 72 -0.975,8.6; 73 -1.625,8.6; 74 -2.275,8.6; 75 -2.925,8.6; 76 -3.575,8.6; 77 -4.225,8.6; 78 -4.875,8.6; 79 -5.525,8.6; 80 -6.175,8.6

## Footprint TQFP80-14X14 (pad centres in mm)
TQFP80 14mm x 14mm 0.5mm pin pitch
smd 0.35 x 1.8: 1 -4.75,7; 2 -4.25,7; 3 -3.75,7; 4 -3.25,7; 5 -2.75,7; 6 -2.25,7; 7 -1.75,7; 8 -1.25,7; 9 -0.75,7; 10 -0.25,7; 11 0.25,7; 12 0.75,7; 13 1.25,7; 14 1.75,7; 15 2.25,7; 16 2.75,7; 17 3.25,7; 18 3.75,7; 19 4.25,7; 20 4.75,7; 41 4.75,-7; 42 4.25,-7; 43 3.75,-7; 44 3.25,-7; 45 2.75,-7; 46 2.25,-7; 47 1.75,-7; 48 1.25,-7; 49 0.75,-7; 50 0.25,-7; 51 -0.25,-7; 52 -0.75,-7; 53 -1.25,-7; 54 -1.75,-7; 55 -2.25,-7; 56 -2.75,-7; 57 -3.25,-7; 58 -3.75,-7; 59 -4.25,-7; 60 -4.75,-7
smd 1.8 x 0.35: 21 7,4.75; 22 7,4.25; 23 7,3.75; 24 7,3.25; 25 7,2.75; 26 7,2.25; 27 7,1.75; 28 7,1.25; 29 7,0.75; 30 7,0.25; 31 7,-0.25; 32 7,-0.75; 33 7,-1.25; 34 7,-1.75; 35 7,-2.25; 36 7,-2.75; 37 7,-3.25; 38 7,-3.75; 39 7,-4.25; 40 7,-4.75; 61 -7,-4.75; 62 -7,-4.25; 63 -7,-3.75; 64 -7,-3.25; 65 -7,-2.75; 66 -7,-2.25; 67 -7,-1.75; 68 -7,-1.25; 69 -7,-0.75; 70 -7,-0.25; 71 -7,0.25; 72 -7,0.75; 73 -7,1.25; 74 -7,1.75; 75 -7,2.25; 76 -7,2.75; 77 -7,3.25; 78 -7,3.75; 79 -7,4.25; 80 -7,4.75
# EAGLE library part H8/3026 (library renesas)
H8/3024 and H8/3026 3V in 100 QFP

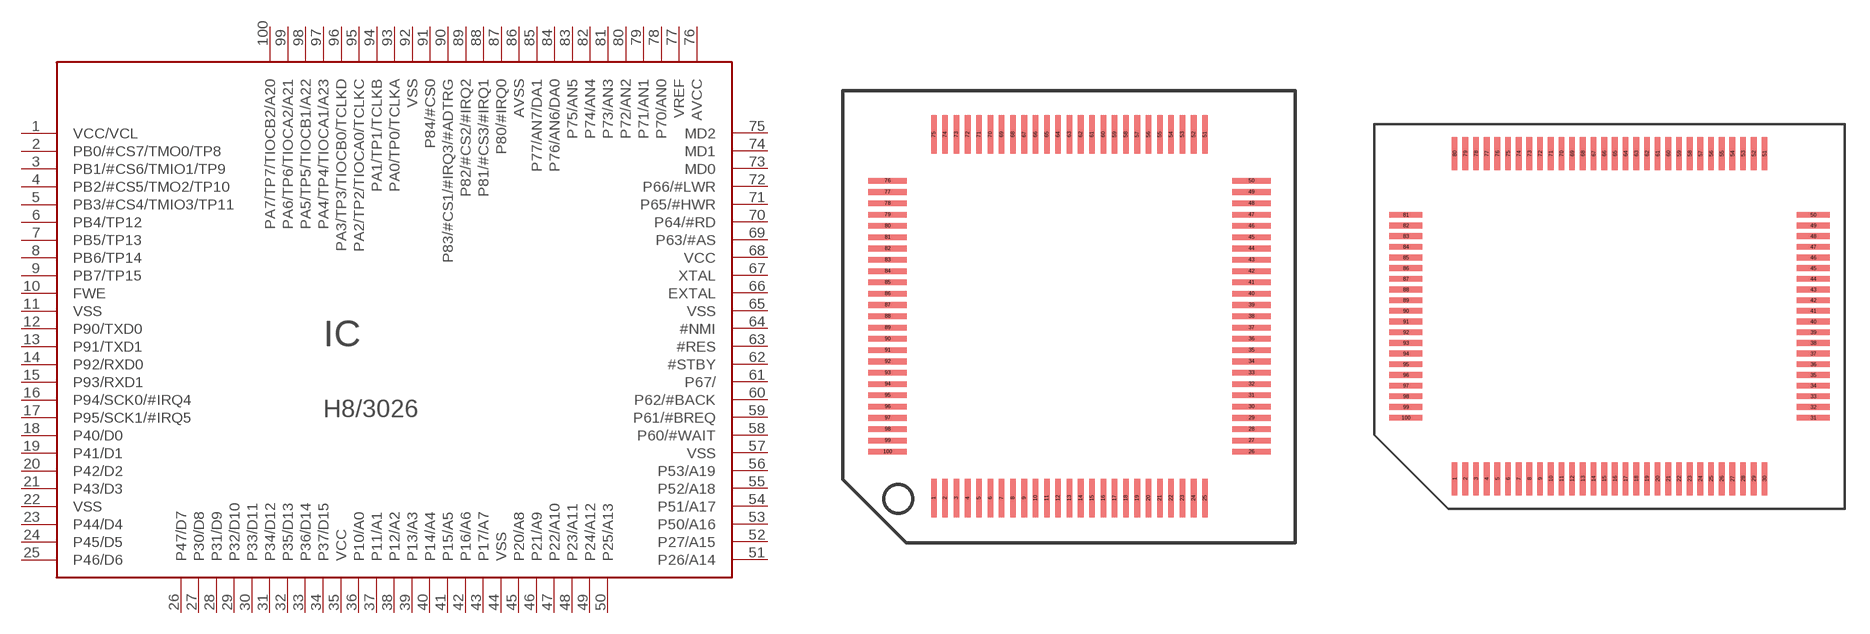
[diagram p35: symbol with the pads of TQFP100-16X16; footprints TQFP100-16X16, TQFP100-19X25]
Designator prefix IC

## H8/3026TE  [TQFP100-16X16]
1  VCC/VCL  pwr
2  PB0/#CS7/TMO0/TP8
3  PB1/#CS6/TMIO1/TP9
4  PB2/#CS5/TMO2/TP10
5  PB3/#CS4/TMIO3/TP11
6  PB4/TP12
7  PB5/TP13
8  PB6/TP14
9  PB7/TP15
10  FWE
11  VSS  pwr
12  P90/TXD0
13  P91/TXD1
14  P92/RXD0
15  P93/RXD1
16  P94/SCK0/#IRQ4
17  P95/SCK1/#IRQ5
18  P40/D0
19  P41/D1
20  P42/D2
21  P43/D3
22  VSS  pwr
23  P44/D4
24  P45/D5
25  P46/D6
26  P47/D7
27  P30/D8
28  P31/D9
29  P32/D10
30  P33/D11
31  P34/D12
32  P35/D13
33  P36/D14
34  P37/D15
35  VCC  pwr
36  P10/A0
37  P11/A1
38  P12/A2
39  P13/A3
40  P14/A4
41  P15/A5
42  P16/A6
43  P17/A7
44  VSS  pwr
45  P20/A8
46  P21/A9
47  P22/A10
48  P23/A11
49  P24/A12
50  P25/A13
51  P26/A14
52  P27/A15
53  P50/A16
54  P51/A17
55  P52/A18
56  P53/A19
57  VSS  pwr
58  P60/#WAIT
59  P61/#BREQ
60  P62/#BACK
61  P67/
62  #STBY  in
63  #RES  in
64  #NMI  in
65  VSS  pwr
66  EXTAL  in
67  XTAL  pas
68  VCC  pwr
69  P63/#AS
70  P64/#RD
71  P65/#HWR
72  P66/#LWR
73  MD0  in
74  MD1  in
75  MD2  in
76  AVCC  pwr
77  VREF  pas
78  P70/AN0
79  P71/AN1
80  P72/AN2
81  P73/AN3
82  P74/AN4
83  P75/AN5
84  P76/AN6/DA0
85  P77/AN7/DA1
86  AVSS  pwr
87  P80/#IRQ0
88  P81/#CS3/#IRQ1
89  P82/#CS2/#IRQ2
90  P83/#CS1/#IRQ3/#ADTRG
91  P84/#CS0
92  VSS  pwr
93  PA0/TP0/TCLKA
94  PA1/TP1/TCLKB
95  PA2/TP2/TIOCA0/TCLKC
96  PA3/TP3/TIOCB0/TCLKD
97  PA4/TP4/TIOCA1/A23
98  PA5/TP5/TIOCB1/A22
99  PA6/TP6/TIOCA2/A21
100  PA7/TP7/TIOCB2/A20

## H8/3026FP  [TQFP100-19X25]
1  PA6/TP6/TIOCA2/A21
2  PA7/TP7/TIOCB2/A20
3  VCC/VCL  pwr
4  PB0/#CS7/TMO0/TP8
5  PB1/#CS6/TMIO1/TP9
6  PB2/#CS5/TMO2/TP10
7  PB3/#CS4/TMIO3/TP11
8  PB4/TP12
9  PB5/TP13
10  PB6/TP14
11  PB7/TP15
12  FWE
13  VSS  pwr
14  P90/TXD0
15  P91/TXD1
16  P92/RXD0
17  P93/RXD1
18  P94/SCK0/#IRQ4
19  P95/SCK1/#IRQ5
20  P40/D0
21  P41/D1
22  P42/D2
23  P43/D3
24  VSS  pwr
25  P44/D4
26  P45/D5
27  P46/D6
28  P47/D7
29  P30/D8
30  P31/D9
31  P32/D10
32  P33/D11
33  P34/D12
34  P35/D13
35  P36/D14
36  P37/D15
37  VCC  pwr
38  P10/A0
39  P11/A1
40  P12/A2
41  P13/A3
42  P14/A4
43  P15/A5
44  P16/A6
45  P17/A7
46  VSS  pwr
47  P20/A8
48  P21/A9
49  P22/A10
50  P23/A11
51  P24/A12
52  P25/A13
53  P26/A14
54  P27/A15
55  P50/A16
56  P51/A17
57  P52/A18
58  P53/A19
59  VSS  pwr
60  P60/#WAIT
61  P61/#BREQ
62  P62/#BACK
63  P67/
64  #STBY  in
65  #RES  in
66  #NMI  in
67  VSS  pwr
68  EXTAL  in
69  XTAL  pas
70  VCC  pwr
71  P63/#AS
72  P64/#RD
73  P65/#HWR
74  P66/#LWR
75  MD0  in
76  MD1  in
77  MD2  in
78  AVCC  pwr
79  VREF  pas
80  P70/AN0
81  P71/AN1
82  P72/AN2
83  P73/AN3
84  P74/AN4
85  P75/AN5
86  P76/AN6/DA0
87  P77/AN7/DA1
88  AVSS  pwr
89  P80/#IRQ0
90  P81/#CS3/#IRQ1
91  P82/#CS2/#IRQ2
92  P83/#CS1/#IRQ3/#ADTRG
93  P84/#CS0
94  VSS  pwr
95  PA0/TP0/TCLKA
96  PA1/TP1/TCLKB
97  PA2/TP2/TIOCA0/TCLKC
98  PA3/TP3/TIOCB0/TCLKD
99  PA4/TP4/TIOCA1/A23
100  PA5/TP5/TIOCB1/A22

## Footprint TQFP100-16X16 (pad centres in mm)
TQFP100 16x16mm 0.5mm pitch 0.25mm pad width
smd 0.25 x 1.7: 1 -6,-8.05; 2 -5.5,-8.05; 3 -5,-8.05; 4 -4.5,-8.05; 5 -4,-8.05; 6 -3.5,-8.05; 7 -3,-8.05; 8 -2.5,-8.05; 9 -2,-8.05; 10 -1.5,-8.05; 11 -1,-8.05; 12 -0.5,-8.05; 13 0,-8.05; 14 0.5,-8.05; 15 1,-8.05; 16 1.5,-8.05; 17 2,-8.05; 18 2.5,-8.05; 19 3,-8.05; 20 3.5,-8.05; 21 4,-8.05; 22 4.5,-8.05; 23 5,-8.05; 24 5.5,-8.05; 25 6,-8.05; 51 6,8.05; 52 5.5,8.05; 53 5,8.05; 54 4.5,8.05; 55 4,8.05; 56 3.5,8.05; 57 3,8.05; 58 2.5,8.05; 59 2,8.05; 60 1.5,8.05; 61 1,8.05; 62 0.5,8.05; 63 0,8.05; 64 -0.5,8.05; 65 -1,8.05; 66 -1.5,8.05; 67 -2,8.05; 68 -2.5,8.05; 69 -3,8.05; 70 -3.5,8.05; 71 -4,8.05; 72 -4.5,8.05; 73 -5,8.05; 74 -5.5,8.05; 75 -6,8.05
smd 1.7 x 0.25: 26 8.05,-6; 27 8.05,-5.5; 28 8.05,-5; 29 8.05,-4.5; 30 8.05,-4; 31 8.05,-3.5; 32 8.05,-3; 33 8.05,-2.5; 34 8.05,-2; 35 8.05,-1.5; 36 8.05,-1; 37 8.05,-0.5; 38 8.05,0; 39 8.05,0.5; 40 8.05,1; 41 8.05,1.5; 42 8.05,2; 43 8.05,2.5; 44 8.05,3; 45 8.05,3.5; 46 8.05,4; 47 8.05,4.5; 48 8.05,5; 49 8.05,5.5; 50 8.05,6; 76 -8.05,6; 77 -8.05,5.5; 78 -8.05,5; 79 -8.05,4.5; 80 -8.05,4; 81 -8.05,3.5; 82 -8.05,3; 83 -8.05,2.5; 84 -8.05,2; 85 -8.05,1.5; 86 -8.05,1; 87 -8.05,0.5; 88 -8.05,0; 89 -8.05,-0.5; 90 -8.05,-1; 91 -8.05,-1.5; 92 -8.05,-2; 93 -8.05,-2.5; 94 -8.05,-3; 95 -8.05,-3.5; 96 -8.05,-4; 97 -8.05,-4.5; 98 -8.05,-5; 99 -8.05,-5.5; 100 -8.05,-6

## Footprint TQFP100-19X25 (pad centres in mm)
PQFP100 19x25mm 0.65mm pitch 0.35mm pad width
smd 0.35 x 2: 1 -9.425,-9.9; 2 -8.775,-9.9; 3 -8.125,-9.9; 4 -7.475,-9.9; 5 -6.825,-9.9; 6 -6.175,-9.9; 7 -5.525,-9.9; 8 -4.875,-9.9; 9 -4.225,-9.9; 10 -3.575,-9.9; 11 -2.925,-9.9; 12 -2.275,-9.9; 13 -1.625,-9.9; 14 -0.975,-9.9; 15 -0.325,-9.9; 16 0.325,-9.9; 17 0.975,-9.9; 18 1.625,-9.9; 19 2.275,-9.9; 20 2.925,-9.9; 21 3.575,-9.9; 22 4.225,-9.9; 23 4.875,-9.9; 24 5.525,-9.9; 25 6.175,-9.9; 26 6.825,-9.9; 27 7.475,-9.9; 28 8.125,-9.9; 29 8.775,-9.9; 30 9.425,-9.9; 51 9.425,9.9; 52 8.775,9.9; 53 8.125,9.9; 54 7.475,9.9; 55 6.825,9.9; 56 6.175,9.9; 57 5.525,9.9; 58 4.875,9.9; 59 4.225,9.9; 60 3.575,9.9; 61 2.925,9.9; 62 2.275,9.9; 63 1.625,9.9; 64 0.975,9.9; 65 0.325,9.9; 66 -0.325,9.9; 67 -0.975,9.9; 68 -1.625,9.9; 69 -2.275,9.9; 70 -2.925,9.9; 71 -3.575,9.9; 72 -4.225,9.9; 73 -4.875,9.9; 74 -5.525,9.9; 75 -6.175,9.9; 76 -6.825,9.9; 77 -7.475,9.9; 78 -8.125,9.9; 79 -8.775,9.9; 80 -9.425,9.9
smd 2 x 0.35: 31 12.4,-6.175; 32 12.4,-5.525; 33 12.4,-4.875; 34 12.4,-4.225; 35 12.4,-3.575; 36 12.4,-2.925; 37 12.4,-2.275; 38 12.4,-1.625; 39 12.4,-0.975; 40 12.4,-0.325; 41 12.4,0.325; 42 12.4,0.975; 43 12.4,1.625; 44 12.4,2.275; 45 12.4,2.925; 46 12.4,3.575; 47 12.4,4.225; 48 12.4,4.875; 49 12.4,5.525; 50 12.4,6.175; 81 -12.39,6.175; 82 -12.39,5.525; 83 -12.39,4.875; 84 -12.39,4.225; 85 -12.39,3.575; 86 -12.39,2.925; 87 -12.39,2.275; 88 -12.39,1.625; 89 -12.39,0.975; 90 -12.39,0.325; 91 -12.39,-0.325; 92 -12.39,-0.975; 93 -12.39,-1.625; 94 -12.39,-2.275; 95 -12.39,-2.925; 96 -12.39,-3.575; 97 -12.39,-4.225; 98 -12.39,-4.875; 99 -12.39,-5.525; 100 -12.39,-6.175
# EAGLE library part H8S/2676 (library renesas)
H8S/2678 series in TQFP 144 22x22

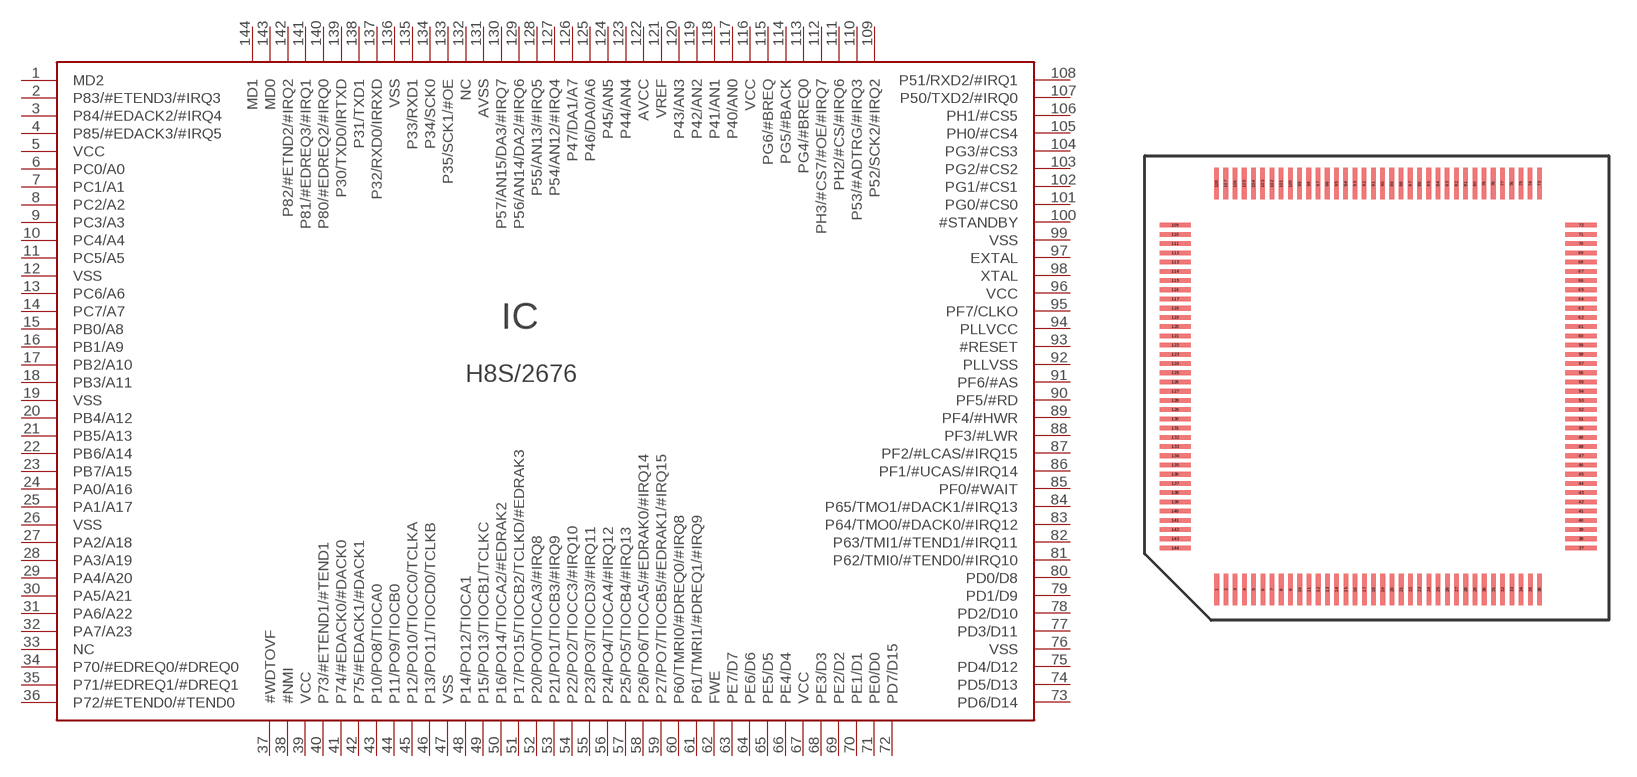
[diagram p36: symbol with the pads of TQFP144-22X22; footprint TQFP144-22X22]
Designator prefix IC

## H8S/2676  [TQFP144-22X22]
1  MD2  in
2  P83/#ETEND3/#IRQ3
3  P84/#EDACK2/#IRQ4
4  P85/#EDACK3/#IRQ5
5  VCC  pwr
6  PC0/A0
7  PC1/A1
8  PC2/A2
9  PC3/A3
10  PC4/A4
11  PC5/A5
12  VSS  pwr
13  PC6/A6
14  PC7/A7
15  PB0/A8
16  PB1/A9
17  PB2/A10
18  PB3/A11
19  VSS  pwr
20  PB4/A12
21  PB5/A13
22  PB6/A14
23  PB7/A15
24  PA0/A16
25  PA1/A17
26  VSS  pwr
27  PA2/A18
28  PA3/A19
29  PA4/A20
30  PA5/A21
31  PA6/A22
32  PA7/A23
33  NC  nc
34  P70/#EDREQ0/#DREQ0
35  P71/#EDREQ1/#DREQ1
36  P72/#ETEND0/#TEND0
37  #WDTOVF  out
38  #NMI  in
39  VCC  pwr
40  P73/#ETEND1/#TEND1
41  P74/#EDACK0/#DACK0
42  P75/#EDACK1/#DACK1
43  P10/PO8/TIOCA0
44  P11/PO9/TIOCB0
45  P12/PO10/TIOCC0/TCLKA
46  P13/PO11/TIOCD0/TCLKB
47  VSS  pwr
48  P14/PO12/TIOCA1
49  P15/PO13/TIOCB1/TCLKC
50  P16/PO14/TIOCA2/#EDRAK2
51  P17/PO15/TIOCB2/TCLKD/#EDRAK3
52  P20/PO0/TIOCA3/#IRQ8
53  P21/PO1/TIOCB3/#IRQ9
54  P22/PO2/TIOCC3/#IRQ10
55  P23/PO3/TIOCD3/#IRQ11
56  P24/PO4/TIOCA4/#IRQ12
57  P25/PO5/TIOCB4/#IRQ13
58  P26/PO6/TIOCA5/#EDRAK0/#IRQ14
59  P27/PO7/TIOCB5/#EDRAK1/#IRQ15
60  P60/TMRI0/#DREQ0/#IRQ8
61  P61/TMRI1/#DREQ1/#IRQ9
62  FWE
63  PE7/D7
64  PE6/D6
65  PE5/D5
66  PE4/D4
67  VCC  pwr
68  PE3/D3
69  PE2/D2
70  PE1/D1
71  PE0/D0
72  PD7/D15
73  PD6/D14
74  PD5/D13
75  PD4/D12
76  VSS  pwr
77  PD3/D11
78  PD2/D10
79  PD1/D9
80  PD0/D8
81  P62/TMI0/#TEND0/#IRQ10
82  P63/TMI1/#TEND1/#IRQ11
83  P64/TMO0/#DACK0/#IRQ12
84  P65/TMO1/#DACK1/#IRQ13
85  PF0/#WAIT
86  PF1/#UCAS/#IRQ14
87  PF2/#LCAS/#IRQ15
88  PF3/#LWR
89  PF4/#HWR
90  PF5/#RD
91  PF6/#AS
92  PLLVSS  pwr
93  #RESET  in
94  PLLVCC  pwr
95  PF7/CLKO
96  VCC  pwr
97  EXTAL  in
98  XTAL  pas
99  VSS  pwr
100  #STANDBY  in
101  PG0/#CS0
102  PG1/#CS1
103  PG2/#CS2
104  PG3/#CS3
105  PH0/#CS4
106  PH1/#CS5
107  P50/TXD2/#IRQ0
108  P51/RXD2/#IRQ1
109  P52/SCK2/#IRQ2
110  P53/#ADTRG/#IRQ3
111  PH2/#CS/#IRQ6
112  PH3/#CS7/#OE/#IRQ7
113  PG4/#BREQ0
114  PG5/#BACK
115  PG6/#BREQ
116  VCC  pwr
117  P40/AN0
118  P41/AN1
119  P42/AN2
120  P43/AN3
121  VREF  pwr
122  AVCC  pwr
123  P44/AN4
124  P45/AN5
125  P46/DA0/A6
126  P47/DA1/A7
127  P54/AN12/#IRQ4
128  P55/AN13/#IRQ5
129  P56/AN14/DA2/#IRQ6
130  P57/AN15/DA3/#IRQ7
131  AVSS  pwr
132  NC  nc
133  P35/SCK1/#OE
134  P34/SCK0
135  P33/RXD1
136  VSS  pwr
137  P32/RXD0/IRRXD
138  P31/TXD1
139  P30/TXD0/IRTXD
140  P80/#EDREQ2/#IRQ0
141  P81/#EDREQ3/#IRQ1
142  P82/#ETND2/#IRQ2
143  MD0  in
144  MD1  in

## Footprint TQFP144-22X22 (pad centres in mm)
TQFP144 pin 22 x 22 mm, pin pitch 0.5mm 0.25mm pad width
smd 0.25 x 1.7: 1 -8.75,-11.005; 2 -8.25,-11.005; 3 -7.75,-11.005; 4 -7.25,-11.005; 5 -6.75,-11.005; 6 -6.25,-11.005; 7 -5.75,-11.005; 8 -5.25,-11.005; 9 -4.75,-11.005; 10 -4.25,-11.005; 11 -3.75,-11.005; 12 -3.25,-11.005; 13 -2.75,-11.005; 14 -2.25,-11.005; 15 -1.75,-11.005; 16 -1.25,-11.005; 17 -0.75,-11.005; 18 -0.25,-11.005; 19 0.25,-11.005; 20 0.75,-11.005; 21 1.25,-11.005; 22 1.75,-11.005; 23 2.25,-11.005; 24 2.75,-11.005; 25 3.25,-11.005; 26 3.75,-11.005; 27 4.25,-11.005; 28 4.75,-11.005; 29 5.25,-11.005; 30 5.75,-11.005; 31 6.25,-11.005; 32 6.75,-11.005; 33 7.25,-11.005; 34 7.75,-11.005; 35 8.25,-11.005; 36 8.75,-11.005; 73 8.74,10.995; 74 8.24,10.995; 75 7.74,10.995; 76 7.24,10.995; 77 6.74,10.995; 78 6.24,10.995; 79 5.74,10.995; 80 5.24,10.995; 81 4.74,10.995; 82 4.24,10.995; 83 3.74,10.995; 84 3.24,10.995; 85 2.74,10.995; 86 2.24,10.995; 87 1.74,10.995; 88 1.24,10.995; 89 0.74,10.995; 90 0.24,10.995; 91 -0.26,10.995; 92 -0.76,10.995; 93 -1.26,10.995; 94 -1.76,10.995; 95 -2.26,10.995; 96 -2.76,10.995; 97 -3.26,10.995; 98 -3.76,10.995; 99 -4.26,10.995; 100 -4.76,10.995; 101 -5.26,10.995; 102 -5.76,10.995; 103 -6.26,10.995; 104 -6.76,10.995; 105 -7.26,10.995; 106 -7.76,10.995; 107 -8.26,10.995; 108 -8.76,10.995
smd 1.7 x 0.25: 37 11,-8.755; 38 11,-8.255; 39 11,-7.755; 40 11,-7.255; 41 11,-6.755; 42 11,-6.255; 43 11,-5.755; 44 11,-5.255; 45 11,-4.755; 46 11,-4.255; 47 11,-3.755; 48 11,-3.255; 49 11,-2.755; 50 11,-2.255; 51 11,-1.755; 52 11,-1.255; 53 11,-0.755; 54 11,-0.255; 55 11,0.245; 56 11,0.745; 57 11,1.245; 58 11,1.745; 59 11,2.245; 60 11,2.745; 61 11,3.245; 62 11,3.745; 63 11,4.245; 64 11,4.745; 65 11,5.245; 66 11,5.745; 67 11,6.245; 68 11,6.745; 69 11,7.245; 70 11,7.745; 71 11,8.245; 72 11,8.745; 109 -11,8.745; 110 -11,8.245; 111 -11,7.745; 112 -11,7.245; 113 -11,6.745; 114 -11,6.245; 115 -11,5.745; 116 -11,5.245; 117 -11,4.745; 118 -11,4.245; 119 -11,3.745; 120 -11,3.245; 121 -11,2.745; 122 -11,2.245; 123 -11,1.745; 124 -11,1.245; 125 -11,0.745; 126 -11,0.245; 127 -11,-0.255; 128 -11,-0.755; 129 -11,-1.255; 130 -11,-1.755; 131 -11,-2.255; 132 -11,-2.755; 133 -11,-3.255; 134 -11,-3.755; 135 -11,-4.255; 136 -11,-4.755; 137 -11,-5.255; 138 -11,-5.755; 139 -11,-6.255; 140 -11,-6.755; 141 -11,-7.255; 142 -11,-7.755; 143 -11,-8.255; 144 -11,-8.755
